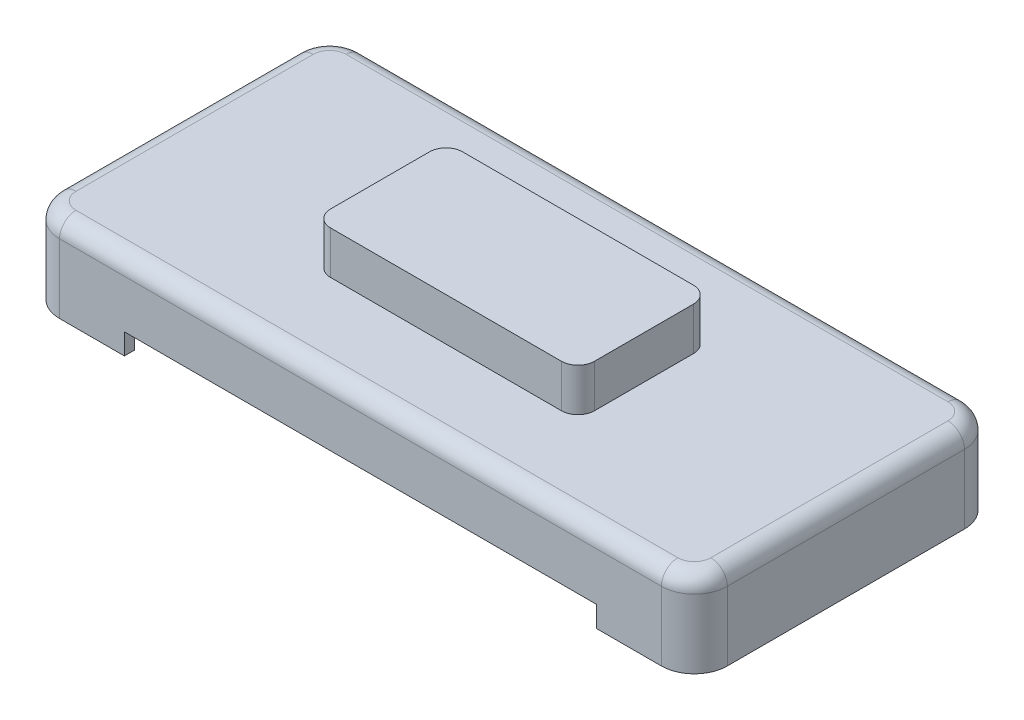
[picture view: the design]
ISO-10303-21;
HEADER;
FILE_DESCRIPTION(('STEP AP214'),'2;1');
FILE_NAME('part.step','',(''),(''),'','','');
FILE_SCHEMA(('AUTOMOTIVE_DESIGN { 1 0 10303 214 1 1 1 1 }'));
ENDSEC;
DATA;
#1=APPLICATION_CONTEXT('core data for automotive mechanical design processes');
#2=APPLICATION_PROTOCOL_DEFINITION('international standard','automotive_design',2000,#1);
#3=PRODUCT_CONTEXT('',#1,'mechanical');
#4=PRODUCT('Part','Part','',(#3));
#5=PRODUCT_RELATED_PRODUCT_CATEGORY('part','',(#4));
#6=PRODUCT_DEFINITION_FORMATION('','',#4);
#7=PRODUCT_DEFINITION_CONTEXT('part definition',#1,'design');
#8=PRODUCT_DEFINITION('design','',#6,#7);
#9=PRODUCT_DEFINITION_SHAPE('','',#8);
#10=(LENGTH_UNIT() NAMED_UNIT(*) SI_UNIT(.MILLI.,.METRE.));
#11=(NAMED_UNIT(*) PLANE_ANGLE_UNIT() SI_UNIT($,.RADIAN.));
#12=(NAMED_UNIT(*) SI_UNIT($,.STERADIAN.) SOLID_ANGLE_UNIT());
#13=UNCERTAINTY_MEASURE_WITH_UNIT(LENGTH_MEASURE(1.E-05),#10,'distance_accuracy_value','');
#14=(GEOMETRIC_REPRESENTATION_CONTEXT(3) GLOBAL_UNCERTAINTY_ASSIGNED_CONTEXT((#13)) GLOBAL_UNIT_ASSIGNED_CONTEXT((#10,
#11,#12)) REPRESENTATION_CONTEXT('',''));
#15=CARTESIAN_POINT('',(0.,0.,0.));
#16=DIRECTION('',(0.,0.,1.));
#17=DIRECTION('',(1.,0.,0.));
#18=AXIS2_PLACEMENT_3D('',#15,#16,#17);
#19=CARTESIAN_POINT('',(-40.,38.9249069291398,20.));
#20=DIRECTION('',(1.,0.,0.));
#21=DIRECTION('',(0.,1.,0.));
#22=AXIS2_PLACEMENT_3D('',#19,#20,#21);
#23=PLANE('',#22);
#24=DIRECTION('',(0.,0.,-1.));
#25=VECTOR('',#24,1.);
#26=CARTESIAN_POINT('',(-40.,13.9249069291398,20.));
#27=LINE('',#26,#25);
#28=CARTESIAN_POINT('',(-40.,13.9249069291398,-15.));
#29=VERTEX_POINT('',#28);
#30=CARTESIAN_POINT('',(-40.,13.9249069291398,15.));
#31=VERTEX_POINT('',#30);
#32=EDGE_CURVE('E119',#29,#31,#27,.F.);
#33=ORIENTED_EDGE('',*,*,#32,.T.);
#34=DIRECTION('',(0.,-1.,0.));
#35=VECTOR('',#34,1.);
#36=CARTESIAN_POINT('',(-40.,38.9249069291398,15.));
#37=LINE('',#36,#35);
#38=CARTESIAN_POINT('',(-40.,38.9249069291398,15.));
#39=VERTEX_POINT('',#38);
#40=EDGE_CURVE('E154',#31,#39,#37,.F.);
#41=ORIENTED_EDGE('',*,*,#40,.T.);
#42=DIRECTION('',(0.,0.,-1.));
#43=VECTOR('',#42,1.);
#44=CARTESIAN_POINT('',(-40.,38.9249069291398,20.));
#45=LINE('',#44,#43);
#46=CARTESIAN_POINT('',(-40.,38.9249069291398,-15.));
#47=VERTEX_POINT('',#46);
#48=EDGE_CURVE('E181',#39,#47,#45,.T.);
#49=ORIENTED_EDGE('',*,*,#48,.T.);
#50=DIRECTION('',(0.,-1.,0.));
#51=VECTOR('',#50,1.);
#52=CARTESIAN_POINT('',(-40.,38.9249069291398,-15.));
#53=LINE('',#52,#51);
#54=EDGE_CURVE('E147',#47,#29,#53,.T.);
#55=ORIENTED_EDGE('',*,*,#54,.T.);
#56=EDGE_LOOP('',(#33,#41,#49,#55));
#57=FACE_BOUND('',#56,.T.);
#58=ADVANCED_FACE('F37',(#57),#23,.F.);
#59=CARTESIAN_POINT('',(-40.,8.92490692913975,20.));
#60=DIRECTION('',(0.,1.,0.));
#61=DIRECTION('',(0.,0.,1.));
#62=AXIS2_PLACEMENT_3D('',#59,#60,#61);
#63=PLANE('',#62);
#64=DIRECTION('',(1.,0.,0.));
#65=VECTOR('',#64,1.);
#66=CARTESIAN_POINT('',(-40.,8.92490692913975,15.));
#67=LINE('',#66,#65);
#68=CARTESIAN_POINT('',(35.,8.92490692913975,15.));
#69=VERTEX_POINT('',#68);
#70=CARTESIAN_POINT('',(-35.,8.92490692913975,15.));
#71=VERTEX_POINT('',#70);
#72=EDGE_CURVE('E145',#69,#71,#67,.F.);
#73=ORIENTED_EDGE('',*,*,#72,.T.);
#74=DIRECTION('',(0.,0.,-1.));
#75=VECTOR('',#74,1.);
#76=CARTESIAN_POINT('',(-35.,8.92490692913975,20.));
#77=LINE('',#76,#75);
#78=CARTESIAN_POINT('',(-35.,8.92490692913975,-15.));
#79=VERTEX_POINT('',#78);
#80=EDGE_CURVE('E117',#71,#79,#77,.T.);
#81=ORIENTED_EDGE('',*,*,#80,.T.);
#82=DIRECTION('',(1.,0.,0.));
#83=VECTOR('',#82,1.);
#84=CARTESIAN_POINT('',(-40.,8.92490692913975,-15.));
#85=LINE('',#84,#83);
#86=CARTESIAN_POINT('',(35.,8.92490692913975,-15.));
#87=VERTEX_POINT('',#86);
#88=EDGE_CURVE('E134',#79,#87,#85,.T.);
#89=ORIENTED_EDGE('',*,*,#88,.T.);
#90=DIRECTION('',(0.,0.,-1.));
#91=VECTOR('',#90,1.);
#92=CARTESIAN_POINT('',(35.,8.92490692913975,20.));
#93=LINE('',#92,#91);
#94=EDGE_CURVE('E140',#87,#69,#93,.F.);
#95=ORIENTED_EDGE('',*,*,#94,.T.);
#96=EDGE_LOOP('',(#73,#81,#89,#95));
#97=FACE_BOUND('',#96,.T.);
#98=ADVANCED_FACE('F143',(#97),#63,.F.);
#99=CARTESIAN_POINT('',(40.,38.9249069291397,20.));
#100=DIRECTION('',(-1.,0.,0.));
#101=DIRECTION('',(0.,0.,1.));
#102=AXIS2_PLACEMENT_3D('',#99,#100,#101);
#103=PLANE('',#102);
#104=DIRECTION('',(0.,0.,-1.));
#105=VECTOR('',#104,1.);
#106=CARTESIAN_POINT('',(40.,13.9249069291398,20.));
#107=LINE('',#106,#105);
#108=CARTESIAN_POINT('',(40.,13.9249069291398,15.));
#109=VERTEX_POINT('',#108);
#110=CARTESIAN_POINT('',(40.,13.9249069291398,-15.));
#111=VERTEX_POINT('',#110);
#112=EDGE_CURVE('E164',#109,#111,#107,.T.);
#113=ORIENTED_EDGE('',*,*,#112,.T.);
#114=DIRECTION('',(0.,1.,0.));
#115=VECTOR('',#114,1.);
#116=CARTESIAN_POINT('',(40.,38.9249069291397,-15.));
#117=LINE('',#116,#115);
#118=CARTESIAN_POINT('',(40.,38.9249069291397,-15.));
#119=VERTEX_POINT('',#118);
#120=EDGE_CURVE('E166',#111,#119,#117,.T.);
#121=ORIENTED_EDGE('',*,*,#120,.T.);
#122=DIRECTION('',(0.,0.,-1.));
#123=VECTOR('',#122,1.);
#124=CARTESIAN_POINT('',(40.,38.9249069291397,20.));
#125=LINE('',#124,#123);
#126=CARTESIAN_POINT('',(40.,38.9249069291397,15.));
#127=VERTEX_POINT('',#126);
#128=EDGE_CURVE('E141',#127,#119,#125,.T.);
#129=ORIENTED_EDGE('',*,*,#128,.F.);
#130=DIRECTION('',(0.,1.,0.));
#131=VECTOR('',#130,1.);
#132=CARTESIAN_POINT('',(40.,8.92490692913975,15.));
#133=LINE('',#132,#131);
#134=EDGE_CURVE('E162',#127,#109,#133,.F.);
#135=ORIENTED_EDGE('',*,*,#134,.T.);
#136=EDGE_LOOP('',(#113,#121,#129,#135));
#137=FACE_BOUND('',#136,.T.);
#138=ADVANCED_FACE('F249',(#137),#103,.F.);
#139=CARTESIAN_POINT('',(-40.,38.9249069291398,20.));
#140=DIRECTION('',(0.,-1.,0.));
#141=DIRECTION('',(1.,0.,0.));
#142=AXIS2_PLACEMENT_3D('',#139,#140,#141);
#143=PLANE('',#142);
#144=ORIENTED_EDGE('',*,*,#48,.F.);
#145=CARTESIAN_POINT('',(-35.,38.9249069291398,15.));
#146=DIRECTION('',(0.,-1.,0.));
#147=DIRECTION('',(1.,0.,0.));
#148=AXIS2_PLACEMENT_3D('',#145,#146,#147);
#149=CIRCLE('',#148,5.);
#150=CARTESIAN_POINT('',(-35.,38.9249069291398,20.));
#151=VERTEX_POINT('',#150);
#152=EDGE_CURVE('E12',#39,#151,#149,.F.);
#153=ORIENTED_EDGE('',*,*,#152,.T.);
#154=DIRECTION('',(-1.,0.,0.));
#155=VECTOR('',#154,1.);
#156=CARTESIAN_POINT('',(-40.,38.9249069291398,20.));
#157=LINE('',#156,#155);
#158=CARTESIAN_POINT('',(35.,38.9249069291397,20.));
#159=VERTEX_POINT('',#158);
#160=EDGE_CURVE('E188',#159,#151,#157,.T.);
#161=ORIENTED_EDGE('',*,*,#160,.F.);
#162=CARTESIAN_POINT('',(35.,38.9249069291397,15.));
#163=DIRECTION('',(0.,-1.,0.));
#164=DIRECTION('',(1.,0.,0.));
#165=AXIS2_PLACEMENT_3D('',#162,#163,#164);
#166=CIRCLE('',#165,5.);
#167=EDGE_CURVE('E172',#159,#127,#166,.F.);
#168=ORIENTED_EDGE('',*,*,#167,.T.);
#169=ORIENTED_EDGE('',*,*,#128,.T.);
#170=CARTESIAN_POINT('',(35.,38.9249069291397,-15.));
#171=DIRECTION('',(0.,-1.,0.));
#172=DIRECTION('',(1.,0.,0.));
#173=AXIS2_PLACEMENT_3D('',#170,#171,#172);
#174=CIRCLE('',#173,5.);
#175=CARTESIAN_POINT('',(35.,38.9249069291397,-20.));
#176=VERTEX_POINT('',#175);
#177=EDGE_CURVE('E174',#119,#176,#174,.F.);
#178=ORIENTED_EDGE('',*,*,#177,.T.);
#179=DIRECTION('',(-1.,0.,0.));
#180=VECTOR('',#179,1.);
#181=CARTESIAN_POINT('',(-40.,38.9249069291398,-20.));
#182=LINE('',#181,#180);
#183=CARTESIAN_POINT('',(-35.,38.9249069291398,-20.));
#184=VERTEX_POINT('',#183);
#185=EDGE_CURVE('E183',#176,#184,#182,.T.);
#186=ORIENTED_EDGE('',*,*,#185,.T.);
#187=CARTESIAN_POINT('',(-35.,38.9249069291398,-15.));
#188=DIRECTION('',(0.,-1.,0.));
#189=DIRECTION('',(1.,0.,0.));
#190=AXIS2_PLACEMENT_3D('',#187,#188,#189);
#191=CIRCLE('',#190,5.);
#192=EDGE_CURVE('E44',#184,#47,#191,.F.);
#193=ORIENTED_EDGE('',*,*,#192,.T.);
#194=EDGE_LOOP('',(#144,#153,#161,#168,#169,#178,#186,#193));
#195=FACE_BOUND('',#194,.T.);
#196=ADVANCED_FACE('F180',(#195),#143,.F.);
#197=CARTESIAN_POINT('',(-40.,8.92490692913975,20.));
#198=DIRECTION('',(0.,0.,1.));
#199=DIRECTION('',(1.,0.,0.));
#200=AXIS2_PLACEMENT_3D('',#197,#198,#199);
#201=PLANE('',#200);
#202=ORIENTED_EDGE('',*,*,#160,.T.);
#203=DIRECTION('',(0.,-1.,0.));
#204=VECTOR('',#203,1.);
#205=CARTESIAN_POINT('',(-35.,8.92490692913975,20.));
#206=LINE('',#205,#204);
#207=CARTESIAN_POINT('',(-35.,13.9249069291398,20.));
#208=VERTEX_POINT('',#207);
#209=EDGE_CURVE('E160',#151,#208,#206,.T.);
#210=ORIENTED_EDGE('',*,*,#209,.T.);
#211=DIRECTION('',(1.,0.,0.));
#212=VECTOR('',#211,1.);
#213=CARTESIAN_POINT('',(40.,13.9249069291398,20.));
#214=LINE('',#213,#212);
#215=CARTESIAN_POINT('',(35.,13.9249069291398,20.));
#216=VERTEX_POINT('',#215);
#217=EDGE_CURVE('E158',#208,#216,#214,.T.);
#218=ORIENTED_EDGE('',*,*,#217,.T.);
#219=DIRECTION('',(0.,1.,0.));
#220=VECTOR('',#219,1.);
#221=CARTESIAN_POINT('',(35.,38.9249069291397,20.));
#222=LINE('',#221,#220);
#223=EDGE_CURVE('E156',#216,#159,#222,.T.);
#224=ORIENTED_EDGE('',*,*,#223,.T.);
#225=EDGE_LOOP('',(#202,#210,#218,#224));
#226=FACE_BOUND('',#225,.T.);
#227=ADVANCED_FACE('F241',(#226),#201,.T.);
#228=CARTESIAN_POINT('',(-40.,8.92490692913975,-20.));
#229=DIRECTION('',(0.,0.,1.));
#230=DIRECTION('',(1.,0.,0.));
#231=AXIS2_PLACEMENT_3D('',#228,#229,#230);
#232=PLANE('',#231);
#233=DIRECTION('',(1.,0.,0.));
#234=VECTOR('',#233,1.);
#235=CARTESIAN_POINT('',(-40.,13.9249069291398,-20.));
#236=LINE('',#235,#234);
#237=CARTESIAN_POINT('',(35.,13.9249069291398,-20.));
#238=VERTEX_POINT('',#237);
#239=CARTESIAN_POINT('',(-35.,13.9249069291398,-20.));
#240=VERTEX_POINT('',#239);
#241=EDGE_CURVE('E51',#238,#240,#236,.F.);
#242=ORIENTED_EDGE('',*,*,#241,.T.);
#243=DIRECTION('',(0.,-1.,0.));
#244=VECTOR('',#243,1.);
#245=CARTESIAN_POINT('',(-35.,8.92490692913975,-20.));
#246=LINE('',#245,#244);
#247=EDGE_CURVE('E170',#240,#184,#246,.F.);
#248=ORIENTED_EDGE('',*,*,#247,.T.);
#249=ORIENTED_EDGE('',*,*,#185,.F.);
#250=DIRECTION('',(0.,1.,0.));
#251=VECTOR('',#250,1.);
#252=CARTESIAN_POINT('',(35.,8.92490692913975,-20.));
#253=LINE('',#252,#251);
#254=EDGE_CURVE('E56',#176,#238,#253,.F.);
#255=ORIENTED_EDGE('',*,*,#254,.T.);
#256=EDGE_LOOP('',(#242,#248,#249,#255));
#257=FACE_BOUND('',#256,.T.);
#258=ADVANCED_FACE('F276',(#257),#232,.F.);
#259=CARTESIAN_POINT('',(35.,8.92490692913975,15.));
#260=DIRECTION('',(0.,-1.,0.));
#261=DIRECTION('',(0.,0.,-1.));
#262=AXIS2_PLACEMENT_3D('',#259,#260,#261);
#263=CYLINDRICAL_SURFACE('',#262,5.);
#264=ORIENTED_EDGE('',*,*,#167,.F.);
#265=ORIENTED_EDGE('',*,*,#223,.F.);
#266=CARTESIAN_POINT('',(35.,13.9249069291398,15.));
#267=DIRECTION('',(0.,-1.,0.));
#268=DIRECTION('',(0.,0.,-1.));
#269=AXIS2_PLACEMENT_3D('',#266,#267,#268);
#270=CIRCLE('',#269,5.);
#271=EDGE_CURVE('E212',#109,#216,#270,.T.);
#272=ORIENTED_EDGE('',*,*,#271,.F.);
#273=ORIENTED_EDGE('',*,*,#134,.F.);
#274=EDGE_LOOP('',(#264,#265,#272,#273));
#275=FACE_BOUND('',#274,.T.);
#276=ADVANCED_FACE('F244',(#275),#263,.T.);
#277=CARTESIAN_POINT('',(35.,13.9249069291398,20.));
#278=DIRECTION('',(0.,0.,-1.));
#279=DIRECTION('',(-1.,0.,0.));
#280=AXIS2_PLACEMENT_3D('',#277,#278,#279);
#281=CYLINDRICAL_SURFACE('',#280,5.);
#282=CARTESIAN_POINT('',(35.,13.9249069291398,-15.));
#283=DIRECTION('',(0.,0.,-1.));
#284=DIRECTION('',(-1.,0.,0.));
#285=AXIS2_PLACEMENT_3D('',#282,#283,#284);
#286=CIRCLE('',#285,5.);
#287=EDGE_CURVE('E206',#111,#87,#286,.T.);
#288=ORIENTED_EDGE('',*,*,#287,.F.);
#289=ORIENTED_EDGE('',*,*,#112,.F.);
#290=CARTESIAN_POINT('',(35.,13.9249069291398,15.));
#291=DIRECTION('',(0.,0.,1.));
#292=DIRECTION('',(1.,0.,0.));
#293=AXIS2_PLACEMENT_3D('',#290,#291,#292);
#294=CIRCLE('',#293,5.);
#295=EDGE_CURVE('E209',#69,#109,#294,.T.);
#296=ORIENTED_EDGE('',*,*,#295,.F.);
#297=ORIENTED_EDGE('',*,*,#94,.F.);
#298=EDGE_LOOP('',(#288,#289,#296,#297));
#299=FACE_BOUND('',#298,.T.);
#300=ADVANCED_FACE('F224',(#299),#281,.T.);
#301=CARTESIAN_POINT('',(35.,38.9249069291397,-15.));
#302=DIRECTION('',(0.,1.,0.));
#303=DIRECTION('',(0.,0.,1.));
#304=AXIS2_PLACEMENT_3D('',#301,#302,#303);
#305=CYLINDRICAL_SURFACE('',#304,5.);
#306=ORIENTED_EDGE('',*,*,#177,.F.);
#307=ORIENTED_EDGE('',*,*,#120,.F.);
#308=CARTESIAN_POINT('',(35.,13.9249069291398,-15.));
#309=DIRECTION('',(0.,-1.,0.));
#310=DIRECTION('',(0.,0.,-1.));
#311=AXIS2_PLACEMENT_3D('',#308,#309,#310);
#312=CIRCLE('',#311,5.);
#313=EDGE_CURVE('E203',#238,#111,#312,.T.);
#314=ORIENTED_EDGE('',*,*,#313,.F.);
#315=ORIENTED_EDGE('',*,*,#254,.F.);
#316=EDGE_LOOP('',(#306,#307,#314,#315));
#317=FACE_BOUND('',#316,.T.);
#318=ADVANCED_FACE('F252',(#317),#305,.T.);
#319=CARTESIAN_POINT('',(35.,13.9249069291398,15.));
#320=DIRECTION('',(0.,0.,1.));
#321=DIRECTION('',(1.,0.,0.));
#322=AXIS2_PLACEMENT_3D('',#319,#320,#321);
#323=SPHERICAL_SURFACE('',#322,5.);
#324=ORIENTED_EDGE('',*,*,#295,.T.);
#325=ORIENTED_EDGE('',*,*,#271,.T.);
#326=CARTESIAN_POINT('',(35.,13.9249069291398,15.));
#327=DIRECTION('',(1.,0.,0.));
#328=DIRECTION('',(0.,0.,-1.));
#329=AXIS2_PLACEMENT_3D('',#326,#327,#328);
#330=CIRCLE('',#329,5.);
#331=EDGE_CURVE('E200',#69,#216,#330,.F.);
#332=ORIENTED_EDGE('',*,*,#331,.F.);
#333=EDGE_LOOP('',(#324,#325,#332));
#334=FACE_BOUND('',#333,.T.);
#335=ADVANCED_FACE('F227',(#334),#323,.T.);
#336=CARTESIAN_POINT('',(35.,13.9249069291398,-15.));
#337=DIRECTION('',(0.,0.,1.));
#338=DIRECTION('',(1.,0.,0.));
#339=AXIS2_PLACEMENT_3D('',#336,#337,#338);
#340=SPHERICAL_SURFACE('',#339,5.);
#341=ORIENTED_EDGE('',*,*,#313,.T.);
#342=ORIENTED_EDGE('',*,*,#287,.T.);
#343=CARTESIAN_POINT('',(35.,13.9249069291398,-15.));
#344=DIRECTION('',(1.,0.,0.));
#345=DIRECTION('',(0.,0.,-1.));
#346=AXIS2_PLACEMENT_3D('',#343,#344,#345);
#347=CIRCLE('',#346,5.);
#348=EDGE_CURVE('E137',#238,#87,#347,.F.);
#349=ORIENTED_EDGE('',*,*,#348,.F.);
#350=EDGE_LOOP('',(#341,#342,#349));
#351=FACE_BOUND('',#350,.T.);
#352=ADVANCED_FACE('F254',(#351),#340,.T.);
#353=CARTESIAN_POINT('',(-35.,8.92490692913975,15.));
#354=DIRECTION('',(0.,1.,0.));
#355=DIRECTION('',(-1.,0.,0.));
#356=AXIS2_PLACEMENT_3D('',#353,#354,#355);
#357=CYLINDRICAL_SURFACE('',#356,5.);
#358=ORIENTED_EDGE('',*,*,#152,.F.);
#359=ORIENTED_EDGE('',*,*,#40,.F.);
#360=CARTESIAN_POINT('',(-35.,13.9249069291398,15.));
#361=DIRECTION('',(0.,-1.,0.));
#362=DIRECTION('',(1.,0.,0.));
#363=AXIS2_PLACEMENT_3D('',#360,#361,#362);
#364=CIRCLE('',#363,5.);
#365=EDGE_CURVE('E196',#208,#31,#364,.T.);
#366=ORIENTED_EDGE('',*,*,#365,.F.);
#367=ORIENTED_EDGE('',*,*,#209,.F.);
#368=EDGE_LOOP('',(#358,#359,#366,#367));
#369=FACE_BOUND('',#368,.T.);
#370=ADVANCED_FACE('F237',(#369),#357,.T.);
#371=CARTESIAN_POINT('',(-40.,13.9249069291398,15.));
#372=DIRECTION('',(-1.,0.,0.));
#373=DIRECTION('',(0.,0.,1.));
#374=AXIS2_PLACEMENT_3D('',#371,#372,#373);
#375=CYLINDRICAL_SURFACE('',#374,5.);
#376=ORIENTED_EDGE('',*,*,#331,.T.);
#377=ORIENTED_EDGE('',*,*,#217,.F.);
#378=CARTESIAN_POINT('',(-35.,13.9249069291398,15.));
#379=DIRECTION('',(-1.,0.,0.));
#380=DIRECTION('',(0.,0.,1.));
#381=AXIS2_PLACEMENT_3D('',#378,#379,#380);
#382=CIRCLE('',#381,5.);
#383=EDGE_CURVE('E131',#71,#208,#382,.T.);
#384=ORIENTED_EDGE('',*,*,#383,.F.);
#385=ORIENTED_EDGE('',*,*,#72,.F.);
#386=EDGE_LOOP('',(#376,#377,#384,#385));
#387=FACE_BOUND('',#386,.T.);
#388=ADVANCED_FACE('F230',(#387),#375,.T.);
#389=CARTESIAN_POINT('',(-40.,13.9249069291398,-15.));
#390=DIRECTION('',(1.,0.,0.));
#391=DIRECTION('',(0.,0.,-1.));
#392=AXIS2_PLACEMENT_3D('',#389,#390,#391);
#393=CYLINDRICAL_SURFACE('',#392,5.);
#394=ORIENTED_EDGE('',*,*,#348,.T.);
#395=ORIENTED_EDGE('',*,*,#88,.F.);
#396=CARTESIAN_POINT('',(-35.,13.9249069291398,-15.));
#397=DIRECTION('',(-1.,0.,0.));
#398=DIRECTION('',(0.,0.,1.));
#399=AXIS2_PLACEMENT_3D('',#396,#397,#398);
#400=CIRCLE('',#399,5.);
#401=EDGE_CURVE('E125',#240,#79,#400,.T.);
#402=ORIENTED_EDGE('',*,*,#401,.F.);
#403=ORIENTED_EDGE('',*,*,#241,.F.);
#404=EDGE_LOOP('',(#394,#395,#402,#403));
#405=FACE_BOUND('',#404,.T.);
#406=ADVANCED_FACE('F135',(#405),#393,.T.);
#407=CARTESIAN_POINT('',(-35.,38.9249069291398,-15.));
#408=DIRECTION('',(0.,-1.,0.));
#409=DIRECTION('',(1.,0.,0.));
#410=AXIS2_PLACEMENT_3D('',#407,#408,#409);
#411=CYLINDRICAL_SURFACE('',#410,5.);
#412=ORIENTED_EDGE('',*,*,#192,.F.);
#413=ORIENTED_EDGE('',*,*,#247,.F.);
#414=CARTESIAN_POINT('',(-35.,13.9249069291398,-15.));
#415=DIRECTION('',(0.,-1.,0.));
#416=DIRECTION('',(1.,0.,0.));
#417=AXIS2_PLACEMENT_3D('',#414,#415,#416);
#418=CIRCLE('',#417,5.);
#419=EDGE_CURVE('E129',#29,#240,#418,.T.);
#420=ORIENTED_EDGE('',*,*,#419,.F.);
#421=ORIENTED_EDGE('',*,*,#54,.F.);
#422=EDGE_LOOP('',(#412,#413,#420,#421));
#423=FACE_BOUND('',#422,.T.);
#424=ADVANCED_FACE('F190',(#423),#411,.T.);
#425=CARTESIAN_POINT('',(-35.,13.9249069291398,15.));
#426=DIRECTION('',(0.,0.,1.));
#427=DIRECTION('',(1.,0.,0.));
#428=AXIS2_PLACEMENT_3D('',#425,#426,#427);
#429=SPHERICAL_SURFACE('',#428,5.);
#430=ORIENTED_EDGE('',*,*,#383,.T.);
#431=ORIENTED_EDGE('',*,*,#365,.T.);
#432=CARTESIAN_POINT('',(-35.,13.9249069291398,15.));
#433=DIRECTION('',(0.,0.,1.));
#434=DIRECTION('',(1.,0.,0.));
#435=AXIS2_PLACEMENT_3D('',#432,#433,#434);
#436=CIRCLE('',#435,5.);
#437=EDGE_CURVE('E122',#71,#31,#436,.F.);
#438=ORIENTED_EDGE('',*,*,#437,.F.);
#439=EDGE_LOOP('',(#430,#431,#438));
#440=FACE_BOUND('',#439,.T.);
#441=ADVANCED_FACE('F234',(#440),#429,.T.);
#442=CARTESIAN_POINT('',(-35.,13.9249069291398,-15.));
#443=DIRECTION('',(0.,0.,1.));
#444=DIRECTION('',(1.,0.,0.));
#445=AXIS2_PLACEMENT_3D('',#442,#443,#444);
#446=SPHERICAL_SURFACE('',#445,5.);
#447=ORIENTED_EDGE('',*,*,#419,.T.);
#448=ORIENTED_EDGE('',*,*,#401,.T.);
#449=CARTESIAN_POINT('',(-35.,13.9249069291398,-15.));
#450=DIRECTION('',(0.,0.,-1.));
#451=DIRECTION('',(-1.,0.,0.));
#452=AXIS2_PLACEMENT_3D('',#449,#450,#451);
#453=CIRCLE('',#452,5.);
#454=EDGE_CURVE('E113',#29,#79,#453,.F.);
#455=ORIENTED_EDGE('',*,*,#454,.F.);
#456=EDGE_LOOP('',(#447,#448,#455));
#457=FACE_BOUND('',#456,.T.);
#458=ADVANCED_FACE('F127',(#457),#446,.T.);
#459=CARTESIAN_POINT('',(-35.,13.9249069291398,20.));
#460=DIRECTION('',(0.,0.,-1.));
#461=DIRECTION('',(-1.,0.,0.));
#462=AXIS2_PLACEMENT_3D('',#459,#460,#461);
#463=CYLINDRICAL_SURFACE('',#462,5.);
#464=ORIENTED_EDGE('',*,*,#437,.T.);
#465=ORIENTED_EDGE('',*,*,#32,.F.);
#466=ORIENTED_EDGE('',*,*,#454,.T.);
#467=ORIENTED_EDGE('',*,*,#80,.F.);
#468=EDGE_LOOP('',(#464,#465,#466,#467));
#469=FACE_BOUND('',#468,.T.);
#470=ADVANCED_FACE('F115',(#469),#463,.T.);
#471=CLOSED_SHELL('',(#58,#98,#138,#196,#227,#258,#276,#300,#318,#335,#352,#370,#388,#406,#424,
#441,#458,#470));
#472=MANIFOLD_SOLID_BREP('B2',#471);
#473=CARTESIAN_POINT('',(-101.226470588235,25.9249069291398,42.9441176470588));
#474=DIRECTION('',(0.,0.,-1.));
#475=DIRECTION('',(-1.,0.,0.));
#476=AXIS2_PLACEMENT_3D('',#473,#474,#475);
#477=PLANE('',#476);
#478=DIRECTION('',(-1.,0.,0.));
#479=VECTOR('',#478,1.);
#480=CARTESIAN_POINT('',(-101.226470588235,11.6154181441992,42.9441176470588));
#481=LINE('',#480,#479);
#482=CARTESIAN_POINT('',(1.5,11.6154181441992,42.9441176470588));
#483=VERTEX_POINT('',#482);
#484=CARTESIAN_POINT('',(-1.5,11.6154181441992,42.9441176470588));
#485=VERTEX_POINT('',#484);
#486=EDGE_CURVE('E1026',#483,#485,#481,.T.);
#487=ORIENTED_EDGE('',*,*,#486,.F.);
#488=DIRECTION('',(0.,1.,0.));
#489=VECTOR('',#488,1.);
#490=CARTESIAN_POINT('',(1.5,25.9249069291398,42.9441176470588));
#491=LINE('',#490,#489);
#492=CARTESIAN_POINT('',(1.5,20.9249069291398,42.9441176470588));
#493=VERTEX_POINT('',#492);
#494=EDGE_CURVE('E1296',#483,#493,#491,.T.);
#495=ORIENTED_EDGE('',*,*,#494,.T.);
#496=DIRECTION('',(-1.,0.,0.));
#497=VECTOR('',#496,1.);
#498=CARTESIAN_POINT('',(-101.226470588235,20.9249069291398,42.9441176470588));
#499=LINE('',#498,#497);
#500=CARTESIAN_POINT('',(49.9252123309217,20.9249069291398,42.9441176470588));
#501=VERTEX_POINT('',#500);
#502=EDGE_CURVE('E1753',#501,#493,#499,.T.);
#503=ORIENTED_EDGE('',*,*,#502,.F.);
#504=DIRECTION('',(0.,1.,0.));
#505=VECTOR('',#504,1.);
#506=CARTESIAN_POINT('',(49.9252123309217,25.9249069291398,42.9441176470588));
#507=LINE('',#506,#505);
#508=CARTESIAN_POINT('',(49.9252123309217,11.6154181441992,42.9441176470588));
#509=VERTEX_POINT('',#508);
#510=EDGE_CURVE('E1217',#509,#501,#507,.T.);
#511=ORIENTED_EDGE('',*,*,#510,.F.);
#512=DIRECTION('',(-1.,0.,0.));
#513=VECTOR('',#512,1.);
#514=CARTESIAN_POINT('',(-101.226470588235,11.6154181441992,42.9441176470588));
#515=LINE('',#514,#513);
#516=CARTESIAN_POINT('',(52.9252123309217,11.6154181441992,42.9441176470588));
#517=VERTEX_POINT('',#516);
#518=EDGE_CURVE('E1230',#517,#509,#515,.T.);
#519=ORIENTED_EDGE('',*,*,#518,.F.);
#520=DIRECTION('',(0.,1.,0.));
#521=VECTOR('',#520,1.);
#522=CARTESIAN_POINT('',(52.9252123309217,25.9249069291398,42.9441176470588));
#523=LINE('',#522,#521);
#524=CARTESIAN_POINT('',(52.9252123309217,20.9249069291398,42.9441176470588));
#525=VERTEX_POINT('',#524);
#526=EDGE_CURVE('E1212',#517,#525,#523,.T.);
#527=ORIENTED_EDGE('',*,*,#526,.T.);
#528=CARTESIAN_POINT('',(91.2264705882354,20.9249069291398,42.9441176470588));
#529=VERTEX_POINT('',#528);
#530=EDGE_CURVE('E1750',#529,#525,#499,.T.);
#531=ORIENTED_EDGE('',*,*,#530,.F.);
#532=DIRECTION('',(0.,1.,0.));
#533=VECTOR('',#532,1.);
#534=CARTESIAN_POINT('',(91.2264705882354,25.9249069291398,42.9441176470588));
#535=LINE('',#534,#533);
#536=CARTESIAN_POINT('',(91.2264705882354,0.,42.9441176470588));
#537=VERTEX_POINT('',#536);
#538=EDGE_CURVE('E1738',#537,#529,#535,.T.);
#539=ORIENTED_EDGE('',*,*,#538,.F.);
#540=DIRECTION('',(1.,0.,0.));
#541=VECTOR('',#540,1.);
#542=CARTESIAN_POINT('',(-101.226470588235,0.,42.9441176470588));
#543=LINE('',#542,#541);
#544=CARTESIAN_POINT('',(71.5742721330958,0.,42.9441176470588));
#545=VERTEX_POINT('',#544);
#546=EDGE_CURVE('E1507',#545,#537,#543,.T.);
#547=ORIENTED_EDGE('',*,*,#546,.F.);
#548=DIRECTION('',(0.,-1.,0.));
#549=VECTOR('',#548,1.);
#550=CARTESIAN_POINT('',(71.5742721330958,25.9249069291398,42.9441176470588));
#551=LINE('',#550,#549);
#552=CARTESIAN_POINT('',(71.5742721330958,6.34634427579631,42.9441176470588));
#553=VERTEX_POINT('',#552);
#554=EDGE_CURVE('E1716',#553,#545,#551,.T.);
#555=ORIENTED_EDGE('',*,*,#554,.F.);
#556=DIRECTION('',(1.,0.,0.));
#557=VECTOR('',#556,1.);
#558=CARTESIAN_POINT('',(-101.226470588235,6.34634427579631,42.9441176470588));
#559=LINE('',#558,#557);
#560=CARTESIAN_POINT('',(-71.5742721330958,6.34634427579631,42.9441176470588));
#561=VERTEX_POINT('',#560);
#562=EDGE_CURVE('E1729',#561,#553,#559,.T.);
#563=ORIENTED_EDGE('',*,*,#562,.F.);
#564=DIRECTION('',(0.,1.,0.));
#565=VECTOR('',#564,1.);
#566=CARTESIAN_POINT('',(-71.5742721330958,25.9249069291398,42.9441176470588));
#567=LINE('',#566,#565);
#568=CARTESIAN_POINT('',(-71.5742721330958,0.,42.9441176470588));
#569=VERTEX_POINT('',#568);
#570=EDGE_CURVE('E1503',#569,#561,#567,.T.);
#571=ORIENTED_EDGE('',*,*,#570,.F.);
#572=CARTESIAN_POINT('',(-91.2264705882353,0.,42.9441176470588));
#573=VERTEX_POINT('',#572);
#574=EDGE_CURVE('E1524',#573,#569,#543,.T.);
#575=ORIENTED_EDGE('',*,*,#574,.F.);
#576=DIRECTION('',(0.,1.,0.));
#577=VECTOR('',#576,1.);
#578=CARTESIAN_POINT('',(-91.2264705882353,25.9249069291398,42.9441176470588));
#579=LINE('',#578,#577);
#580=CARTESIAN_POINT('',(-91.2264705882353,20.9249069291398,42.9441176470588));
#581=VERTEX_POINT('',#580);
#582=EDGE_CURVE('E1739',#581,#573,#579,.F.);
#583=ORIENTED_EDGE('',*,*,#582,.F.);
#584=CARTESIAN_POINT('',(-52.9252123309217,20.9249069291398,42.9441176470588));
#585=VERTEX_POINT('',#584);
#586=EDGE_CURVE('E1742',#585,#581,#499,.T.);
#587=ORIENTED_EDGE('',*,*,#586,.F.);
#588=DIRECTION('',(0.,1.,0.));
#589=VECTOR('',#588,1.);
#590=CARTESIAN_POINT('',(-52.9252123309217,25.9249069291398,42.9441176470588));
#591=LINE('',#590,#589);
#592=CARTESIAN_POINT('',(-52.9252123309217,11.6154181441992,42.9441176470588));
#593=VERTEX_POINT('',#592);
#594=EDGE_CURVE('E1134',#593,#585,#591,.T.);
#595=ORIENTED_EDGE('',*,*,#594,.F.);
#596=DIRECTION('',(-1.,0.,0.));
#597=VECTOR('',#596,1.);
#598=CARTESIAN_POINT('',(-101.226470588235,11.6154181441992,42.9441176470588));
#599=LINE('',#598,#597);
#600=CARTESIAN_POINT('',(-49.9252123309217,11.6154181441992,42.9441176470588));
#601=VERTEX_POINT('',#600);
#602=EDGE_CURVE('E1145',#601,#593,#599,.T.);
#603=ORIENTED_EDGE('',*,*,#602,.F.);
#604=DIRECTION('',(0.,1.,0.));
#605=VECTOR('',#604,1.);
#606=CARTESIAN_POINT('',(-49.9252123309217,25.9249069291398,42.9441176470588));
#607=LINE('',#606,#605);
#608=CARTESIAN_POINT('',(-49.9252123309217,20.9249069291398,42.9441176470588));
#609=VERTEX_POINT('',#608);
#610=EDGE_CURVE('E1131',#601,#609,#607,.T.);
#611=ORIENTED_EDGE('',*,*,#610,.T.);
#612=CARTESIAN_POINT('',(-1.5,20.9249069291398,42.9441176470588));
#613=VERTEX_POINT('',#612);
#614=EDGE_CURVE('E1754',#613,#609,#499,.T.);
#615=ORIENTED_EDGE('',*,*,#614,.F.);
#616=DIRECTION('',(0.,1.,0.));
#617=VECTOR('',#616,1.);
#618=CARTESIAN_POINT('',(-1.5,25.9249069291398,42.9441176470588));
#619=LINE('',#618,#617);
#620=EDGE_CURVE('E1301',#485,#613,#619,.T.);
#621=ORIENTED_EDGE('',*,*,#620,.F.);
#622=EDGE_LOOP('',(#487,#495,#503,#511,#519,#527,#531,#539,#547,#555,#563,#571,#575,#583,#587,
#595,#603,#611,#615,#621));
#623=FACE_BOUND('',#622,.T.);
#624=ADVANCED_FACE('F365',(#623),#477,.T.);
#625=CARTESIAN_POINT('',(-101.226470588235,22.9249069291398,45.9441176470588));
#626=DIRECTION('',(0.,1.,0.));
#627=DIRECTION('',(0.,0.,1.));
#628=AXIS2_PLACEMENT_3D('',#625,#626,#627);
#629=PLANE('',#628);
#630=DIRECTION('',(0.,0.,-1.));
#631=VECTOR('',#630,1.);
#632=CARTESIAN_POINT('',(-1.5,22.9249069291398,45.9441176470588));
#633=LINE('',#632,#631);
#634=CARTESIAN_POINT('',(-1.5,22.9249069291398,-1.5));
#635=VERTEX_POINT('',#634);
#636=CARTESIAN_POINT('',(-1.5,22.9249069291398,-26.4680979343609));
#637=VERTEX_POINT('',#636);
#638=EDGE_CURVE('E1346',#635,#637,#633,.T.);
#639=ORIENTED_EDGE('',*,*,#638,.F.);
#640=DIRECTION('',(1.,0.,0.));
#641=VECTOR('',#640,1.);
#642=CARTESIAN_POINT('',(-101.226470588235,22.9249069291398,-1.5));
#643=LINE('',#642,#641);
#644=CARTESIAN_POINT('',(-49.9252123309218,22.9249069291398,-1.5));
#645=VERTEX_POINT('',#644);
#646=EDGE_CURVE('E1405',#645,#635,#643,.T.);
#647=ORIENTED_EDGE('',*,*,#646,.F.);
#648=DIRECTION('',(0.,0.,-1.));
#649=VECTOR('',#648,1.);
#650=CARTESIAN_POINT('',(-49.9252123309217,22.9249069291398,45.9441176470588));
#651=LINE('',#650,#649);
#652=CARTESIAN_POINT('',(-49.9252123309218,22.9249069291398,-26.4680979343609));
#653=VERTEX_POINT('',#652);
#654=EDGE_CURVE('E1163',#645,#653,#651,.T.);
#655=ORIENTED_EDGE('',*,*,#654,.T.);
#656=DIRECTION('',(1.,0.,0.));
#657=VECTOR('',#656,1.);
#658=CARTESIAN_POINT('',(-101.226470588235,22.9249069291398,-26.4680979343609));
#659=LINE('',#658,#657);
#660=EDGE_CURVE('E1421',#653,#637,#659,.T.);
#661=ORIENTED_EDGE('',*,*,#660,.T.);
#662=EDGE_LOOP('',(#639,#647,#655,#661));
#663=FACE_BOUND('',#662,.T.);
#664=ADVANCED_FACE('F2095',(#663),#629,.F.);
#665=DIRECTION('',(0.,0.,-1.));
#666=VECTOR('',#665,1.);
#667=CARTESIAN_POINT('',(-1.5,22.9249069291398,45.9441176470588));
#668=LINE('',#667,#666);
#669=CARTESIAN_POINT('',(-1.5,22.9249069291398,26.4680979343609));
#670=VERTEX_POINT('',#669);
#671=CARTESIAN_POINT('',(-1.5,22.9249069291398,1.5));
#672=VERTEX_POINT('',#671);
#673=EDGE_CURVE('E1339',#670,#672,#668,.T.);
#674=ORIENTED_EDGE('',*,*,#673,.F.);
#675=DIRECTION('',(1.,0.,0.));
#676=VECTOR('',#675,1.);
#677=CARTESIAN_POINT('',(-101.226470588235,22.9249069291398,26.4680979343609));
#678=LINE('',#677,#676);
#679=CARTESIAN_POINT('',(-49.9252123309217,22.9249069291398,26.4680979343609));
#680=VERTEX_POINT('',#679);
#681=EDGE_CURVE('E1651',#680,#670,#678,.T.);
#682=ORIENTED_EDGE('',*,*,#681,.F.);
#683=DIRECTION('',(0.,0.,-1.));
#684=VECTOR('',#683,1.);
#685=CARTESIAN_POINT('',(-49.9252123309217,22.9249069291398,45.9441176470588));
#686=LINE('',#685,#684);
#687=CARTESIAN_POINT('',(-49.9252123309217,22.9249069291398,1.5));
#688=VERTEX_POINT('',#687);
#689=EDGE_CURVE('E1155',#680,#688,#686,.T.);
#690=ORIENTED_EDGE('',*,*,#689,.T.);
#691=DIRECTION('',(1.,0.,0.));
#692=VECTOR('',#691,1.);
#693=CARTESIAN_POINT('',(-101.226470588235,22.9249069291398,1.5));
#694=LINE('',#693,#692);
#695=EDGE_CURVE('E1395',#688,#672,#694,.T.);
#696=ORIENTED_EDGE('',*,*,#695,.T.);
#697=EDGE_LOOP('',(#674,#682,#690,#696));
#698=FACE_BOUND('',#697,.T.);
#699=ADVANCED_FACE('F1874',(#698),#629,.F.);
#700=DIRECTION('',(0.,0.,-1.));
#701=VECTOR('',#700,1.);
#702=CARTESIAN_POINT('',(-1.5,22.9249069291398,45.9441176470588));
#703=LINE('',#702,#701);
#704=CARTESIAN_POINT('',(-1.5,22.9249069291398,-29.4680979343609));
#705=VERTEX_POINT('',#704);
#706=CARTESIAN_POINT('',(-1.5,22.9249069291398,-40.9441176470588));
#707=VERTEX_POINT('',#706);
#708=EDGE_CURVE('E1311',#705,#707,#703,.T.);
#709=ORIENTED_EDGE('',*,*,#708,.F.);
#710=DIRECTION('',(1.,0.,0.));
#711=VECTOR('',#710,1.);
#712=CARTESIAN_POINT('',(-101.226470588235,22.9249069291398,-29.4680979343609));
#713=LINE('',#712,#711);
#714=CARTESIAN_POINT('',(-49.9252123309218,22.9249069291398,-29.4680979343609));
#715=VERTEX_POINT('',#714);
#716=EDGE_CURVE('E1427',#715,#705,#713,.T.);
#717=ORIENTED_EDGE('',*,*,#716,.F.);
#718=DIRECTION('',(0.,0.,-1.));
#719=VECTOR('',#718,1.);
#720=CARTESIAN_POINT('',(-49.9252123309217,22.9249069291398,45.9441176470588));
#721=LINE('',#720,#719);
#722=CARTESIAN_POINT('',(-49.9252123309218,22.9249069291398,-40.9441176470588));
#723=VERTEX_POINT('',#722);
#724=EDGE_CURVE('E1140',#715,#723,#721,.T.);
#725=ORIENTED_EDGE('',*,*,#724,.T.);
#726=DIRECTION('',(1.,0.,0.));
#727=VECTOR('',#726,1.);
#728=CARTESIAN_POINT('',(-101.226470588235,22.9249069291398,-40.9441176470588));
#729=LINE('',#728,#727);
#730=EDGE_CURVE('E1779',#707,#723,#729,.F.);
#731=ORIENTED_EDGE('',*,*,#730,.F.);
#732=EDGE_LOOP('',(#709,#717,#725,#731));
#733=FACE_BOUND('',#732,.T.);
#734=ADVANCED_FACE('F1902',(#733),#629,.F.);
#735=CARTESIAN_POINT('',(-101.226470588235,20.9249069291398,-40.9441176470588));
#736=DIRECTION('',(1.,0.,0.));
#737=DIRECTION('',(0.,0.,-1.));
#738=AXIS2_PLACEMENT_3D('',#735,#736,#737);
#739=CYLINDRICAL_SURFACE('',#738,2.);
#740=CARTESIAN_POINT('',(-1.5,20.9249069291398,-40.9441176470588));
#741=DIRECTION('',(1.,0.,0.));
#742=DIRECTION('',(0.,0.,-1.));
#743=AXIS2_PLACEMENT_3D('',#740,#741,#742);
#744=CIRCLE('',#743,2.);
#745=CARTESIAN_POINT('',(-1.5,20.9249069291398,-42.9441176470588));
#746=VERTEX_POINT('',#745);
#747=EDGE_CURVE('E1313',#707,#746,#744,.F.);
#748=ORIENTED_EDGE('',*,*,#747,.F.);
#749=ORIENTED_EDGE('',*,*,#730,.T.);
#750=CARTESIAN_POINT('',(-49.9252123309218,20.9249069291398,-40.9441176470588));
#751=DIRECTION('',(1.,0.,0.));
#752=DIRECTION('',(0.,0.,-1.));
#753=AXIS2_PLACEMENT_3D('',#750,#751,#752);
#754=CIRCLE('',#753,2.);
#755=CARTESIAN_POINT('',(-49.9252123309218,20.9249069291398,-42.9441176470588));
#756=VERTEX_POINT('',#755);
#757=EDGE_CURVE('E1438',#723,#756,#754,.F.);
#758=ORIENTED_EDGE('',*,*,#757,.T.);
#759=DIRECTION('',(1.,0.,0.));
#760=VECTOR('',#759,1.);
#761=CARTESIAN_POINT('',(-101.226470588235,20.9249069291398,-42.9441176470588));
#762=LINE('',#761,#760);
#763=EDGE_CURVE('E1460',#756,#746,#762,.T.);
#764=ORIENTED_EDGE('',*,*,#763,.T.);
#765=EDGE_LOOP('',(#748,#749,#758,#764));
#766=FACE_BOUND('',#765,.T.);
#767=ADVANCED_FACE('F1464',(#766),#739,.F.);
#768=CARTESIAN_POINT('',(-92.3247964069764,11.6154181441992,29.4680979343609));
#769=DIRECTION('',(0.,0.,1.));
#770=DIRECTION('',(1.,0.,0.));
#771=AXIS2_PLACEMENT_3D('',#768,#769,#770);
#772=PLANE('',#771);
#773=DIRECTION('',(1.,0.,0.));
#774=VECTOR('',#773,1.);
#775=CARTESIAN_POINT('',(-92.3247964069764,11.6154181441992,29.4680979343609));
#776=LINE('',#775,#774);
#777=CARTESIAN_POINT('',(-49.9252123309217,11.6154181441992,29.4680979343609));
#778=VERTEX_POINT('',#777);
#779=CARTESIAN_POINT('',(-1.5,11.6154181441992,29.4680979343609));
#780=VERTEX_POINT('',#779);
#781=EDGE_CURVE('E1023',#778,#780,#776,.T.);
#782=ORIENTED_EDGE('',*,*,#781,.T.);
#783=DIRECTION('',(0.,1.,0.));
#784=VECTOR('',#783,1.);
#785=CARTESIAN_POINT('',(-1.5,11.6154181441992,29.4680979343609));
#786=LINE('',#785,#784);
#787=CARTESIAN_POINT('',(-1.5,22.9249069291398,29.4680979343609));
#788=VERTEX_POINT('',#787);
#789=EDGE_CURVE('E1005',#780,#788,#786,.T.);
#790=ORIENTED_EDGE('',*,*,#789,.T.);
#791=DIRECTION('',(1.,0.,0.));
#792=VECTOR('',#791,1.);
#793=CARTESIAN_POINT('',(-101.226470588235,22.9249069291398,29.4680979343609));
#794=LINE('',#793,#792);
#795=CARTESIAN_POINT('',(-49.9252123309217,22.9249069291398,29.4680979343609));
#796=VERTEX_POINT('',#795);
#797=EDGE_CURVE('E1645',#796,#788,#794,.T.);
#798=ORIENTED_EDGE('',*,*,#797,.F.);
#799=DIRECTION('',(0.,1.,0.));
#800=VECTOR('',#799,1.);
#801=CARTESIAN_POINT('',(-49.9252123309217,11.6154181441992,29.4680979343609));
#802=LINE('',#801,#800);
#803=EDGE_CURVE('E1034',#778,#796,#802,.T.);
#804=ORIENTED_EDGE('',*,*,#803,.F.);
#805=EDGE_LOOP('',(#782,#790,#798,#804));
#806=FACE_BOUND('',#805,.T.);
#807=ADVANCED_FACE('F1032',(#806),#772,.T.);
#808=CARTESIAN_POINT('',(-92.3247964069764,11.6154181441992,26.4680979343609));
#809=DIRECTION('',(0.,0.,1.));
#810=DIRECTION('',(1.,0.,0.));
#811=AXIS2_PLACEMENT_3D('',#808,#809,#810);
#812=PLANE('',#811);
#813=DIRECTION('',(0.,1.,0.));
#814=VECTOR('',#813,1.);
#815=CARTESIAN_POINT('',(-1.5,11.6154181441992,26.4680979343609));
#816=LINE('',#815,#814);
#817=CARTESIAN_POINT('',(-1.5,11.6154181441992,26.4680979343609));
#818=VERTEX_POINT('',#817);
#819=EDGE_CURVE('E1337',#818,#670,#816,.T.);
#820=ORIENTED_EDGE('',*,*,#819,.F.);
#821=DIRECTION('',(1.,0.,0.));
#822=VECTOR('',#821,1.);
#823=CARTESIAN_POINT('',(-92.3247964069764,11.6154181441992,26.4680979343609));
#824=LINE('',#823,#822);
#825=CARTESIAN_POINT('',(-49.9252123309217,11.6154181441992,26.4680979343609));
#826=VERTEX_POINT('',#825);
#827=EDGE_CURVE('E1049',#826,#818,#824,.T.);
#828=ORIENTED_EDGE('',*,*,#827,.F.);
#829=DIRECTION('',(0.,1.,0.));
#830=VECTOR('',#829,1.);
#831=CARTESIAN_POINT('',(-49.9252123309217,11.6154181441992,26.4680979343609));
#832=LINE('',#831,#830);
#833=EDGE_CURVE('E1152',#826,#680,#832,.T.);
#834=ORIENTED_EDGE('',*,*,#833,.T.);
#835=ORIENTED_EDGE('',*,*,#681,.T.);
#836=EDGE_LOOP('',(#820,#828,#834,#835));
#837=FACE_BOUND('',#836,.T.);
#838=ADVANCED_FACE('F2305',(#837),#812,.F.);
#839=CARTESIAN_POINT('',(-92.3247964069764,11.6154181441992,1.5));
#840=DIRECTION('',(0.,0.,1.));
#841=DIRECTION('',(1.,0.,0.));
#842=AXIS2_PLACEMENT_3D('',#839,#840,#841);
#843=PLANE('',#842);
#844=DIRECTION('',(1.,0.,0.));
#845=VECTOR('',#844,1.);
#846=CARTESIAN_POINT('',(-92.3247964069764,11.6154181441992,1.5));
#847=LINE('',#846,#845);
#848=CARTESIAN_POINT('',(-49.9252123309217,11.6154181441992,1.5));
#849=VERTEX_POINT('',#848);
#850=CARTESIAN_POINT('',(-1.5,11.6154181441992,1.5));
#851=VERTEX_POINT('',#850);
#852=EDGE_CURVE('E1089',#849,#851,#847,.T.);
#853=ORIENTED_EDGE('',*,*,#852,.T.);
#854=DIRECTION('',(0.,1.,0.));
#855=VECTOR('',#854,1.);
#856=CARTESIAN_POINT('',(-1.5,11.6154181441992,1.5));
#857=LINE('',#856,#855);
#858=EDGE_CURVE('E1341',#851,#672,#857,.T.);
#859=ORIENTED_EDGE('',*,*,#858,.T.);
#860=ORIENTED_EDGE('',*,*,#695,.F.);
#861=DIRECTION('',(0.,1.,0.));
#862=VECTOR('',#861,1.);
#863=CARTESIAN_POINT('',(-49.9252123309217,11.6154181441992,1.5));
#864=LINE('',#863,#862);
#865=EDGE_CURVE('E1158',#849,#688,#864,.T.);
#866=ORIENTED_EDGE('',*,*,#865,.F.);
#867=EDGE_LOOP('',(#853,#859,#860,#866));
#868=FACE_BOUND('',#867,.T.);
#869=ADVANCED_FACE('F1879',(#868),#843,.T.);
#870=CARTESIAN_POINT('',(-92.3247964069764,11.6154181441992,-1.5));
#871=DIRECTION('',(0.,0.,1.));
#872=DIRECTION('',(1.,0.,0.));
#873=AXIS2_PLACEMENT_3D('',#870,#871,#872);
#874=PLANE('',#873);
#875=DIRECTION('',(0.,1.,0.));
#876=VECTOR('',#875,1.);
#877=CARTESIAN_POINT('',(-1.5,11.6154181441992,-1.5));
#878=LINE('',#877,#876);
#879=CARTESIAN_POINT('',(-1.5,11.6154181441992,-1.5));
#880=VERTEX_POINT('',#879);
#881=EDGE_CURVE('E1344',#880,#635,#878,.T.);
#882=ORIENTED_EDGE('',*,*,#881,.F.);
#883=DIRECTION('',(1.,0.,0.));
#884=VECTOR('',#883,1.);
#885=CARTESIAN_POINT('',(-92.3247964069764,11.6154181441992,-1.5));
#886=LINE('',#885,#884);
#887=CARTESIAN_POINT('',(-49.9252123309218,11.6154181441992,-1.5));
#888=VERTEX_POINT('',#887);
#889=EDGE_CURVE('E1094',#888,#880,#886,.T.);
#890=ORIENTED_EDGE('',*,*,#889,.F.);
#891=DIRECTION('',(0.,1.,0.));
#892=VECTOR('',#891,1.);
#893=CARTESIAN_POINT('',(-49.9252123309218,11.6154181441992,-1.5));
#894=LINE('',#893,#892);
#895=EDGE_CURVE('E1160',#888,#645,#894,.T.);
#896=ORIENTED_EDGE('',*,*,#895,.T.);
#897=ORIENTED_EDGE('',*,*,#646,.T.);
#898=EDGE_LOOP('',(#882,#890,#896,#897));
#899=FACE_BOUND('',#898,.T.);
#900=ADVANCED_FACE('F2091',(#899),#874,.F.);
#901=CARTESIAN_POINT('',(-92.3247964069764,11.6154181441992,-26.4680979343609));
#902=DIRECTION('',(0.,0.,1.));
#903=DIRECTION('',(1.,0.,0.));
#904=AXIS2_PLACEMENT_3D('',#901,#902,#903);
#905=PLANE('',#904);
#906=DIRECTION('',(1.,0.,0.));
#907=VECTOR('',#906,1.);
#908=CARTESIAN_POINT('',(-92.3247964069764,11.6154181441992,-26.4680979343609));
#909=LINE('',#908,#907);
#910=CARTESIAN_POINT('',(-49.9252123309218,11.6154181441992,-26.4680979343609));
#911=VERTEX_POINT('',#910);
#912=CARTESIAN_POINT('',(-1.5,11.6154181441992,-26.4680979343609));
#913=VERTEX_POINT('',#912);
#914=EDGE_CURVE('E1119',#911,#913,#909,.T.);
#915=ORIENTED_EDGE('',*,*,#914,.T.);
#916=DIRECTION('',(0.,1.,0.));
#917=VECTOR('',#916,1.);
#918=CARTESIAN_POINT('',(-1.5,11.6154181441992,-26.4680979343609));
#919=LINE('',#918,#917);
#920=EDGE_CURVE('E1348',#913,#637,#919,.T.);
#921=ORIENTED_EDGE('',*,*,#920,.T.);
#922=ORIENTED_EDGE('',*,*,#660,.F.);
#923=DIRECTION('',(0.,1.,0.));
#924=VECTOR('',#923,1.);
#925=CARTESIAN_POINT('',(-49.9252123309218,11.6154181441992,-26.4680979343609));
#926=LINE('',#925,#924);
#927=EDGE_CURVE('E1166',#911,#653,#926,.T.);
#928=ORIENTED_EDGE('',*,*,#927,.F.);
#929=EDGE_LOOP('',(#915,#921,#922,#928));
#930=FACE_BOUND('',#929,.T.);
#931=ADVANCED_FACE('F2101',(#930),#905,.T.);
#932=CARTESIAN_POINT('',(-92.3247964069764,11.6154181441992,-29.4680979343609));
#933=DIRECTION('',(0.,0.,1.));
#934=DIRECTION('',(1.,0.,0.));
#935=AXIS2_PLACEMENT_3D('',#932,#933,#934);
#936=PLANE('',#935);
#937=DIRECTION('',(0.,1.,0.));
#938=VECTOR('',#937,1.);
#939=CARTESIAN_POINT('',(-1.5,11.6154181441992,-29.4680979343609));
#940=LINE('',#939,#938);
#941=CARTESIAN_POINT('',(-1.5,11.6154181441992,-29.4680979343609));
#942=VERTEX_POINT('',#941);
#943=EDGE_CURVE('E1016',#942,#705,#940,.T.);
#944=ORIENTED_EDGE('',*,*,#943,.F.);
#945=DIRECTION('',(1.,0.,0.));
#946=VECTOR('',#945,1.);
#947=CARTESIAN_POINT('',(-92.3247964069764,11.6154181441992,-29.4680979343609));
#948=LINE('',#947,#946);
#949=CARTESIAN_POINT('',(-49.9252123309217,11.6154181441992,-29.4680979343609));
#950=VERTEX_POINT('',#949);
#951=EDGE_CURVE('E1125',#950,#942,#948,.T.);
#952=ORIENTED_EDGE('',*,*,#951,.F.);
#953=DIRECTION('',(0.,1.,0.));
#954=VECTOR('',#953,1.);
#955=CARTESIAN_POINT('',(-49.9252123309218,11.6154181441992,-29.4680979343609));
#956=LINE('',#955,#954);
#957=EDGE_CURVE('E1168',#950,#715,#956,.T.);
#958=ORIENTED_EDGE('',*,*,#957,.T.);
#959=ORIENTED_EDGE('',*,*,#716,.T.);
#960=EDGE_LOOP('',(#944,#952,#958,#959));
#961=FACE_BOUND('',#960,.T.);
#962=ADVANCED_FACE('F1898',(#961),#936,.F.);
#963=DIRECTION('',(1.,0.,0.));
#964=VECTOR('',#963,1.);
#965=CARTESIAN_POINT('',(-101.226470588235,22.9249069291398,40.9441176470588));
#966=LINE('',#965,#964);
#967=CARTESIAN_POINT('',(1.5,22.9249069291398,40.9441176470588));
#968=VERTEX_POINT('',#967);
#969=CARTESIAN_POINT('',(49.9252123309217,22.9249069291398,40.9441176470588));
#970=VERTEX_POINT('',#969);
#971=EDGE_CURVE('E1796',#968,#970,#966,.T.);
#972=ORIENTED_EDGE('',*,*,#971,.F.);
#973=DIRECTION('',(0.,0.,-1.));
#974=VECTOR('',#973,1.);
#975=CARTESIAN_POINT('',(1.5,22.9249069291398,45.9441176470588));
#976=LINE('',#975,#974);
#977=CARTESIAN_POINT('',(1.5,22.9249069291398,29.4680979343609));
#978=VERTEX_POINT('',#977);
#979=EDGE_CURVE('E1334',#968,#978,#976,.T.);
#980=ORIENTED_EDGE('',*,*,#979,.T.);
#981=CARTESIAN_POINT('',(49.9252123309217,22.9249069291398,29.4680979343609));
#982=VERTEX_POINT('',#981);
#983=EDGE_CURVE('E1646',#978,#982,#794,.T.);
#984=ORIENTED_EDGE('',*,*,#983,.T.);
#985=DIRECTION('',(0.,0.,-1.));
#986=VECTOR('',#985,1.);
#987=CARTESIAN_POINT('',(49.9252123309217,22.9249069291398,45.9441176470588));
#988=LINE('',#987,#986);
#989=EDGE_CURVE('E1255',#970,#982,#988,.T.);
#990=ORIENTED_EDGE('',*,*,#989,.F.);
#991=EDGE_LOOP('',(#972,#980,#984,#990));
#992=FACE_BOUND('',#991,.T.);
#993=ADVANCED_FACE('F2418',(#992),#629,.F.);
#994=CARTESIAN_POINT('',(-101.226470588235,20.9249069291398,40.9441176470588));
#995=DIRECTION('',(-1.,0.,0.));
#996=DIRECTION('',(0.,0.,1.));
#997=AXIS2_PLACEMENT_3D('',#994,#995,#996);
#998=CYLINDRICAL_SURFACE('',#997,2.);
#999=CARTESIAN_POINT('',(1.5,20.9249069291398,40.9441176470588));
#1000=DIRECTION('',(-1.,0.,0.));
#1001=DIRECTION('',(0.,0.,1.));
#1002=AXIS2_PLACEMENT_3D('',#999,#1000,#1001);
#1003=CIRCLE('',#1002,2.);
#1004=EDGE_CURVE('E1299',#968,#493,#1003,.F.);
#1005=ORIENTED_EDGE('',*,*,#1004,.F.);
#1006=ORIENTED_EDGE('',*,*,#971,.T.);
#1007=CARTESIAN_POINT('',(49.9252123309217,20.9249069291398,40.9441176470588));
#1008=DIRECTION('',(-1.,0.,0.));
#1009=DIRECTION('',(0.,0.,1.));
#1010=AXIS2_PLACEMENT_3D('',#1007,#1008,#1009);
#1011=CIRCLE('',#1010,2.);
#1012=EDGE_CURVE('E1220',#970,#501,#1011,.F.);
#1013=ORIENTED_EDGE('',*,*,#1012,.T.);
#1014=ORIENTED_EDGE('',*,*,#502,.T.);
#1015=EDGE_LOOP('',(#1005,#1006,#1013,#1014));
#1016=FACE_BOUND('',#1015,.T.);
#1017=ADVANCED_FACE('F2174',(#1016),#998,.F.);
#1018=DIRECTION('',(0.,0.,1.));
#1019=VECTOR('',#1018,1.);
#1020=CARTESIAN_POINT('',(52.9252123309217,22.9249069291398,45.9441176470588));
#1021=LINE('',#1020,#1019);
#1022=CARTESIAN_POINT('',(52.9252123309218,22.9249069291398,29.4680979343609));
#1023=VERTEX_POINT('',#1022);
#1024=CARTESIAN_POINT('',(52.9252123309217,22.9249069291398,40.9441176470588));
#1025=VERTEX_POINT('',#1024);
#1026=EDGE_CURVE('E1209',#1023,#1025,#1021,.T.);
#1027=ORIENTED_EDGE('',*,*,#1026,.F.);
#1028=CARTESIAN_POINT('',(96.2264705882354,22.9249069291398,29.4680979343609));
#1029=VERTEX_POINT('',#1028);
#1030=EDGE_CURVE('E1650',#1023,#1029,#794,.T.);
#1031=ORIENTED_EDGE('',*,*,#1030,.T.);
#1032=DIRECTION('',(0.,0.,1.));
#1033=VECTOR('',#1032,1.);
#1034=CARTESIAN_POINT('',(96.2264705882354,22.9249069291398,45.9441176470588));
#1035=LINE('',#1034,#1033);
#1036=CARTESIAN_POINT('',(96.2264705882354,22.9249069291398,35.9441176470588));
#1037=VERTEX_POINT('',#1036);
#1038=EDGE_CURVE('E1480',#1037,#1029,#1035,.F.);
#1039=ORIENTED_EDGE('',*,*,#1038,.F.);
#1040=CARTESIAN_POINT('',(91.2264705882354,22.9249069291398,35.9441176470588));
#1041=DIRECTION('',(0.,1.,0.));
#1042=DIRECTION('',(0.,0.,1.));
#1043=AXIS2_PLACEMENT_3D('',#1040,#1041,#1042);
#1044=CIRCLE('',#1043,4.99999999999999);
#1045=CARTESIAN_POINT('',(91.2264705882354,22.9249069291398,40.9441176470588));
#1046=VERTEX_POINT('',#1045);
#1047=EDGE_CURVE('E1769',#1037,#1046,#1044,.F.);
#1048=ORIENTED_EDGE('',*,*,#1047,.T.);
#1049=EDGE_CURVE('E1788',#1025,#1046,#966,.T.);
#1050=ORIENTED_EDGE('',*,*,#1049,.F.);
#1051=EDGE_LOOP('',(#1027,#1031,#1039,#1048,#1050));
#1052=FACE_BOUND('',#1051,.T.);
#1053=ADVANCED_FACE('F1981',(#1052),#629,.F.);
#1054=CARTESIAN_POINT('',(52.9252123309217,20.9249069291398,40.9441176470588));
#1055=DIRECTION('',(-1.,0.,0.));
#1056=DIRECTION('',(0.,0.,1.));
#1057=AXIS2_PLACEMENT_3D('',#1054,#1055,#1056);
#1058=CIRCLE('',#1057,2.);
#1059=EDGE_CURVE('E1214',#1025,#525,#1058,.F.);
#1060=ORIENTED_EDGE('',*,*,#1059,.F.);
#1061=ORIENTED_EDGE('',*,*,#1049,.T.);
#1062=CARTESIAN_POINT('',(91.2264705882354,20.9249069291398,40.9441176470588));
#1063=DIRECTION('',(-1.,0.,0.));
#1064=DIRECTION('',(0.,0.,1.));
#1065=AXIS2_PLACEMENT_3D('',#1062,#1063,#1064);
#1066=CIRCLE('',#1065,2.);
#1067=EDGE_CURVE('E1760',#1046,#529,#1066,.F.);
#1068=ORIENTED_EDGE('',*,*,#1067,.T.);
#1069=ORIENTED_EDGE('',*,*,#530,.T.);
#1070=EDGE_LOOP('',(#1060,#1061,#1068,#1069));
#1071=FACE_BOUND('',#1070,.T.);
#1072=ADVANCED_FACE('F1973',(#1071),#998,.F.);
#1073=CARTESIAN_POINT('',(1.5,22.9249069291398,-1.5));
#1074=VERTEX_POINT('',#1073);
#1075=CARTESIAN_POINT('',(49.9252123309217,22.9249069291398,-1.5));
#1076=VERTEX_POINT('',#1075);
#1077=EDGE_CURVE('E1406',#1074,#1076,#643,.T.);
#1078=ORIENTED_EDGE('',*,*,#1077,.F.);
#1079=DIRECTION('',(0.,0.,-1.));
#1080=VECTOR('',#1079,1.);
#1081=CARTESIAN_POINT('',(1.5,22.9249069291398,45.9441176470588));
#1082=LINE('',#1081,#1080);
#1083=CARTESIAN_POINT('',(1.5,22.9249069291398,-26.4680979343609));
#1084=VERTEX_POINT('',#1083);
#1085=EDGE_CURVE('E1324',#1074,#1084,#1082,.T.);
#1086=ORIENTED_EDGE('',*,*,#1085,.T.);
#1087=CARTESIAN_POINT('',(49.9252123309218,22.9249069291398,-26.4680979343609));
#1088=VERTEX_POINT('',#1087);
#1089=EDGE_CURVE('E1422',#1084,#1088,#659,.T.);
#1090=ORIENTED_EDGE('',*,*,#1089,.T.);
#1091=DIRECTION('',(0.,0.,-1.));
#1092=VECTOR('',#1091,1.);
#1093=CARTESIAN_POINT('',(49.9252123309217,22.9249069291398,45.9441176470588));
#1094=LINE('',#1093,#1092);
#1095=EDGE_CURVE('E1273',#1076,#1088,#1094,.T.);
#1096=ORIENTED_EDGE('',*,*,#1095,.F.);
#1097=EDGE_LOOP('',(#1078,#1086,#1090,#1096));
#1098=FACE_BOUND('',#1097,.T.);
#1099=ADVANCED_FACE('F2294',(#1098),#629,.F.);
#1100=CARTESIAN_POINT('',(1.5,22.9249069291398,26.4680979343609));
#1101=VERTEX_POINT('',#1100);
#1102=CARTESIAN_POINT('',(49.9252123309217,22.9249069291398,26.4680979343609));
#1103=VERTEX_POINT('',#1102);
#1104=EDGE_CURVE('E1652',#1101,#1103,#678,.T.);
#1105=ORIENTED_EDGE('',*,*,#1104,.F.);
#1106=DIRECTION('',(0.,0.,-1.));
#1107=VECTOR('',#1106,1.);
#1108=CARTESIAN_POINT('',(1.5,22.9249069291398,45.9441176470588));
#1109=LINE('',#1108,#1107);
#1110=CARTESIAN_POINT('',(1.5,22.9249069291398,1.5));
#1111=VERTEX_POINT('',#1110);
#1112=EDGE_CURVE('E1318',#1101,#1111,#1109,.T.);
#1113=ORIENTED_EDGE('',*,*,#1112,.T.);
#1114=CARTESIAN_POINT('',(49.9252123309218,22.9249069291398,1.5));
#1115=VERTEX_POINT('',#1114);
#1116=EDGE_CURVE('E1367',#1111,#1115,#694,.T.);
#1117=ORIENTED_EDGE('',*,*,#1116,.T.);
#1118=DIRECTION('',(0.,0.,-1.));
#1119=VECTOR('',#1118,1.);
#1120=CARTESIAN_POINT('',(49.9252123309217,22.9249069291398,45.9441176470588));
#1121=LINE('',#1120,#1119);
#1122=EDGE_CURVE('E1264',#1103,#1115,#1121,.T.);
#1123=ORIENTED_EDGE('',*,*,#1122,.F.);
#1124=EDGE_LOOP('',(#1105,#1113,#1117,#1123));
#1125=FACE_BOUND('',#1124,.T.);
#1126=ADVANCED_FACE('F2288',(#1125),#629,.F.);
#1127=CARTESIAN_POINT('',(1.5,22.9249069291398,-29.4680979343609));
#1128=VERTEX_POINT('',#1127);
#1129=CARTESIAN_POINT('',(49.9252123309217,22.9249069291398,-29.4680979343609));
#1130=VERTEX_POINT('',#1129);
#1131=EDGE_CURVE('E1428',#1128,#1130,#713,.T.);
#1132=ORIENTED_EDGE('',*,*,#1131,.F.);
#1133=DIRECTION('',(0.,0.,-1.));
#1134=VECTOR('',#1133,1.);
#1135=CARTESIAN_POINT('',(1.5,22.9249069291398,45.9441176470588));
#1136=LINE('',#1135,#1134);
#1137=CARTESIAN_POINT('',(1.5,22.9249069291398,-40.9441176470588));
#1138=VERTEX_POINT('',#1137);
#1139=EDGE_CURVE('E1327',#1128,#1138,#1136,.T.);
#1140=ORIENTED_EDGE('',*,*,#1139,.T.);
#1141=CARTESIAN_POINT('',(49.9252123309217,22.9249069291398,-40.9441176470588));
#1142=VERTEX_POINT('',#1141);
#1143=EDGE_CURVE('E1778',#1142,#1138,#729,.F.);
#1144=ORIENTED_EDGE('',*,*,#1143,.F.);
#1145=DIRECTION('',(0.,0.,-1.));
#1146=VECTOR('',#1145,1.);
#1147=CARTESIAN_POINT('',(49.9252123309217,22.9249069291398,45.9441176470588));
#1148=LINE('',#1147,#1146);
#1149=EDGE_CURVE('E1279',#1130,#1142,#1148,.T.);
#1150=ORIENTED_EDGE('',*,*,#1149,.F.);
#1151=EDGE_LOOP('',(#1132,#1140,#1144,#1150));
#1152=FACE_BOUND('',#1151,.T.);
#1153=ADVANCED_FACE('F1831',(#1152),#629,.F.);
#1154=ORIENTED_EDGE('',*,*,#1143,.T.);
#1155=CARTESIAN_POINT('',(1.5,20.9249069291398,-40.9441176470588));
#1156=DIRECTION('',(1.,0.,0.));
#1157=DIRECTION('',(0.,0.,-1.));
#1158=AXIS2_PLACEMENT_3D('',#1155,#1156,#1157);
#1159=CIRCLE('',#1158,2.);
#1160=CARTESIAN_POINT('',(1.5,20.9249069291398,-42.9441176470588));
#1161=VERTEX_POINT('',#1160);
#1162=EDGE_CURVE('E1308',#1138,#1161,#1159,.F.);
#1163=ORIENTED_EDGE('',*,*,#1162,.T.);
#1164=CARTESIAN_POINT('',(49.9252123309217,20.9249069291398,-42.9441176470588));
#1165=VERTEX_POINT('',#1164);
#1166=EDGE_CURVE('E1468',#1161,#1165,#762,.T.);
#1167=ORIENTED_EDGE('',*,*,#1166,.T.);
#1168=CARTESIAN_POINT('',(49.9252123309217,20.9249069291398,-40.9441176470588));
#1169=DIRECTION('',(1.,0.,0.));
#1170=DIRECTION('',(0.,0.,-1.));
#1171=AXIS2_PLACEMENT_3D('',#1168,#1169,#1170);
#1172=CIRCLE('',#1171,2.);
#1173=EDGE_CURVE('E1444',#1142,#1165,#1172,.F.);
#1174=ORIENTED_EDGE('',*,*,#1173,.F.);
#1175=EDGE_LOOP('',(#1154,#1163,#1167,#1174));
#1176=FACE_BOUND('',#1175,.T.);
#1177=ADVANCED_FACE('F1825',(#1176),#739,.F.);
#1178=DIRECTION('',(0.,1.,0.));
#1179=VECTOR('',#1178,1.);
#1180=CARTESIAN_POINT('',(1.5,11.6154181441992,29.4680979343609));
#1181=LINE('',#1180,#1179);
#1182=CARTESIAN_POINT('',(1.5,11.6154181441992,29.4680979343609));
#1183=VERTEX_POINT('',#1182);
#1184=EDGE_CURVE('E1332',#1183,#978,#1181,.T.);
#1185=ORIENTED_EDGE('',*,*,#1184,.F.);
#1186=CARTESIAN_POINT('',(49.9252123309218,11.6154181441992,29.4680979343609));
#1187=VERTEX_POINT('',#1186);
#1188=EDGE_CURVE('E1036',#1183,#1187,#776,.T.);
#1189=ORIENTED_EDGE('',*,*,#1188,.T.);
#1190=DIRECTION('',(0.,1.,0.));
#1191=VECTOR('',#1190,1.);
#1192=CARTESIAN_POINT('',(49.9252123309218,11.6154181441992,29.4680979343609));
#1193=LINE('',#1192,#1191);
#1194=EDGE_CURVE('E1258',#1187,#982,#1193,.T.);
#1195=ORIENTED_EDGE('',*,*,#1194,.T.);
#1196=ORIENTED_EDGE('',*,*,#983,.F.);
#1197=EDGE_LOOP('',(#1185,#1189,#1195,#1196));
#1198=FACE_BOUND('',#1197,.T.);
#1199=ADVANCED_FACE('F2293',(#1198),#772,.T.);
#1200=CARTESIAN_POINT('',(1.5,11.6154181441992,26.4680979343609));
#1201=VERTEX_POINT('',#1200);
#1202=CARTESIAN_POINT('',(49.9252123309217,11.6154181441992,26.4680979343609));
#1203=VERTEX_POINT('',#1202);
#1204=EDGE_CURVE('E1050',#1201,#1203,#824,.T.);
#1205=ORIENTED_EDGE('',*,*,#1204,.F.);
#1206=DIRECTION('',(0.,1.,0.));
#1207=VECTOR('',#1206,1.);
#1208=CARTESIAN_POINT('',(1.5,11.6154181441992,26.4680979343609));
#1209=LINE('',#1208,#1207);
#1210=EDGE_CURVE('E1315',#1201,#1101,#1209,.T.);
#1211=ORIENTED_EDGE('',*,*,#1210,.T.);
#1212=ORIENTED_EDGE('',*,*,#1104,.T.);
#1213=DIRECTION('',(0.,1.,0.));
#1214=VECTOR('',#1213,1.);
#1215=CARTESIAN_POINT('',(49.9252123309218,11.6154181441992,26.4680979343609));
#1216=LINE('',#1215,#1214);
#1217=EDGE_CURVE('E1261',#1203,#1103,#1216,.T.);
#1218=ORIENTED_EDGE('',*,*,#1217,.F.);
#1219=EDGE_LOOP('',(#1205,#1211,#1212,#1218));
#1220=FACE_BOUND('',#1219,.T.);
#1221=ADVANCED_FACE('F2469',(#1220),#812,.F.);
#1222=DIRECTION('',(0.,1.,0.));
#1223=VECTOR('',#1222,1.);
#1224=CARTESIAN_POINT('',(1.5,11.6154181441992,1.5));
#1225=LINE('',#1224,#1223);
#1226=CARTESIAN_POINT('',(1.5,11.6154181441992,1.5));
#1227=VERTEX_POINT('',#1226);
#1228=EDGE_CURVE('E381',#1227,#1111,#1225,.T.);
#1229=ORIENTED_EDGE('',*,*,#1228,.F.);
#1230=CARTESIAN_POINT('',(49.9252123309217,11.6154181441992,1.5));
#1231=VERTEX_POINT('',#1230);
#1232=EDGE_CURVE('E1090',#1227,#1231,#847,.T.);
#1233=ORIENTED_EDGE('',*,*,#1232,.T.);
#1234=DIRECTION('',(0.,1.,0.));
#1235=VECTOR('',#1234,1.);
#1236=CARTESIAN_POINT('',(49.9252123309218,11.6154181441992,1.5));
#1237=LINE('',#1236,#1235);
#1238=EDGE_CURVE('E1267',#1231,#1115,#1237,.T.);
#1239=ORIENTED_EDGE('',*,*,#1238,.T.);
#1240=ORIENTED_EDGE('',*,*,#1116,.F.);
#1241=EDGE_LOOP('',(#1229,#1233,#1239,#1240));
#1242=FACE_BOUND('',#1241,.T.);
#1243=ADVANCED_FACE('F1365',(#1242),#843,.T.);
#1244=CARTESIAN_POINT('',(1.5,11.6154181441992,-1.5));
#1245=VERTEX_POINT('',#1244);
#1246=CARTESIAN_POINT('',(49.9252123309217,11.6154181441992,-1.5));
#1247=VERTEX_POINT('',#1246);
#1248=EDGE_CURVE('E1095',#1245,#1247,#886,.T.);
#1249=ORIENTED_EDGE('',*,*,#1248,.F.);
#1250=DIRECTION('',(0.,1.,0.));
#1251=VECTOR('',#1250,1.);
#1252=CARTESIAN_POINT('',(1.5,11.6154181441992,-1.5));
#1253=LINE('',#1252,#1251);
#1254=EDGE_CURVE('E1321',#1245,#1074,#1253,.T.);
#1255=ORIENTED_EDGE('',*,*,#1254,.T.);
#1256=ORIENTED_EDGE('',*,*,#1077,.T.);
#1257=DIRECTION('',(0.,1.,0.));
#1258=VECTOR('',#1257,1.);
#1259=CARTESIAN_POINT('',(49.9252123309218,11.6154181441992,-1.5));
#1260=LINE('',#1259,#1258);
#1261=EDGE_CURVE('E1270',#1247,#1076,#1260,.T.);
#1262=ORIENTED_EDGE('',*,*,#1261,.F.);
#1263=EDGE_LOOP('',(#1249,#1255,#1256,#1262));
#1264=FACE_BOUND('',#1263,.T.);
#1265=ADVANCED_FACE('F2492',(#1264),#874,.F.);
#1266=DIRECTION('',(0.,1.,0.));
#1267=VECTOR('',#1266,1.);
#1268=CARTESIAN_POINT('',(1.5,11.6154181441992,-26.4680979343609));
#1269=LINE('',#1268,#1267);
#1270=CARTESIAN_POINT('',(1.5,11.6154181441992,-26.4680979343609));
#1271=VERTEX_POINT('',#1270);
#1272=EDGE_CURVE('E389',#1271,#1084,#1269,.T.);
#1273=ORIENTED_EDGE('',*,*,#1272,.F.);
#1274=CARTESIAN_POINT('',(49.9252123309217,11.6154181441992,-26.4680979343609));
#1275=VERTEX_POINT('',#1274);
#1276=EDGE_CURVE('E1120',#1271,#1275,#909,.T.);
#1277=ORIENTED_EDGE('',*,*,#1276,.T.);
#1278=DIRECTION('',(0.,1.,0.));
#1279=VECTOR('',#1278,1.);
#1280=CARTESIAN_POINT('',(49.9252123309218,11.6154181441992,-26.4680979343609));
#1281=LINE('',#1280,#1279);
#1282=EDGE_CURVE('E1276',#1275,#1088,#1281,.T.);
#1283=ORIENTED_EDGE('',*,*,#1282,.T.);
#1284=ORIENTED_EDGE('',*,*,#1089,.F.);
#1285=EDGE_LOOP('',(#1273,#1277,#1283,#1284));
#1286=FACE_BOUND('',#1285,.T.);
#1287=ADVANCED_FACE('F2285',(#1286),#905,.T.);
#1288=CARTESIAN_POINT('',(1.5,11.6154181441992,-29.4680979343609));
#1289=VERTEX_POINT('',#1288);
#1290=CARTESIAN_POINT('',(49.9252123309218,11.6154181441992,-29.4680979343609));
#1291=VERTEX_POINT('',#1290);
#1292=EDGE_CURVE('E1126',#1289,#1291,#948,.T.);
#1293=ORIENTED_EDGE('',*,*,#1292,.F.);
#1294=DIRECTION('',(0.,1.,0.));
#1295=VECTOR('',#1294,1.);
#1296=CARTESIAN_POINT('',(1.5,11.6154181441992,-29.4680979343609));
#1297=LINE('',#1296,#1295);
#1298=EDGE_CURVE('E1329',#1289,#1128,#1297,.T.);
#1299=ORIENTED_EDGE('',*,*,#1298,.T.);
#1300=ORIENTED_EDGE('',*,*,#1131,.T.);
#1301=DIRECTION('',(0.,1.,0.));
#1302=VECTOR('',#1301,1.);
#1303=CARTESIAN_POINT('',(49.9252123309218,11.6154181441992,-29.4680979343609));
#1304=LINE('',#1303,#1302);
#1305=EDGE_CURVE('E1435',#1291,#1130,#1304,.T.);
#1306=ORIENTED_EDGE('',*,*,#1305,.F.);
#1307=EDGE_LOOP('',(#1293,#1299,#1300,#1306));
#1308=FACE_BOUND('',#1307,.T.);
#1309=ADVANCED_FACE('F1841',(#1308),#936,.F.);
#1310=DIRECTION('',(0.,0.,-1.));
#1311=VECTOR('',#1310,1.);
#1312=CARTESIAN_POINT('',(-52.9252123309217,22.9249069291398,45.9441176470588));
#1313=LINE('',#1312,#1311);
#1314=CARTESIAN_POINT('',(-52.9252123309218,22.9249069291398,-1.5));
#1315=VERTEX_POINT('',#1314);
#1316=CARTESIAN_POINT('',(-52.9252123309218,22.9249069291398,-26.4680979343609));
#1317=VERTEX_POINT('',#1316);
#1318=EDGE_CURVE('E1185',#1315,#1317,#1313,.T.);
#1319=ORIENTED_EDGE('',*,*,#1318,.F.);
#1320=CARTESIAN_POINT('',(-96.2264705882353,22.9249069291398,-1.5));
#1321=VERTEX_POINT('',#1320);
#1322=EDGE_CURVE('E1401',#1321,#1315,#643,.T.);
#1323=ORIENTED_EDGE('',*,*,#1322,.F.);
#1324=DIRECTION('',(0.,0.,1.));
#1325=VECTOR('',#1324,1.);
#1326=CARTESIAN_POINT('',(-96.2264705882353,22.9249069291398,45.9441176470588));
#1327=LINE('',#1326,#1325);
#1328=CARTESIAN_POINT('',(-96.2264705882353,22.9249069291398,-26.4680979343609));
#1329=VERTEX_POINT('',#1328);
#1330=EDGE_CURVE('E1789',#1329,#1321,#1327,.T.);
#1331=ORIENTED_EDGE('',*,*,#1330,.F.);
#1332=EDGE_CURVE('E1418',#1329,#1317,#659,.T.);
#1333=ORIENTED_EDGE('',*,*,#1332,.T.);
#1334=EDGE_LOOP('',(#1319,#1323,#1331,#1333));
#1335=FACE_BOUND('',#1334,.T.);
#1336=ADVANCED_FACE('F2126',(#1335),#629,.F.);
#1337=DIRECTION('',(0.,0.,-1.));
#1338=VECTOR('',#1337,1.);
#1339=CARTESIAN_POINT('',(-52.9252123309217,22.9249069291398,45.9441176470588));
#1340=LINE('',#1339,#1338);
#1341=CARTESIAN_POINT('',(-52.9252123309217,22.9249069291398,26.4680979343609));
#1342=VERTEX_POINT('',#1341);
#1343=CARTESIAN_POINT('',(-52.9252123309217,22.9249069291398,1.5));
#1344=VERTEX_POINT('',#1343);
#1345=EDGE_CURVE('E1178',#1342,#1344,#1340,.T.);
#1346=ORIENTED_EDGE('',*,*,#1345,.F.);
#1347=CARTESIAN_POINT('',(-96.2264705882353,22.9249069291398,26.4680979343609));
#1348=VERTEX_POINT('',#1347);
#1349=EDGE_CURVE('E1647',#1348,#1342,#678,.T.);
#1350=ORIENTED_EDGE('',*,*,#1349,.F.);
#1351=CARTESIAN_POINT('',(-96.2264705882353,22.9249069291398,1.5));
#1352=VERTEX_POINT('',#1351);
#1353=EDGE_CURVE('E1671',#1352,#1348,#1327,.T.);
#1354=ORIENTED_EDGE('',*,*,#1353,.F.);
#1355=EDGE_CURVE('E1390',#1352,#1344,#694,.T.);
#1356=ORIENTED_EDGE('',*,*,#1355,.T.);
#1357=EDGE_LOOP('',(#1346,#1350,#1354,#1356));
#1358=FACE_BOUND('',#1357,.T.);
#1359=ADVANCED_FACE('F2115',(#1358),#629,.F.);
#1360=ORIENTED_EDGE('',*,*,#797,.T.);
#1361=DIRECTION('',(0.,0.,1.));
#1362=VECTOR('',#1361,1.);
#1363=CARTESIAN_POINT('',(-1.5,22.9249069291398,45.9441176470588));
#1364=LINE('',#1363,#1362);
#1365=CARTESIAN_POINT('',(-1.5,22.9249069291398,40.9441176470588));
#1366=VERTEX_POINT('',#1365);
#1367=EDGE_CURVE('E1011',#788,#1366,#1364,.T.);
#1368=ORIENTED_EDGE('',*,*,#1367,.T.);
#1369=CARTESIAN_POINT('',(-49.9252123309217,22.9249069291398,40.9441176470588));
#1370=VERTEX_POINT('',#1369);
#1371=EDGE_CURVE('E1795',#1370,#1366,#966,.T.);
#1372=ORIENTED_EDGE('',*,*,#1371,.F.);
#1373=DIRECTION('',(0.,0.,1.));
#1374=VECTOR('',#1373,1.);
#1375=CARTESIAN_POINT('',(-49.9252123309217,22.9249069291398,45.9441176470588));
#1376=LINE('',#1375,#1374);
#1377=EDGE_CURVE('E1127',#796,#1370,#1376,.T.);
#1378=ORIENTED_EDGE('',*,*,#1377,.F.);
#1379=EDGE_LOOP('',(#1360,#1368,#1372,#1378));
#1380=FACE_BOUND('',#1379,.T.);
#1381=ADVANCED_FACE('F1988',(#1380),#629,.F.);
#1382=DIRECTION('',(0.,0.,-1.));
#1383=VECTOR('',#1382,1.);
#1384=CARTESIAN_POINT('',(-52.9252123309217,22.9249069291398,45.9441176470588));
#1385=LINE('',#1384,#1383);
#1386=CARTESIAN_POINT('',(-52.9252123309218,22.9249069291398,-29.4680979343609));
#1387=VERTEX_POINT('',#1386);
#1388=CARTESIAN_POINT('',(-52.9252123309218,22.9249069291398,-40.9441176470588));
#1389=VERTEX_POINT('',#1388);
#1390=EDGE_CURVE('E1190',#1387,#1389,#1385,.T.);
#1391=ORIENTED_EDGE('',*,*,#1390,.F.);
#1392=CARTESIAN_POINT('',(-96.2264705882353,22.9249069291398,-29.4680979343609));
#1393=VERTEX_POINT('',#1392);
#1394=EDGE_CURVE('E1423',#1393,#1387,#713,.T.);
#1395=ORIENTED_EDGE('',*,*,#1394,.F.);
#1396=CARTESIAN_POINT('',(-96.2264705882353,22.9249069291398,-35.9441176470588));
#1397=VERTEX_POINT('',#1396);
#1398=EDGE_CURVE('E1785',#1397,#1393,#1327,.T.);
#1399=ORIENTED_EDGE('',*,*,#1398,.F.);
#1400=CARTESIAN_POINT('',(-91.2264705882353,22.9249069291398,-35.9441176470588));
#1401=DIRECTION('',(0.,1.,0.));
#1402=DIRECTION('',(0.,0.,1.));
#1403=AXIS2_PLACEMENT_3D('',#1400,#1401,#1402);
#1404=CIRCLE('',#1403,5.);
#1405=CARTESIAN_POINT('',(-91.2264705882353,22.9249069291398,-40.9441176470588));
#1406=VERTEX_POINT('',#1405);
#1407=EDGE_CURVE('E1781',#1397,#1406,#1404,.F.);
#1408=ORIENTED_EDGE('',*,*,#1407,.T.);
#1409=EDGE_CURVE('E1780',#1389,#1406,#729,.F.);
#1410=ORIENTED_EDGE('',*,*,#1409,.F.);
#1411=EDGE_LOOP('',(#1391,#1395,#1399,#1408,#1410));
#1412=FACE_BOUND('',#1411,.T.);
#1413=ADVANCED_FACE('F1913',(#1412),#629,.F.);
#1414=ORIENTED_EDGE('',*,*,#1371,.T.);
#1415=CARTESIAN_POINT('',(-1.5,20.9249069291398,40.9441176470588));
#1416=DIRECTION('',(-1.,0.,0.));
#1417=DIRECTION('',(0.,0.,1.));
#1418=AXIS2_PLACEMENT_3D('',#1415,#1416,#1417);
#1419=CIRCLE('',#1418,2.);
#1420=EDGE_CURVE('E1304',#1366,#613,#1419,.F.);
#1421=ORIENTED_EDGE('',*,*,#1420,.T.);
#1422=ORIENTED_EDGE('',*,*,#614,.T.);
#1423=CARTESIAN_POINT('',(-49.9252123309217,20.9249069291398,40.9441176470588));
#1424=DIRECTION('',(-1.,0.,0.));
#1425=DIRECTION('',(0.,0.,1.));
#1426=AXIS2_PLACEMENT_3D('',#1423,#1424,#1425);
#1427=CIRCLE('',#1426,2.);
#1428=EDGE_CURVE('E1432',#1370,#609,#1427,.F.);
#1429=ORIENTED_EDGE('',*,*,#1428,.F.);
#1430=EDGE_LOOP('',(#1414,#1421,#1422,#1429));
#1431=FACE_BOUND('',#1430,.T.);
#1432=ADVANCED_FACE('F2175',(#1431),#998,.F.);
#1433=CARTESIAN_POINT('',(-52.9252123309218,20.9249069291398,-40.9441176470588));
#1434=DIRECTION('',(1.,0.,0.));
#1435=DIRECTION('',(0.,0.,-1.));
#1436=AXIS2_PLACEMENT_3D('',#1433,#1434,#1435);
#1437=CIRCLE('',#1436,2.);
#1438=CARTESIAN_POINT('',(-52.9252123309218,20.9249069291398,-42.9441176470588));
#1439=VERTEX_POINT('',#1438);
#1440=EDGE_CURVE('E1417',#1389,#1439,#1437,.F.);
#1441=ORIENTED_EDGE('',*,*,#1440,.F.);
#1442=ORIENTED_EDGE('',*,*,#1409,.T.);
#1443=CARTESIAN_POINT('',(-91.2264705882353,20.9249069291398,-40.9441176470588));
#1444=DIRECTION('',(1.,0.,0.));
#1445=DIRECTION('',(0.,0.,-1.));
#1446=AXIS2_PLACEMENT_3D('',#1443,#1444,#1445);
#1447=CIRCLE('',#1446,2.);
#1448=CARTESIAN_POINT('',(-91.2264705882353,20.9249069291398,-42.9441176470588));
#1449=VERTEX_POINT('',#1448);
#1450=EDGE_CURVE('E1500',#1449,#1406,#1447,.T.);
#1451=ORIENTED_EDGE('',*,*,#1450,.F.);
#1452=EDGE_CURVE('E1467',#1449,#1439,#762,.T.);
#1453=ORIENTED_EDGE('',*,*,#1452,.T.);
#1454=EDGE_LOOP('',(#1441,#1442,#1451,#1453));
#1455=FACE_BOUND('',#1454,.T.);
#1456=ADVANCED_FACE('F1818',(#1455),#739,.F.);
#1457=CARTESIAN_POINT('',(-98.2264705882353,11.6154181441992,29.468097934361));
#1458=VERTEX_POINT('',#1457);
#1459=CARTESIAN_POINT('',(-52.9252123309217,11.6154181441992,29.4680979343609));
#1460=VERTEX_POINT('',#1459);
#1461=EDGE_CURVE('E1035',#1458,#1460,#776,.T.);
#1462=ORIENTED_EDGE('',*,*,#1461,.T.);
#1463=DIRECTION('',(0.,1.,0.));
#1464=VECTOR('',#1463,1.);
#1465=CARTESIAN_POINT('',(-52.9252123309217,11.6154181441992,29.4680979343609));
#1466=LINE('',#1465,#1464);
#1467=CARTESIAN_POINT('',(-52.9252123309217,22.9249069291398,29.4680979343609));
#1468=VERTEX_POINT('',#1467);
#1469=EDGE_CURVE('E1174',#1460,#1468,#1466,.T.);
#1470=ORIENTED_EDGE('',*,*,#1469,.T.);
#1471=CARTESIAN_POINT('',(-96.2264705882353,22.9249069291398,29.4680979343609));
#1472=VERTEX_POINT('',#1471);
#1473=EDGE_CURVE('E1642',#1472,#1468,#794,.T.);
#1474=ORIENTED_EDGE('',*,*,#1473,.F.);
#1475=CARTESIAN_POINT('',(-96.2264705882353,20.9249069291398,29.4680979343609));
#1476=DIRECTION('',(0.,0.,-1.));
#1477=DIRECTION('',(-1.,0.,0.));
#1478=AXIS2_PLACEMENT_3D('',#1475,#1476,#1477);
#1479=CIRCLE('',#1478,2.);
#1480=CARTESIAN_POINT('',(-98.2264705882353,20.9249069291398,29.4680979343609));
#1481=VERTEX_POINT('',#1480);
#1482=EDGE_CURVE('E1658',#1472,#1481,#1479,.F.);
#1483=ORIENTED_EDGE('',*,*,#1482,.T.);
#1484=DIRECTION('',(0.,1.,0.));
#1485=VECTOR('',#1484,1.);
#1486=CARTESIAN_POINT('',(-98.2264705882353,25.9249069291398,29.4680979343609));
#1487=LINE('',#1486,#1485);
#1488=EDGE_CURVE('E1686',#1458,#1481,#1487,.T.);
#1489=ORIENTED_EDGE('',*,*,#1488,.F.);
#1490=EDGE_LOOP('',(#1462,#1470,#1474,#1483,#1489));
#1491=FACE_BOUND('',#1490,.T.);
#1492=ADVANCED_FACE('F2002',(#1491),#772,.T.);
#1493=DIRECTION('',(0.,1.,0.));
#1494=VECTOR('',#1493,1.);
#1495=CARTESIAN_POINT('',(-52.9252123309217,11.6154181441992,26.4680979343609));
#1496=LINE('',#1495,#1494);
#1497=CARTESIAN_POINT('',(-52.9252123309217,11.6154181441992,26.4680979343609));
#1498=VERTEX_POINT('',#1497);
#1499=EDGE_CURVE('E1176',#1498,#1342,#1496,.T.);
#1500=ORIENTED_EDGE('',*,*,#1499,.F.);
#1501=CARTESIAN_POINT('',(-98.2264705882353,11.6154181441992,26.4680979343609));
#1502=VERTEX_POINT('',#1501);
#1503=EDGE_CURVE('E1043',#1502,#1498,#824,.T.);
#1504=ORIENTED_EDGE('',*,*,#1503,.F.);
#1505=DIRECTION('',(0.,1.,0.));
#1506=VECTOR('',#1505,1.);
#1507=CARTESIAN_POINT('',(-98.2264705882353,25.9249069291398,26.4680979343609));
#1508=LINE('',#1507,#1506);
#1509=CARTESIAN_POINT('',(-98.2264705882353,20.9249069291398,26.4680979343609));
#1510=VERTEX_POINT('',#1509);
#1511=EDGE_CURVE('E1040',#1502,#1510,#1508,.T.);
#1512=ORIENTED_EDGE('',*,*,#1511,.T.);
#1513=CARTESIAN_POINT('',(-96.2264705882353,20.9249069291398,26.4680979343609));
#1514=DIRECTION('',(0.,0.,-1.));
#1515=DIRECTION('',(-1.,0.,0.));
#1516=AXIS2_PLACEMENT_3D('',#1513,#1514,#1515);
#1517=CIRCLE('',#1516,2.);
#1518=EDGE_CURVE('E1398',#1348,#1510,#1517,.F.);
#1519=ORIENTED_EDGE('',*,*,#1518,.F.);
#1520=ORIENTED_EDGE('',*,*,#1349,.T.);
#1521=EDGE_LOOP('',(#1500,#1504,#1512,#1519,#1520));
#1522=FACE_BOUND('',#1521,.T.);
#1523=ADVANCED_FACE('F1685',(#1522),#812,.F.);
#1524=CARTESIAN_POINT('',(-98.2264705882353,11.6154181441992,1.5));
#1525=VERTEX_POINT('',#1524);
#1526=CARTESIAN_POINT('',(-52.9252123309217,11.6154181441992,1.5));
#1527=VERTEX_POINT('',#1526);
#1528=EDGE_CURVE('E1086',#1525,#1527,#847,.T.);
#1529=ORIENTED_EDGE('',*,*,#1528,.T.);
#1530=DIRECTION('',(0.,1.,0.));
#1531=VECTOR('',#1530,1.);
#1532=CARTESIAN_POINT('',(-52.9252123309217,11.6154181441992,1.5));
#1533=LINE('',#1532,#1531);
#1534=EDGE_CURVE('E1180',#1527,#1344,#1533,.T.);
#1535=ORIENTED_EDGE('',*,*,#1534,.T.);
#1536=ORIENTED_EDGE('',*,*,#1355,.F.);
#1537=CARTESIAN_POINT('',(-96.2264705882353,20.9249069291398,1.5));
#1538=DIRECTION('',(0.,0.,-1.));
#1539=DIRECTION('',(-1.,0.,0.));
#1540=AXIS2_PLACEMENT_3D('',#1537,#1538,#1539);
#1541=CIRCLE('',#1540,2.);
#1542=CARTESIAN_POINT('',(-98.2264705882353,20.9249069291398,1.5));
#1543=VERTEX_POINT('',#1542);
#1544=EDGE_CURVE('E1407',#1352,#1543,#1541,.F.);
#1545=ORIENTED_EDGE('',*,*,#1544,.T.);
#1546=DIRECTION('',(0.,1.,0.));
#1547=VECTOR('',#1546,1.);
#1548=CARTESIAN_POINT('',(-98.2264705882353,25.9249069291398,1.5));
#1549=LINE('',#1548,#1547);
#1550=EDGE_CURVE('E1081',#1525,#1543,#1549,.T.);
#1551=ORIENTED_EDGE('',*,*,#1550,.F.);
#1552=EDGE_LOOP('',(#1529,#1535,#1536,#1545,#1551));
#1553=FACE_BOUND('',#1552,.T.);
#1554=ADVANCED_FACE('F2112',(#1553),#843,.T.);
#1555=DIRECTION('',(0.,1.,0.));
#1556=VECTOR('',#1555,1.);
#1557=CARTESIAN_POINT('',(-52.9252123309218,11.6154181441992,-1.5));
#1558=LINE('',#1557,#1556);
#1559=CARTESIAN_POINT('',(-52.9252123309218,11.6154181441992,-1.5));
#1560=VERTEX_POINT('',#1559);
#1561=EDGE_CURVE('E1183',#1560,#1315,#1558,.T.);
#1562=ORIENTED_EDGE('',*,*,#1561,.F.);
#1563=CARTESIAN_POINT('',(-98.2264705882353,11.6154181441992,-1.5));
#1564=VERTEX_POINT('',#1563);
#1565=EDGE_CURVE('E1091',#1564,#1560,#886,.T.);
#1566=ORIENTED_EDGE('',*,*,#1565,.F.);
#1567=DIRECTION('',(0.,1.,0.));
#1568=VECTOR('',#1567,1.);
#1569=CARTESIAN_POINT('',(-98.2264705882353,25.9249069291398,-1.5));
#1570=LINE('',#1569,#1568);
#1571=CARTESIAN_POINT('',(-98.2264705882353,20.9249069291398,-1.5));
#1572=VERTEX_POINT('',#1571);
#1573=EDGE_CURVE('E1083',#1564,#1572,#1570,.T.);
#1574=ORIENTED_EDGE('',*,*,#1573,.T.);
#1575=CARTESIAN_POINT('',(-96.2264705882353,20.9249069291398,-1.5));
#1576=DIRECTION('',(0.,0.,-1.));
#1577=DIRECTION('',(-1.,0.,0.));
#1578=AXIS2_PLACEMENT_3D('',#1575,#1576,#1577);
#1579=CIRCLE('',#1578,2.);
#1580=EDGE_CURVE('E1411',#1321,#1572,#1579,.F.);
#1581=ORIENTED_EDGE('',*,*,#1580,.F.);
#1582=ORIENTED_EDGE('',*,*,#1322,.T.);
#1583=EDGE_LOOP('',(#1562,#1566,#1574,#1581,#1582));
#1584=FACE_BOUND('',#1583,.T.);
#1585=ADVANCED_FACE('F2129',(#1584),#874,.F.);
#1586=CARTESIAN_POINT('',(-98.2264705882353,11.6154181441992,-26.4680979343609));
#1587=VERTEX_POINT('',#1586);
#1588=CARTESIAN_POINT('',(-52.9252123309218,11.6154181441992,-26.4680979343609));
#1589=VERTEX_POINT('',#1588);
#1590=EDGE_CURVE('E1116',#1587,#1589,#909,.T.);
#1591=ORIENTED_EDGE('',*,*,#1590,.T.);
#1592=DIRECTION('',(0.,1.,0.));
#1593=VECTOR('',#1592,1.);
#1594=CARTESIAN_POINT('',(-52.9252123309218,11.6154181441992,-26.4680979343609));
#1595=LINE('',#1594,#1593);
#1596=EDGE_CURVE('E1187',#1589,#1317,#1595,.T.);
#1597=ORIENTED_EDGE('',*,*,#1596,.T.);
#1598=ORIENTED_EDGE('',*,*,#1332,.F.);
#1599=CARTESIAN_POINT('',(-96.2264705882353,20.9249069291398,-26.4680979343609));
#1600=DIRECTION('',(0.,0.,-1.));
#1601=DIRECTION('',(-1.,0.,0.));
#1602=AXIS2_PLACEMENT_3D('',#1599,#1600,#1601);
#1603=CIRCLE('',#1602,2.);
#1604=CARTESIAN_POINT('',(-98.2264705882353,20.9249069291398,-26.4680979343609));
#1605=VERTEX_POINT('',#1604);
#1606=EDGE_CURVE('E1392',#1329,#1605,#1603,.F.);
#1607=ORIENTED_EDGE('',*,*,#1606,.T.);
#1608=DIRECTION('',(0.,1.,0.));
#1609=VECTOR('',#1608,1.);
#1610=CARTESIAN_POINT('',(-98.2264705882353,25.9249069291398,-26.4680979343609));
#1611=LINE('',#1610,#1609);
#1612=EDGE_CURVE('E1111',#1587,#1605,#1611,.T.);
#1613=ORIENTED_EDGE('',*,*,#1612,.F.);
#1614=EDGE_LOOP('',(#1591,#1597,#1598,#1607,#1613));
#1615=FACE_BOUND('',#1614,.T.);
#1616=ADVANCED_FACE('F2133',(#1615),#905,.T.);
#1617=DIRECTION('',(0.,1.,0.));
#1618=VECTOR('',#1617,1.);
#1619=CARTESIAN_POINT('',(-52.9252123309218,11.6154181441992,-29.4680979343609));
#1620=LINE('',#1619,#1618);
#1621=CARTESIAN_POINT('',(-52.9252123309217,11.6154181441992,-29.4680979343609));
#1622=VERTEX_POINT('',#1621);
#1623=EDGE_CURVE('E1192',#1622,#1387,#1620,.T.);
#1624=ORIENTED_EDGE('',*,*,#1623,.F.);
#1625=CARTESIAN_POINT('',(-98.2264705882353,11.6154181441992,-29.4680979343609));
#1626=VERTEX_POINT('',#1625);
#1627=EDGE_CURVE('E1121',#1626,#1622,#948,.T.);
#1628=ORIENTED_EDGE('',*,*,#1627,.F.);
#1629=DIRECTION('',(0.,1.,0.));
#1630=VECTOR('',#1629,1.);
#1631=CARTESIAN_POINT('',(-98.2264705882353,25.9249069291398,-29.4680979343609));
#1632=LINE('',#1631,#1630);
#1633=CARTESIAN_POINT('',(-98.2264705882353,20.9249069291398,-29.4680979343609));
#1634=VERTEX_POINT('',#1633);
#1635=EDGE_CURVE('E1113',#1626,#1634,#1632,.T.);
#1636=ORIENTED_EDGE('',*,*,#1635,.T.);
#1637=CARTESIAN_POINT('',(-96.2264705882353,20.9249069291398,-29.4680979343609));
#1638=DIRECTION('',(0.,0.,-1.));
#1639=DIRECTION('',(-1.,0.,0.));
#1640=AXIS2_PLACEMENT_3D('',#1637,#1638,#1639);
#1641=CIRCLE('',#1640,2.);
#1642=EDGE_CURVE('E1389',#1393,#1634,#1641,.F.);
#1643=ORIENTED_EDGE('',*,*,#1642,.F.);
#1644=ORIENTED_EDGE('',*,*,#1394,.T.);
#1645=EDGE_LOOP('',(#1624,#1628,#1636,#1643,#1644));
#1646=FACE_BOUND('',#1645,.T.);
#1647=ADVANCED_FACE('F1909',(#1646),#936,.F.);
#1648=CARTESIAN_POINT('',(-98.2264705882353,25.9249069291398,-45.9441176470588));
#1649=DIRECTION('',(1.,0.,0.));
#1650=DIRECTION('',(0.,0.,-1.));
#1651=AXIS2_PLACEMENT_3D('',#1648,#1649,#1650);
#1652=PLANE('',#1651);
#1653=DIRECTION('',(0.,0.,-1.));
#1654=VECTOR('',#1653,1.);
#1655=CARTESIAN_POINT('',(-98.2264705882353,11.6154181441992,-45.9441176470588));
#1656=LINE('',#1655,#1654);
#1657=EDGE_CURVE('E1096',#1587,#1626,#1656,.T.);
#1658=ORIENTED_EDGE('',*,*,#1657,.F.);
#1659=ORIENTED_EDGE('',*,*,#1612,.T.);
#1660=DIRECTION('',(0.,0.,-1.));
#1661=VECTOR('',#1660,1.);
#1662=CARTESIAN_POINT('',(-98.2264705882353,20.9249069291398,-45.9441176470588));
#1663=LINE('',#1662,#1661);
#1664=EDGE_CURVE('E1682',#1572,#1605,#1663,.T.);
#1665=ORIENTED_EDGE('',*,*,#1664,.F.);
#1666=ORIENTED_EDGE('',*,*,#1573,.F.);
#1667=DIRECTION('',(0.,0.,-1.));
#1668=VECTOR('',#1667,1.);
#1669=CARTESIAN_POINT('',(-98.2264705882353,11.6154181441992,-45.9441176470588));
#1670=LINE('',#1669,#1668);
#1671=EDGE_CURVE('E1061',#1525,#1564,#1670,.T.);
#1672=ORIENTED_EDGE('',*,*,#1671,.F.);
#1673=ORIENTED_EDGE('',*,*,#1550,.T.);
#1674=EDGE_CURVE('E1669',#1510,#1543,#1663,.T.);
#1675=ORIENTED_EDGE('',*,*,#1674,.F.);
#1676=ORIENTED_EDGE('',*,*,#1511,.F.);
#1677=DIRECTION('',(0.,0.,-1.));
#1678=VECTOR('',#1677,1.);
#1679=CARTESIAN_POINT('',(-98.2264705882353,11.6154181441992,-45.9441176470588));
#1680=LINE('',#1679,#1678);
#1681=EDGE_CURVE('E1693',#1458,#1502,#1680,.T.);
#1682=ORIENTED_EDGE('',*,*,#1681,.F.);
#1683=ORIENTED_EDGE('',*,*,#1488,.T.);
#1684=CARTESIAN_POINT('',(-98.2264705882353,20.9249069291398,35.9441176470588));
#1685=VERTEX_POINT('',#1684);
#1686=EDGE_CURVE('E1681',#1685,#1481,#1663,.T.);
#1687=ORIENTED_EDGE('',*,*,#1686,.F.);
#1688=DIRECTION('',(0.,1.,0.));
#1689=VECTOR('',#1688,1.);
#1690=CARTESIAN_POINT('',(-98.2264705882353,25.9249069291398,35.9441176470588));
#1691=LINE('',#1690,#1689);
#1692=CARTESIAN_POINT('',(-98.2264705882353,0.,35.9441176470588));
#1693=VERTEX_POINT('',#1692);
#1694=EDGE_CURVE('E1736',#1693,#1685,#1691,.T.);
#1695=ORIENTED_EDGE('',*,*,#1694,.F.);
#1696=DIRECTION('',(0.,0.,1.));
#1697=VECTOR('',#1696,1.);
#1698=CARTESIAN_POINT('',(-98.2264705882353,0.,-45.9441176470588));
#1699=LINE('',#1698,#1697);
#1700=CARTESIAN_POINT('',(-98.2264705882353,0.,-35.9441176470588));
#1701=VERTEX_POINT('',#1700);
#1702=EDGE_CURVE('E1504',#1701,#1693,#1699,.T.);
#1703=ORIENTED_EDGE('',*,*,#1702,.F.);
#1704=DIRECTION('',(0.,1.,0.));
#1705=VECTOR('',#1704,1.);
#1706=CARTESIAN_POINT('',(-98.2264705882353,25.9249069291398,-35.9441176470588));
#1707=LINE('',#1706,#1705);
#1708=CARTESIAN_POINT('',(-98.2264705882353,20.9249069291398,-35.9441176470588));
#1709=VERTEX_POINT('',#1708);
#1710=EDGE_CURVE('E1531',#1709,#1701,#1707,.F.);
#1711=ORIENTED_EDGE('',*,*,#1710,.F.);
#1712=EDGE_CURVE('E1734',#1634,#1709,#1663,.T.);
#1713=ORIENTED_EDGE('',*,*,#1712,.F.);
#1714=ORIENTED_EDGE('',*,*,#1635,.F.);
#1715=EDGE_LOOP('',(#1658,#1659,#1665,#1666,#1672,#1673,#1675,#1676,#1682,#1683,#1687,#1695,
#1703,#1711,#1713,#1714));
#1716=FACE_BOUND('',#1715,.T.);
#1717=ADVANCED_FACE('F1678',(#1716),#1652,.T.);
#1718=CARTESIAN_POINT('',(96.2264705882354,20.9249069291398,45.9441176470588));
#1719=DIRECTION('',(0.,0.,1.));
#1720=DIRECTION('',(1.,0.,0.));
#1721=AXIS2_PLACEMENT_3D('',#1718,#1719,#1720);
#1722=CYLINDRICAL_SURFACE('',#1721,2.);
#1723=CARTESIAN_POINT('',(96.2264705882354,20.9249069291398,-29.4680979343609));
#1724=DIRECTION('',(0.,0.,1.));
#1725=DIRECTION('',(1.,0.,0.));
#1726=AXIS2_PLACEMENT_3D('',#1723,#1724,#1725);
#1727=CIRCLE('',#1726,2.);
#1728=CARTESIAN_POINT('',(96.2264705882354,22.9249069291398,-29.4680979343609));
#1729=VERTEX_POINT('',#1728);
#1730=CARTESIAN_POINT('',(98.2264705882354,20.9249069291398,-29.4680979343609));
#1731=VERTEX_POINT('',#1730);
#1732=EDGE_CURVE('E1108',#1729,#1731,#1727,.F.);
#1733=ORIENTED_EDGE('',*,*,#1732,.F.);
#1734=CARTESIAN_POINT('',(96.2264705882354,22.9249069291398,-35.9441176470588));
#1735=VERTEX_POINT('',#1734);
#1736=EDGE_CURVE('E1488',#1729,#1735,#1035,.F.);
#1737=ORIENTED_EDGE('',*,*,#1736,.T.);
#1738=CARTESIAN_POINT('',(96.2264705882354,20.9249069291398,-35.9441176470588));
#1739=DIRECTION('',(0.,0.,1.));
#1740=DIRECTION('',(1.,0.,0.));
#1741=AXIS2_PLACEMENT_3D('',#1738,#1739,#1740);
#1742=CIRCLE('',#1741,2.);
#1743=CARTESIAN_POINT('',(98.2264705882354,20.9249069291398,-35.9441176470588));
#1744=VERTEX_POINT('',#1743);
#1745=EDGE_CURVE('E1493',#1735,#1744,#1742,.F.);
#1746=ORIENTED_EDGE('',*,*,#1745,.T.);
#1747=DIRECTION('',(0.,0.,1.));
#1748=VECTOR('',#1747,1.);
#1749=CARTESIAN_POINT('',(98.2264705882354,20.9249069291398,-45.9441176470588));
#1750=LINE('',#1749,#1748);
#1751=EDGE_CURVE('E1762',#1744,#1731,#1750,.T.);
#1752=ORIENTED_EDGE('',*,*,#1751,.T.);
#1753=EDGE_LOOP('',(#1733,#1737,#1746,#1752));
#1754=FACE_BOUND('',#1753,.T.);
#1755=ADVANCED_FACE('F1852',(#1754),#1722,.F.);
#1756=CARTESIAN_POINT('',(52.9252123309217,22.9249069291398,-1.5));
#1757=VERTEX_POINT('',#1756);
#1758=CARTESIAN_POINT('',(96.2264705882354,22.9249069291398,-1.5));
#1759=VERTEX_POINT('',#1758);
#1760=EDGE_CURVE('E1410',#1757,#1759,#643,.T.);
#1761=ORIENTED_EDGE('',*,*,#1760,.F.);
#1762=DIRECTION('',(0.,0.,-1.));
#1763=VECTOR('',#1762,1.);
#1764=CARTESIAN_POINT('',(52.9252123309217,22.9249069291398,45.9441176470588));
#1765=LINE('',#1764,#1763);
#1766=CARTESIAN_POINT('',(52.9252123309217,22.9249069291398,-26.4680979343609));
#1767=VERTEX_POINT('',#1766);
#1768=EDGE_CURVE('E1250',#1757,#1767,#1765,.T.);
#1769=ORIENTED_EDGE('',*,*,#1768,.T.);
#1770=CARTESIAN_POINT('',(96.2264705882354,22.9249069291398,-26.4680979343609));
#1771=VERTEX_POINT('',#1770);
#1772=EDGE_CURVE('E1426',#1767,#1771,#659,.T.);
#1773=ORIENTED_EDGE('',*,*,#1772,.T.);
#1774=EDGE_CURVE('E1857',#1759,#1771,#1035,.F.);
#1775=ORIENTED_EDGE('',*,*,#1774,.F.);
#1776=EDGE_LOOP('',(#1761,#1769,#1773,#1775));
#1777=FACE_BOUND('',#1776,.T.);
#1778=ADVANCED_FACE('F2261',(#1777),#629,.F.);
#1779=CARTESIAN_POINT('',(-96.2264705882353,20.9249069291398,45.9441176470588));
#1780=DIRECTION('',(0.,0.,-1.));
#1781=DIRECTION('',(-1.,0.,0.));
#1782=AXIS2_PLACEMENT_3D('',#1779,#1780,#1781);
#1783=CYLINDRICAL_SURFACE('',#1782,2.);
#1784=ORIENTED_EDGE('',*,*,#1606,.F.);
#1785=ORIENTED_EDGE('',*,*,#1330,.T.);
#1786=ORIENTED_EDGE('',*,*,#1580,.T.);
#1787=ORIENTED_EDGE('',*,*,#1664,.T.);
#1788=EDGE_LOOP('',(#1784,#1785,#1786,#1787));
#1789=FACE_BOUND('',#1788,.T.);
#1790=ADVANCED_FACE('F2120',(#1789),#1783,.F.);
#1791=ORIENTED_EDGE('',*,*,#1774,.T.);
#1792=CARTESIAN_POINT('',(96.2264705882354,20.9249069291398,-26.4680979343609));
#1793=DIRECTION('',(0.,0.,1.));
#1794=DIRECTION('',(1.,0.,0.));
#1795=AXIS2_PLACEMENT_3D('',#1792,#1793,#1794);
#1796=CIRCLE('',#1795,2.);
#1797=CARTESIAN_POINT('',(98.2264705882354,20.9249069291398,-26.4680979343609));
#1798=VERTEX_POINT('',#1797);
#1799=EDGE_CURVE('E1103',#1771,#1798,#1796,.F.);
#1800=ORIENTED_EDGE('',*,*,#1799,.T.);
#1801=CARTESIAN_POINT('',(98.2264705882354,20.9249069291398,-1.5));
#1802=VERTEX_POINT('',#1801);
#1803=EDGE_CURVE('E1764',#1798,#1802,#1750,.T.);
#1804=ORIENTED_EDGE('',*,*,#1803,.T.);
#1805=CARTESIAN_POINT('',(96.2264705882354,20.9249069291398,-1.5));
#1806=DIRECTION('',(0.,0.,1.));
#1807=DIRECTION('',(1.,0.,0.));
#1808=AXIS2_PLACEMENT_3D('',#1805,#1806,#1807);
#1809=CIRCLE('',#1808,2.);
#1810=EDGE_CURVE('E1078',#1759,#1802,#1809,.F.);
#1811=ORIENTED_EDGE('',*,*,#1810,.F.);
#1812=EDGE_LOOP('',(#1791,#1800,#1804,#1811));
#1813=FACE_BOUND('',#1812,.T.);
#1814=ADVANCED_FACE('F2082',(#1813),#1722,.F.);
#1815=CARTESIAN_POINT('',(52.9252123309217,22.9249069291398,26.4680979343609));
#1816=VERTEX_POINT('',#1815);
#1817=CARTESIAN_POINT('',(96.2264705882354,22.9249069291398,26.4680979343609));
#1818=VERTEX_POINT('',#1817);
#1819=EDGE_CURVE('E1655',#1816,#1818,#678,.T.);
#1820=ORIENTED_EDGE('',*,*,#1819,.F.);
#1821=DIRECTION('',(0.,0.,-1.));
#1822=VECTOR('',#1821,1.);
#1823=CARTESIAN_POINT('',(52.9252123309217,22.9249069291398,45.9441176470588));
#1824=LINE('',#1823,#1822);
#1825=CARTESIAN_POINT('',(52.9252123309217,22.9249069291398,1.5));
#1826=VERTEX_POINT('',#1825);
#1827=EDGE_CURVE('E1242',#1816,#1826,#1824,.T.);
#1828=ORIENTED_EDGE('',*,*,#1827,.T.);
#1829=CARTESIAN_POINT('',(96.2264705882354,22.9249069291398,1.5));
#1830=VERTEX_POINT('',#1829);
#1831=EDGE_CURVE('E1404',#1826,#1830,#694,.T.);
#1832=ORIENTED_EDGE('',*,*,#1831,.T.);
#1833=EDGE_CURVE('E1486',#1818,#1830,#1035,.F.);
#1834=ORIENTED_EDGE('',*,*,#1833,.F.);
#1835=EDGE_LOOP('',(#1820,#1828,#1832,#1834));
#1836=FACE_BOUND('',#1835,.T.);
#1837=ADVANCED_FACE('F2255',(#1836),#629,.F.);
#1838=ORIENTED_EDGE('',*,*,#1544,.F.);
#1839=ORIENTED_EDGE('',*,*,#1353,.T.);
#1840=ORIENTED_EDGE('',*,*,#1518,.T.);
#1841=ORIENTED_EDGE('',*,*,#1674,.T.);
#1842=EDGE_LOOP('',(#1838,#1839,#1840,#1841));
#1843=FACE_BOUND('',#1842,.T.);
#1844=ADVANCED_FACE('F1668',(#1843),#1783,.F.);
#1845=DIRECTION('',(0.,0.,-1.));
#1846=VECTOR('',#1845,1.);
#1847=CARTESIAN_POINT('',(-52.9252123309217,22.9249069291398,45.9441176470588));
#1848=LINE('',#1847,#1846);
#1849=CARTESIAN_POINT('',(-52.9252123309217,22.9249069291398,40.9441176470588));
#1850=VERTEX_POINT('',#1849);
#1851=EDGE_CURVE('E1171',#1850,#1468,#1848,.T.);
#1852=ORIENTED_EDGE('',*,*,#1851,.F.);
#1853=CARTESIAN_POINT('',(-91.2264705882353,22.9249069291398,40.9441176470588));
#1854=VERTEX_POINT('',#1853);
#1855=EDGE_CURVE('E1784',#1854,#1850,#966,.T.);
#1856=ORIENTED_EDGE('',*,*,#1855,.F.);
#1857=CARTESIAN_POINT('',(-91.2264705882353,22.9249069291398,35.9441176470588));
#1858=DIRECTION('',(0.,1.,0.));
#1859=DIRECTION('',(0.,0.,1.));
#1860=AXIS2_PLACEMENT_3D('',#1857,#1858,#1859);
#1861=CIRCLE('',#1860,5.);
#1862=CARTESIAN_POINT('',(-96.2264705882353,22.9249069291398,35.9441176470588));
#1863=VERTEX_POINT('',#1862);
#1864=EDGE_CURVE('E1517',#1854,#1863,#1861,.F.);
#1865=ORIENTED_EDGE('',*,*,#1864,.T.);
#1866=EDGE_CURVE('E1790',#1472,#1863,#1327,.T.);
#1867=ORIENTED_EDGE('',*,*,#1866,.F.);
#1868=ORIENTED_EDGE('',*,*,#1473,.T.);
#1869=EDGE_LOOP('',(#1852,#1856,#1865,#1867,#1868));
#1870=FACE_BOUND('',#1869,.T.);
#1871=ADVANCED_FACE('F2167',(#1870),#629,.F.);
#1872=ORIENTED_EDGE('',*,*,#1833,.T.);
#1873=CARTESIAN_POINT('',(96.2264705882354,20.9249069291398,1.5));
#1874=DIRECTION('',(0.,0.,1.));
#1875=DIRECTION('',(1.,0.,0.));
#1876=AXIS2_PLACEMENT_3D('',#1873,#1874,#1875);
#1877=CIRCLE('',#1876,2.);
#1878=CARTESIAN_POINT('',(98.2264705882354,20.9249069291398,1.5));
#1879=VERTEX_POINT('',#1878);
#1880=EDGE_CURVE('E1071',#1830,#1879,#1877,.F.);
#1881=ORIENTED_EDGE('',*,*,#1880,.T.);
#1882=CARTESIAN_POINT('',(98.2264705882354,20.9249069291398,26.4680979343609));
#1883=VERTEX_POINT('',#1882);
#1884=EDGE_CURVE('E1386',#1879,#1883,#1750,.T.);
#1885=ORIENTED_EDGE('',*,*,#1884,.T.);
#1886=CARTESIAN_POINT('',(96.2264705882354,20.9249069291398,26.4680979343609));
#1887=DIRECTION('',(0.,0.,1.));
#1888=DIRECTION('',(1.,0.,0.));
#1889=AXIS2_PLACEMENT_3D('',#1886,#1887,#1888);
#1890=CIRCLE('',#1889,2.);
#1891=EDGE_CURVE('E1656',#1818,#1883,#1890,.F.);
#1892=ORIENTED_EDGE('',*,*,#1891,.F.);
#1893=EDGE_LOOP('',(#1872,#1881,#1885,#1892));
#1894=FACE_BOUND('',#1893,.T.);
#1895=ADVANCED_FACE('F1867',(#1894),#1722,.F.);
#1896=ORIENTED_EDGE('',*,*,#1482,.F.);
#1897=ORIENTED_EDGE('',*,*,#1866,.T.);
#1898=CARTESIAN_POINT('',(-96.2264705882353,20.9249069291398,35.9441176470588));
#1899=DIRECTION('',(0.,0.,-1.));
#1900=DIRECTION('',(-1.,0.,0.));
#1901=AXIS2_PLACEMENT_3D('',#1898,#1899,#1900);
#1902=CIRCLE('',#1901,2.);
#1903=EDGE_CURVE('E1492',#1685,#1863,#1902,.T.);
#1904=ORIENTED_EDGE('',*,*,#1903,.F.);
#1905=ORIENTED_EDGE('',*,*,#1686,.T.);
#1906=EDGE_LOOP('',(#1896,#1897,#1904,#1905));
#1907=FACE_BOUND('',#1906,.T.);
#1908=ADVANCED_FACE('F2005',(#1907),#1783,.F.);
#1909=CARTESIAN_POINT('',(-101.226470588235,0.,45.9441176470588));
#1910=DIRECTION('',(0.,1.,0.));
#1911=DIRECTION('',(0.,0.,1.));
#1912=AXIS2_PLACEMENT_3D('',#1909,#1910,#1911);
#1913=PLANE('',#1912);
#1914=DIRECTION('',(-1.,0.,0.));
#1915=VECTOR('',#1914,1.);
#1916=CARTESIAN_POINT('',(-101.226470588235,0.,-45.9441176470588));
#1917=LINE('',#1916,#1915);
#1918=CARTESIAN_POINT('',(-71.5742721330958,0.,-45.9441176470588));
#1919=VERTEX_POINT('',#1918);
#1920=CARTESIAN_POINT('',(-91.2264705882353,0.,-45.9441176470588));
#1921=VERTEX_POINT('',#1920);
#1922=EDGE_CURVE('E1577',#1919,#1921,#1917,.T.);
#1923=ORIENTED_EDGE('',*,*,#1922,.F.);
#1924=DIRECTION('',(0.,0.,1.));
#1925=VECTOR('',#1924,1.);
#1926=CARTESIAN_POINT('',(-71.5742721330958,0.,-45.9441176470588));
#1927=LINE('',#1926,#1925);
#1928=CARTESIAN_POINT('',(-71.5742721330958,0.,-42.9441176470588));
#1929=VERTEX_POINT('',#1928);
#1930=EDGE_CURVE('E1725',#1919,#1929,#1927,.T.);
#1931=ORIENTED_EDGE('',*,*,#1930,.T.);
#1932=DIRECTION('',(-1.,0.,0.));
#1933=VECTOR('',#1932,1.);
#1934=CARTESIAN_POINT('',(-101.226470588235,0.,-42.9441176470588));
#1935=LINE('',#1934,#1933);
#1936=CARTESIAN_POINT('',(-91.2264705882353,0.,-42.9441176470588));
#1937=VERTEX_POINT('',#1936);
#1938=EDGE_CURVE('E1518',#1929,#1937,#1935,.T.);
#1939=ORIENTED_EDGE('',*,*,#1938,.T.);
#1940=CARTESIAN_POINT('',(-91.2264705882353,0.,-35.9441176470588));
#1941=DIRECTION('',(0.,1.,0.));
#1942=DIRECTION('',(0.,0.,1.));
#1943=AXIS2_PLACEMENT_3D('',#1940,#1941,#1942);
#1944=CIRCLE('',#1943,7.);
#1945=EDGE_CURVE('E1509',#1701,#1937,#1944,.F.);
#1946=ORIENTED_EDGE('',*,*,#1945,.F.);
#1947=ORIENTED_EDGE('',*,*,#1702,.T.);
#1948=CARTESIAN_POINT('',(-91.2264705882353,0.,35.9441176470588));
#1949=DIRECTION('',(0.,1.,0.));
#1950=DIRECTION('',(0.,0.,1.));
#1951=AXIS2_PLACEMENT_3D('',#1948,#1949,#1950);
#1952=CIRCLE('',#1951,7.);
#1953=EDGE_CURVE('E1527',#573,#1693,#1952,.F.);
#1954=ORIENTED_EDGE('',*,*,#1953,.F.);
#1955=ORIENTED_EDGE('',*,*,#574,.T.);
#1956=CARTESIAN_POINT('',(-71.5742721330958,0.,45.9441176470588));
#1957=VERTEX_POINT('',#1956);
#1958=EDGE_CURVE('E1712',#569,#1957,#1927,.T.);
#1959=ORIENTED_EDGE('',*,*,#1958,.T.);
#1960=DIRECTION('',(1.,0.,0.));
#1961=VECTOR('',#1960,1.);
#1962=CARTESIAN_POINT('',(-101.226470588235,0.,45.9441176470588));
#1963=LINE('',#1962,#1961);
#1964=CARTESIAN_POINT('',(-91.2264705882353,0.,45.9441176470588));
#1965=VERTEX_POINT('',#1964);
#1966=EDGE_CURVE('E1571',#1965,#1957,#1963,.T.);
#1967=ORIENTED_EDGE('',*,*,#1966,.F.);
#1968=CARTESIAN_POINT('',(-91.2264705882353,0.,35.9441176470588));
#1969=DIRECTION('',(0.,1.,0.));
#1970=DIRECTION('',(0.,0.,1.));
#1971=AXIS2_PLACEMENT_3D('',#1968,#1969,#1970);
#1972=CIRCLE('',#1971,10.);
#1973=CARTESIAN_POINT('',(-101.226470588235,0.,35.9441176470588));
#1974=VERTEX_POINT('',#1973);
#1975=EDGE_CURVE('E1625',#1965,#1974,#1972,.F.);
#1976=ORIENTED_EDGE('',*,*,#1975,.T.);
#1977=DIRECTION('',(0.,0.,1.));
#1978=VECTOR('',#1977,1.);
#1979=CARTESIAN_POINT('',(-101.226470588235,0.,-45.9441176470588));
#1980=LINE('',#1979,#1978);
#1981=CARTESIAN_POINT('',(-101.226470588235,0.,-35.9441176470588));
#1982=VERTEX_POINT('',#1981);
#1983=EDGE_CURVE('E1567',#1982,#1974,#1980,.T.);
#1984=ORIENTED_EDGE('',*,*,#1983,.F.);
#1985=CARTESIAN_POINT('',(-91.2264705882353,0.,-35.9441176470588));
#1986=DIRECTION('',(0.,1.,0.));
#1987=DIRECTION('',(0.,0.,1.));
#1988=AXIS2_PLACEMENT_3D('',#1985,#1986,#1987);
#1989=CIRCLE('',#1988,10.);
#1990=EDGE_CURVE('E1632',#1982,#1921,#1989,.F.);
#1991=ORIENTED_EDGE('',*,*,#1990,.T.);
#1992=EDGE_LOOP('',(#1923,#1931,#1939,#1946,#1947,#1954,#1955,#1959,#1967,#1976,#1984,#1991));
#1993=FACE_BOUND('',#1992,.T.);
#1994=ADVANCED_FACE('F1924',(#1993),#1913,.F.);
#1995=CARTESIAN_POINT('',(-101.226470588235,25.9249069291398,-45.9441176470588));
#1996=DIRECTION('',(1.,0.,0.));
#1997=DIRECTION('',(0.,0.,-1.));
#1998=AXIS2_PLACEMENT_3D('',#1995,#1996,#1997);
#1999=PLANE('',#1998);
#2000=DIRECTION('',(0.,0.,1.));
#2001=VECTOR('',#2000,1.);
#2002=CARTESIAN_POINT('',(-101.226470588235,20.9249069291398,-45.9441176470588));
#2003=LINE('',#2002,#2001);
#2004=CARTESIAN_POINT('',(-101.226470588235,20.9249069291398,35.9441176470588));
#2005=VERTEX_POINT('',#2004);
#2006=CARTESIAN_POINT('',(-101.226470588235,20.9249069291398,-35.9441176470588));
#2007=VERTEX_POINT('',#2006);
#2008=EDGE_CURVE('E1621',#2005,#2007,#2003,.F.);
#2009=ORIENTED_EDGE('',*,*,#2008,.T.);
#2010=DIRECTION('',(0.,-1.,0.));
#2011=VECTOR('',#2010,1.);
#2012=CARTESIAN_POINT('',(-101.226470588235,25.9249069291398,-35.9441176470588));
#2013=LINE('',#2012,#2011);
#2014=EDGE_CURVE('E1623',#2007,#1982,#2013,.T.);
#2015=ORIENTED_EDGE('',*,*,#2014,.T.);
#2016=ORIENTED_EDGE('',*,*,#1983,.T.);
#2017=DIRECTION('',(0.,-1.,0.));
#2018=VECTOR('',#2017,1.);
#2019=CARTESIAN_POINT('',(-101.226470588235,25.9249069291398,35.9441176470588));
#2020=LINE('',#2019,#2018);
#2021=EDGE_CURVE('E1619',#1974,#2005,#2020,.F.);
#2022=ORIENTED_EDGE('',*,*,#2021,.T.);
#2023=EDGE_LOOP('',(#2009,#2015,#2016,#2022));
#2024=FACE_BOUND('',#2023,.T.);
#2025=ADVANCED_FACE('F367',(#2024),#1999,.F.);
#2026=CARTESIAN_POINT('',(-101.226470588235,25.9249069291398,45.9441176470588));
#2027=DIRECTION('',(0.,0.,-1.));
#2028=DIRECTION('',(-1.,0.,0.));
#2029=AXIS2_PLACEMENT_3D('',#2026,#2027,#2028);
#2030=PLANE('',#2029);
#2031=DIRECTION('',(1.,0.,0.));
#2032=VECTOR('',#2031,1.);
#2033=CARTESIAN_POINT('',(-101.226470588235,20.9249069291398,45.9441176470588));
#2034=LINE('',#2033,#2032);
#2035=CARTESIAN_POINT('',(91.2264705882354,20.9249069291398,45.9441176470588));
#2036=VERTEX_POINT('',#2035);
#2037=CARTESIAN_POINT('',(-91.2264705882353,20.9249069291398,45.9441176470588));
#2038=VERTEX_POINT('',#2037);
#2039=EDGE_CURVE('E1615',#2036,#2038,#2034,.F.);
#2040=ORIENTED_EDGE('',*,*,#2039,.T.);
#2041=DIRECTION('',(0.,-1.,0.));
#2042=VECTOR('',#2041,1.);
#2043=CARTESIAN_POINT('',(-91.2264705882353,25.9249069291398,45.9441176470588));
#2044=LINE('',#2043,#2042);
#2045=EDGE_CURVE('E1613',#2038,#1965,#2044,.T.);
#2046=ORIENTED_EDGE('',*,*,#2045,.T.);
#2047=ORIENTED_EDGE('',*,*,#1966,.T.);
#2048=DIRECTION('',(0.,-1.,0.));
#2049=VECTOR('',#2048,1.);
#2050=CARTESIAN_POINT('',(-71.5742721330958,0.,45.9441176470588));
#2051=LINE('',#2050,#2049);
#2052=CARTESIAN_POINT('',(-71.5742721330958,6.34634427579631,45.9441176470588));
#2053=VERTEX_POINT('',#2052);
#2054=EDGE_CURVE('E1695',#2053,#1957,#2051,.T.);
#2055=ORIENTED_EDGE('',*,*,#2054,.F.);
#2056=DIRECTION('',(-1.,0.,0.));
#2057=VECTOR('',#2056,1.);
#2058=CARTESIAN_POINT('',(-71.5742721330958,6.34634427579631,45.9441176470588));
#2059=LINE('',#2058,#2057);
#2060=CARTESIAN_POINT('',(71.5742721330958,6.34634427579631,45.9441176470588));
#2061=VERTEX_POINT('',#2060);
#2062=EDGE_CURVE('E1700',#2061,#2053,#2059,.T.);
#2063=ORIENTED_EDGE('',*,*,#2062,.F.);
#2064=DIRECTION('',(0.,1.,0.));
#2065=VECTOR('',#2064,1.);
#2066=CARTESIAN_POINT('',(71.5742721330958,0.,45.9441176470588));
#2067=LINE('',#2066,#2065);
#2068=CARTESIAN_POINT('',(71.5742721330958,0.,45.9441176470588));
#2069=VERTEX_POINT('',#2068);
#2070=EDGE_CURVE('E1697',#2069,#2061,#2067,.T.);
#2071=ORIENTED_EDGE('',*,*,#2070,.F.);
#2072=CARTESIAN_POINT('',(91.2264705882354,0.,45.9441176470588));
#2073=VERTEX_POINT('',#2072);
#2074=EDGE_CURVE('E1570',#2069,#2073,#1963,.T.);
#2075=ORIENTED_EDGE('',*,*,#2074,.T.);
#2076=DIRECTION('',(0.,-1.,0.));
#2077=VECTOR('',#2076,1.);
#2078=CARTESIAN_POINT('',(91.2264705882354,25.9249069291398,45.9441176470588));
#2079=LINE('',#2078,#2077);
#2080=EDGE_CURVE('E1617',#2073,#2036,#2079,.F.);
#2081=ORIENTED_EDGE('',*,*,#2080,.T.);
#2082=EDGE_LOOP('',(#2040,#2046,#2047,#2055,#2063,#2071,#2075,#2081));
#2083=FACE_BOUND('',#2082,.T.);
#2084=ADVANCED_FACE('F2028',(#2083),#2030,.F.);
#2085=CARTESIAN_POINT('',(101.226470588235,25.9249069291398,-45.9441176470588));
#2086=DIRECTION('',(-1.,0.,0.));
#2087=DIRECTION('',(0.,0.,1.));
#2088=AXIS2_PLACEMENT_3D('',#2085,#2086,#2087);
#2089=PLANE('',#2088);
#2090=DIRECTION('',(0.,0.,-1.));
#2091=VECTOR('',#2090,1.);
#2092=CARTESIAN_POINT('',(101.226470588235,20.9249069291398,45.9441176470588));
#2093=LINE('',#2092,#2091);
#2094=CARTESIAN_POINT('',(101.226470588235,20.9249069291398,-35.9441176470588));
#2095=VERTEX_POINT('',#2094);
#2096=CARTESIAN_POINT('',(101.226470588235,20.9249069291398,35.9441176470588));
#2097=VERTEX_POINT('',#2096);
#2098=EDGE_CURVE('E1609',#2095,#2097,#2093,.F.);
#2099=ORIENTED_EDGE('',*,*,#2098,.T.);
#2100=DIRECTION('',(0.,-1.,0.));
#2101=VECTOR('',#2100,1.);
#2102=CARTESIAN_POINT('',(101.226470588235,25.9249069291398,35.9441176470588));
#2103=LINE('',#2102,#2101);
#2104=CARTESIAN_POINT('',(101.226470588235,0.,35.9441176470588));
#2105=VERTEX_POINT('',#2104);
#2106=EDGE_CURVE('E1607',#2097,#2105,#2103,.T.);
#2107=ORIENTED_EDGE('',*,*,#2106,.T.);
#2108=DIRECTION('',(0.,0.,-1.));
#2109=VECTOR('',#2108,1.);
#2110=CARTESIAN_POINT('',(101.226470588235,0.,-45.9441176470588));
#2111=LINE('',#2110,#2109);
#2112=CARTESIAN_POINT('',(101.226470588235,0.,-35.9441176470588));
#2113=VERTEX_POINT('',#2112);
#2114=EDGE_CURVE('E1574',#2105,#2113,#2111,.T.);
#2115=ORIENTED_EDGE('',*,*,#2114,.T.);
#2116=DIRECTION('',(0.,-1.,0.));
#2117=VECTOR('',#2116,1.);
#2118=CARTESIAN_POINT('',(101.226470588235,25.9249069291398,-35.9441176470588));
#2119=LINE('',#2118,#2117);
#2120=EDGE_CURVE('E1611',#2113,#2095,#2119,.F.);
#2121=ORIENTED_EDGE('',*,*,#2120,.T.);
#2122=EDGE_LOOP('',(#2099,#2107,#2115,#2121));
#2123=FACE_BOUND('',#2122,.T.);
#2124=ADVANCED_FACE('F2059',(#2123),#2089,.F.);
#2125=CARTESIAN_POINT('',(-101.226470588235,25.9249069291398,-45.9441176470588));
#2126=DIRECTION('',(0.,0.,1.));
#2127=DIRECTION('',(1.,0.,0.));
#2128=AXIS2_PLACEMENT_3D('',#2125,#2126,#2127);
#2129=PLANE('',#2128);
#2130=DIRECTION('',(-1.,0.,0.));
#2131=VECTOR('',#2130,1.);
#2132=CARTESIAN_POINT('',(101.226470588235,20.9249069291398,-45.9441176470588));
#2133=LINE('',#2132,#2131);
#2134=CARTESIAN_POINT('',(-91.2264705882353,20.9249069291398,-45.9441176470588));
#2135=VERTEX_POINT('',#2134);
#2136=CARTESIAN_POINT('',(91.2264705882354,20.9249069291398,-45.9441176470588));
#2137=VERTEX_POINT('',#2136);
#2138=EDGE_CURVE('E1603',#2135,#2137,#2133,.F.);
#2139=ORIENTED_EDGE('',*,*,#2138,.T.);
#2140=DIRECTION('',(0.,-1.,0.));
#2141=VECTOR('',#2140,1.);
#2142=CARTESIAN_POINT('',(91.2264705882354,25.9249069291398,-45.9441176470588));
#2143=LINE('',#2142,#2141);
#2144=CARTESIAN_POINT('',(91.2264705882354,0.,-45.9441176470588));
#2145=VERTEX_POINT('',#2144);
#2146=EDGE_CURVE('E1601',#2137,#2145,#2143,.T.);
#2147=ORIENTED_EDGE('',*,*,#2146,.T.);
#2148=CARTESIAN_POINT('',(71.5742721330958,0.,-45.9441176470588));
#2149=VERTEX_POINT('',#2148);
#2150=EDGE_CURVE('E1578',#2145,#2149,#1917,.T.);
#2151=ORIENTED_EDGE('',*,*,#2150,.T.);
#2152=DIRECTION('',(0.,1.,0.));
#2153=VECTOR('',#2152,1.);
#2154=CARTESIAN_POINT('',(71.5742721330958,0.,-45.9441176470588));
#2155=LINE('',#2154,#2153);
#2156=CARTESIAN_POINT('',(71.5742721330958,6.34634427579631,-45.9441176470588));
#2157=VERTEX_POINT('',#2156);
#2158=EDGE_CURVE('E1706',#2149,#2157,#2155,.T.);
#2159=ORIENTED_EDGE('',*,*,#2158,.T.);
#2160=DIRECTION('',(-1.,0.,0.));
#2161=VECTOR('',#2160,1.);
#2162=CARTESIAN_POINT('',(-71.5742721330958,6.34634427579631,-45.9441176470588));
#2163=LINE('',#2162,#2161);
#2164=CARTESIAN_POINT('',(-71.5742721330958,6.34634427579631,-45.9441176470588));
#2165=VERTEX_POINT('',#2164);
#2166=EDGE_CURVE('E1709',#2157,#2165,#2163,.T.);
#2167=ORIENTED_EDGE('',*,*,#2166,.T.);
#2168=DIRECTION('',(0.,-1.,0.));
#2169=VECTOR('',#2168,1.);
#2170=CARTESIAN_POINT('',(-71.5742721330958,0.,-45.9441176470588));
#2171=LINE('',#2170,#2169);
#2172=EDGE_CURVE('E1703',#2165,#1919,#2171,.T.);
#2173=ORIENTED_EDGE('',*,*,#2172,.T.);
#2174=ORIENTED_EDGE('',*,*,#1922,.T.);
#2175=DIRECTION('',(0.,-1.,0.));
#2176=VECTOR('',#2175,1.);
#2177=CARTESIAN_POINT('',(-91.2264705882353,25.9249069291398,-45.9441176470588));
#2178=LINE('',#2177,#2176);
#2179=EDGE_CURVE('E1605',#1921,#2135,#2178,.F.);
#2180=ORIENTED_EDGE('',*,*,#2179,.T.);
#2181=EDGE_LOOP('',(#2139,#2147,#2151,#2159,#2167,#2173,#2174,#2180));
#2182=FACE_BOUND('',#2181,.T.);
#2183=ADVANCED_FACE('F2049',(#2182),#2129,.F.);
#2184=CARTESIAN_POINT('',(-101.226470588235,25.9249069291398,45.9441176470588));
#2185=DIRECTION('',(0.,1.,0.));
#2186=DIRECTION('',(0.,0.,1.));
#2187=AXIS2_PLACEMENT_3D('',#2184,#2185,#2186);
#2188=PLANE('',#2187);
#2189=DIRECTION('',(1.,0.,0.));
#2190=VECTOR('',#2189,1.);
#2191=CARTESIAN_POINT('',(101.226470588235,25.9249069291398,40.9441176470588));
#2192=LINE('',#2191,#2190);
#2193=CARTESIAN_POINT('',(-91.2264705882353,25.9249069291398,40.9441176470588));
#2194=VERTEX_POINT('',#2193);
#2195=CARTESIAN_POINT('',(91.2264705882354,25.9249069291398,40.9441176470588));
#2196=VERTEX_POINT('',#2195);
#2197=EDGE_CURVE('E1586',#2194,#2196,#2192,.T.);
#2198=ORIENTED_EDGE('',*,*,#2197,.T.);
#2199=CARTESIAN_POINT('',(91.2264705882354,25.9249069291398,35.9441176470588));
#2200=DIRECTION('',(0.,1.,0.));
#2201=DIRECTION('',(0.,0.,1.));
#2202=AXIS2_PLACEMENT_3D('',#2199,#2200,#2201);
#2203=CIRCLE('',#2202,5.);
#2204=CARTESIAN_POINT('',(96.2264705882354,25.9249069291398,35.9441176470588));
#2205=VERTEX_POINT('',#2204);
#2206=EDGE_CURVE('E1593',#2205,#2196,#2203,.F.);
#2207=ORIENTED_EDGE('',*,*,#2206,.F.);
#2208=DIRECTION('',(0.,0.,-1.));
#2209=VECTOR('',#2208,1.);
#2210=CARTESIAN_POINT('',(96.2264705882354,25.9249069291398,-45.9441176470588));
#2211=LINE('',#2210,#2209);
#2212=CARTESIAN_POINT('',(96.2264705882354,25.9249069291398,-35.9441176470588));
#2213=VERTEX_POINT('',#2212);
#2214=EDGE_CURVE('E1599',#2205,#2213,#2211,.T.);
#2215=ORIENTED_EDGE('',*,*,#2214,.T.);
#2216=CARTESIAN_POINT('',(91.2264705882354,25.9249069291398,-35.9441176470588));
#2217=DIRECTION('',(0.,1.,0.));
#2218=DIRECTION('',(0.,0.,1.));
#2219=AXIS2_PLACEMENT_3D('',#2216,#2217,#2218);
#2220=CIRCLE('',#2219,5.);
#2221=CARTESIAN_POINT('',(91.2264705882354,25.9249069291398,-40.9441176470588));
#2222=VERTEX_POINT('',#2221);
#2223=EDGE_CURVE('E1596',#2222,#2213,#2220,.F.);
#2224=ORIENTED_EDGE('',*,*,#2223,.F.);
#2225=DIRECTION('',(-1.,0.,0.));
#2226=VECTOR('',#2225,1.);
#2227=CARTESIAN_POINT('',(-101.226470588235,25.9249069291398,-40.9441176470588));
#2228=LINE('',#2227,#2226);
#2229=CARTESIAN_POINT('',(-91.2264705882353,25.9249069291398,-40.9441176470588));
#2230=VERTEX_POINT('',#2229);
#2231=EDGE_CURVE('E1591',#2222,#2230,#2228,.T.);
#2232=ORIENTED_EDGE('',*,*,#2231,.T.);
#2233=CARTESIAN_POINT('',(-91.2264705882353,25.9249069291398,-35.9441176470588));
#2234=DIRECTION('',(0.,1.,0.));
#2235=DIRECTION('',(0.,0.,1.));
#2236=AXIS2_PLACEMENT_3D('',#2233,#2234,#2235);
#2237=CIRCLE('',#2236,5.);
#2238=CARTESIAN_POINT('',(-96.2264705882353,25.9249069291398,-35.9441176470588));
#2239=VERTEX_POINT('',#2238);
#2240=EDGE_CURVE('E1588',#2239,#2230,#2237,.F.);
#2241=ORIENTED_EDGE('',*,*,#2240,.F.);
#2242=DIRECTION('',(0.,0.,1.));
#2243=VECTOR('',#2242,1.);
#2244=CARTESIAN_POINT('',(-96.2264705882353,25.9249069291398,45.9441176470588));
#2245=LINE('',#2244,#2243);
#2246=CARTESIAN_POINT('',(-96.2264705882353,25.9249069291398,35.9441176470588));
#2247=VERTEX_POINT('',#2246);
#2248=EDGE_CURVE('E1584',#2239,#2247,#2245,.T.);
#2249=ORIENTED_EDGE('',*,*,#2248,.T.);
#2250=CARTESIAN_POINT('',(-91.2264705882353,25.9249069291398,35.9441176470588));
#2251=DIRECTION('',(0.,1.,0.));
#2252=DIRECTION('',(0.,0.,1.));
#2253=AXIS2_PLACEMENT_3D('',#2250,#2251,#2252);
#2254=CIRCLE('',#2253,5.);
#2255=EDGE_CURVE('E1581',#2194,#2247,#2254,.F.);
#2256=ORIENTED_EDGE('',*,*,#2255,.F.);
#2257=EDGE_LOOP('',(#2198,#2207,#2215,#2224,#2232,#2241,#2249,#2256));
#2258=FACE_BOUND('',#2257,.T.);
#2259=ADVANCED_FACE('F2234',(#2258),#2188,.T.);
#2260=ORIENTED_EDGE('',*,*,#2074,.F.);
#2261=DIRECTION('',(0.,0.,1.));
#2262=VECTOR('',#2261,1.);
#2263=CARTESIAN_POINT('',(71.5742721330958,0.,-45.9441176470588));
#2264=LINE('',#2263,#2262);
#2265=EDGE_CURVE('E1724',#545,#2069,#2264,.T.);
#2266=ORIENTED_EDGE('',*,*,#2265,.F.);
#2267=ORIENTED_EDGE('',*,*,#546,.T.);
#2268=CARTESIAN_POINT('',(91.2264705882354,0.,35.9441176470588));
#2269=DIRECTION('',(0.,1.,0.));
#2270=DIRECTION('',(0.,0.,1.));
#2271=AXIS2_PLACEMENT_3D('',#2268,#2269,#2270);
#2272=CIRCLE('',#2271,7.);
#2273=CARTESIAN_POINT('',(98.2264705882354,0.,35.9441176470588));
#2274=VERTEX_POINT('',#2273);
#2275=EDGE_CURVE('E1520',#2274,#537,#2272,.F.);
#2276=ORIENTED_EDGE('',*,*,#2275,.F.);
#2277=DIRECTION('',(0.,0.,-1.));
#2278=VECTOR('',#2277,1.);
#2279=CARTESIAN_POINT('',(98.2264705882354,0.,-45.9441176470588));
#2280=LINE('',#2279,#2278);
#2281=CARTESIAN_POINT('',(98.2264705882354,0.,-35.9441176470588));
#2282=VERTEX_POINT('',#2281);
#2283=EDGE_CURVE('E1521',#2274,#2282,#2280,.T.);
#2284=ORIENTED_EDGE('',*,*,#2283,.T.);
#2285=CARTESIAN_POINT('',(91.2264705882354,0.,-35.9441176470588));
#2286=DIRECTION('',(0.,1.,0.));
#2287=DIRECTION('',(0.,0.,1.));
#2288=AXIS2_PLACEMENT_3D('',#2285,#2286,#2287);
#2289=CIRCLE('',#2288,7.);
#2290=CARTESIAN_POINT('',(91.2264705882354,0.,-42.9441176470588));
#2291=VERTEX_POINT('',#2290);
#2292=EDGE_CURVE('E1513',#2291,#2282,#2289,.F.);
#2293=ORIENTED_EDGE('',*,*,#2292,.F.);
#2294=CARTESIAN_POINT('',(71.5742721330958,0.,-42.9441176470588));
#2295=VERTEX_POINT('',#2294);
#2296=EDGE_CURVE('E1514',#2291,#2295,#1935,.T.);
#2297=ORIENTED_EDGE('',*,*,#2296,.T.);
#2298=EDGE_CURVE('E1722',#2149,#2295,#2264,.T.);
#2299=ORIENTED_EDGE('',*,*,#2298,.F.);
#2300=ORIENTED_EDGE('',*,*,#2150,.F.);
#2301=CARTESIAN_POINT('',(91.2264705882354,0.,-35.9441176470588));
#2302=DIRECTION('',(0.,1.,0.));
#2303=DIRECTION('',(0.,0.,1.));
#2304=AXIS2_PLACEMENT_3D('',#2301,#2302,#2303);
#2305=CIRCLE('',#2304,10.);
#2306=EDGE_CURVE('E1630',#2145,#2113,#2305,.F.);
#2307=ORIENTED_EDGE('',*,*,#2306,.T.);
#2308=ORIENTED_EDGE('',*,*,#2114,.F.);
#2309=CARTESIAN_POINT('',(91.2264705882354,0.,35.9441176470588));
#2310=DIRECTION('',(0.,1.,0.));
#2311=DIRECTION('',(0.,0.,1.));
#2312=AXIS2_PLACEMENT_3D('',#2309,#2310,#2311);
#2313=CIRCLE('',#2312,10.);
#2314=EDGE_CURVE('E1627',#2105,#2073,#2313,.F.);
#2315=ORIENTED_EDGE('',*,*,#2314,.T.);
#2316=EDGE_LOOP('',(#2260,#2266,#2267,#2276,#2284,#2293,#2297,#2299,#2300,#2307,#2308,#2315));
#2317=FACE_BOUND('',#2316,.T.);
#2318=ADVANCED_FACE('F1940',(#2317),#1913,.F.);
#2319=CARTESIAN_POINT('',(91.2264705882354,25.9249069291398,35.9441176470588));
#2320=DIRECTION('',(0.,-1.,0.));
#2321=DIRECTION('',(0.,0.,-1.));
#2322=AXIS2_PLACEMENT_3D('',#2319,#2320,#2321);
#2323=CYLINDRICAL_SURFACE('',#2322,10.);
#2324=ORIENTED_EDGE('',*,*,#2314,.F.);
#2325=ORIENTED_EDGE('',*,*,#2106,.F.);
#2326=CARTESIAN_POINT('',(91.2264705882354,20.9249069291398,35.9441176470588));
#2327=DIRECTION('',(0.,1.,0.));
#2328=DIRECTION('',(0.,0.,1.));
#2329=AXIS2_PLACEMENT_3D('',#2326,#2327,#2328);
#2330=CIRCLE('',#2329,10.);
#2331=EDGE_CURVE('E1564',#2036,#2097,#2330,.T.);
#2332=ORIENTED_EDGE('',*,*,#2331,.F.);
#2333=ORIENTED_EDGE('',*,*,#2080,.F.);
#2334=EDGE_LOOP('',(#2324,#2325,#2332,#2333));
#2335=FACE_BOUND('',#2334,.T.);
#2336=ADVANCED_FACE('F2073',(#2335),#2323,.T.);
#2337=CARTESIAN_POINT('',(-101.226470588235,20.9249069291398,40.9441176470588));
#2338=DIRECTION('',(-1.,0.,0.));
#2339=DIRECTION('',(0.,0.,1.));
#2340=AXIS2_PLACEMENT_3D('',#2337,#2338,#2339);
#2341=CYLINDRICAL_SURFACE('',#2340,5.);
#2342=CARTESIAN_POINT('',(-91.2264705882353,20.9249069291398,40.9441176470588));
#2343=DIRECTION('',(-1.,0.,0.));
#2344=DIRECTION('',(0.,0.,1.));
#2345=AXIS2_PLACEMENT_3D('',#2342,#2343,#2344);
#2346=CIRCLE('',#2345,5.);
#2347=EDGE_CURVE('E1558',#2038,#2194,#2346,.T.);
#2348=ORIENTED_EDGE('',*,*,#2347,.F.);
#2349=ORIENTED_EDGE('',*,*,#2039,.F.);
#2350=CARTESIAN_POINT('',(91.2264705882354,20.9249069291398,40.9441176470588));
#2351=DIRECTION('',(1.,0.,0.));
#2352=DIRECTION('',(0.,0.,-1.));
#2353=AXIS2_PLACEMENT_3D('',#2350,#2351,#2352);
#2354=CIRCLE('',#2353,5.);
#2355=EDGE_CURVE('E1561',#2196,#2036,#2354,.T.);
#2356=ORIENTED_EDGE('',*,*,#2355,.F.);
#2357=ORIENTED_EDGE('',*,*,#2197,.F.);
#2358=EDGE_LOOP('',(#2348,#2349,#2356,#2357));
#2359=FACE_BOUND('',#2358,.T.);
#2360=ADVANCED_FACE('F2226',(#2359),#2341,.T.);
#2361=CARTESIAN_POINT('',(-91.2264705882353,25.9249069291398,35.9441176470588));
#2362=DIRECTION('',(0.,-1.,0.));
#2363=DIRECTION('',(0.,0.,-1.));
#2364=AXIS2_PLACEMENT_3D('',#2361,#2362,#2363);
#2365=CYLINDRICAL_SURFACE('',#2364,10.);
#2366=ORIENTED_EDGE('',*,*,#1975,.F.);
#2367=ORIENTED_EDGE('',*,*,#2045,.F.);
#2368=CARTESIAN_POINT('',(-91.2264705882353,20.9249069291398,35.9441176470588));
#2369=DIRECTION('',(0.,1.,0.));
#2370=DIRECTION('',(0.,0.,1.));
#2371=AXIS2_PLACEMENT_3D('',#2368,#2369,#2370);
#2372=CIRCLE('',#2371,10.);
#2373=EDGE_CURVE('E1555',#2005,#2038,#2372,.T.);
#2374=ORIENTED_EDGE('',*,*,#2373,.F.);
#2375=ORIENTED_EDGE('',*,*,#2021,.F.);
#2376=EDGE_LOOP('',(#2366,#2367,#2374,#2375));
#2377=FACE_BOUND('',#2376,.T.);
#2378=ADVANCED_FACE('F2034',(#2377),#2365,.T.);
#2379=CARTESIAN_POINT('',(91.2264705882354,20.9249069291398,35.9441176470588));
#2380=DIRECTION('',(0.,1.,0.));
#2381=DIRECTION('',(0.,0.,1.));
#2382=AXIS2_PLACEMENT_3D('',#2379,#2380,#2381);
#2383=DEGENERATE_TOROIDAL_SURFACE('',#2382,5.,5.,.T.);
#2384=ORIENTED_EDGE('',*,*,#2355,.T.);
#2385=ORIENTED_EDGE('',*,*,#2331,.T.);
#2386=CARTESIAN_POINT('',(96.2264705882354,20.9249069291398,35.9441176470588));
#2387=DIRECTION('',(0.,0.,1.));
#2388=DIRECTION('',(1.,0.,0.));
#2389=AXIS2_PLACEMENT_3D('',#2386,#2387,#2388);
#2390=CIRCLE('',#2389,5.);
#2391=EDGE_CURVE('E1552',#2205,#2097,#2390,.F.);
#2392=ORIENTED_EDGE('',*,*,#2391,.F.);
#2393=ORIENTED_EDGE('',*,*,#2206,.T.);
#2394=EDGE_LOOP('',(#2384,#2385,#2392,#2393));
#2395=FACE_BOUND('',#2394,.T.);
#2396=ADVANCED_FACE('F2067',(#2395),#2383,.T.);
#2397=CARTESIAN_POINT('',(-91.2264705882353,20.9249069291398,35.9441176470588));
#2398=DIRECTION('',(0.,1.,0.));
#2399=DIRECTION('',(0.,0.,1.));
#2400=AXIS2_PLACEMENT_3D('',#2397,#2398,#2399);
#2401=DEGENERATE_TOROIDAL_SURFACE('',#2400,5.,5.,.T.);
#2402=ORIENTED_EDGE('',*,*,#2347,.T.);
#2403=ORIENTED_EDGE('',*,*,#2255,.T.);
#2404=CARTESIAN_POINT('',(-96.2264705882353,20.9249069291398,35.9441176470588));
#2405=DIRECTION('',(0.,0.,1.));
#2406=DIRECTION('',(1.,0.,0.));
#2407=AXIS2_PLACEMENT_3D('',#2404,#2405,#2406);
#2408=CIRCLE('',#2407,5.);
#2409=EDGE_CURVE('E1549',#2005,#2247,#2408,.F.);
#2410=ORIENTED_EDGE('',*,*,#2409,.F.);
#2411=ORIENTED_EDGE('',*,*,#2373,.T.);
#2412=EDGE_LOOP('',(#2402,#2403,#2410,#2411));
#2413=FACE_BOUND('',#2412,.T.);
#2414=ADVANCED_FACE('F2218',(#2413),#2401,.T.);
#2415=CARTESIAN_POINT('',(91.2264705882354,25.9249069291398,-35.9441176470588));
#2416=DIRECTION('',(0.,-1.,0.));
#2417=DIRECTION('',(0.,0.,-1.));
#2418=AXIS2_PLACEMENT_3D('',#2415,#2416,#2417);
#2419=CYLINDRICAL_SURFACE('',#2418,10.);
#2420=ORIENTED_EDGE('',*,*,#2306,.F.);
#2421=ORIENTED_EDGE('',*,*,#2146,.F.);
#2422=CARTESIAN_POINT('',(91.2264705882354,20.9249069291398,-35.9441176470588));
#2423=DIRECTION('',(0.,1.,0.));
#2424=DIRECTION('',(0.,0.,1.));
#2425=AXIS2_PLACEMENT_3D('',#2422,#2423,#2424);
#2426=CIRCLE('',#2425,10.);
#2427=EDGE_CURVE('E1546',#2095,#2137,#2426,.T.);
#2428=ORIENTED_EDGE('',*,*,#2427,.F.);
#2429=ORIENTED_EDGE('',*,*,#2120,.F.);
#2430=EDGE_LOOP('',(#2420,#2421,#2428,#2429));
#2431=FACE_BOUND('',#2430,.T.);
#2432=ADVANCED_FACE('F2055',(#2431),#2419,.T.);
#2433=CARTESIAN_POINT('',(96.2264705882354,20.9249069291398,45.9441176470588));
#2434=DIRECTION('',(0.,0.,1.));
#2435=DIRECTION('',(1.,0.,0.));
#2436=AXIS2_PLACEMENT_3D('',#2433,#2434,#2435);
#2437=CYLINDRICAL_SURFACE('',#2436,5.);
#2438=ORIENTED_EDGE('',*,*,#2391,.T.);
#2439=ORIENTED_EDGE('',*,*,#2098,.F.);
#2440=CARTESIAN_POINT('',(96.2264705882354,20.9249069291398,-35.9441176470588));
#2441=DIRECTION('',(0.,0.,-1.));
#2442=DIRECTION('',(-1.,0.,0.));
#2443=AXIS2_PLACEMENT_3D('',#2440,#2441,#2442);
#2444=CIRCLE('',#2443,5.);
#2445=EDGE_CURVE('E1543',#2213,#2095,#2444,.T.);
#2446=ORIENTED_EDGE('',*,*,#2445,.F.);
#2447=ORIENTED_EDGE('',*,*,#2214,.F.);
#2448=EDGE_LOOP('',(#2438,#2439,#2446,#2447));
#2449=FACE_BOUND('',#2448,.T.);
#2450=ADVANCED_FACE('F2063',(#2449),#2437,.T.);
#2451=CARTESIAN_POINT('',(-96.2264705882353,20.9249069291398,45.9441176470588));
#2452=DIRECTION('',(0.,0.,-1.));
#2453=DIRECTION('',(-1.,0.,0.));
#2454=AXIS2_PLACEMENT_3D('',#2451,#2452,#2453);
#2455=CYLINDRICAL_SURFACE('',#2454,5.);
#2456=CARTESIAN_POINT('',(-96.2264705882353,20.9249069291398,-35.9441176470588));
#2457=DIRECTION('',(0.,0.,-1.));
#2458=DIRECTION('',(-1.,0.,0.));
#2459=AXIS2_PLACEMENT_3D('',#2456,#2457,#2458);
#2460=CIRCLE('',#2459,5.);
#2461=EDGE_CURVE('E1540',#2007,#2239,#2460,.T.);
#2462=ORIENTED_EDGE('',*,*,#2461,.F.);
#2463=ORIENTED_EDGE('',*,*,#2008,.F.);
#2464=ORIENTED_EDGE('',*,*,#2409,.T.);
#2465=ORIENTED_EDGE('',*,*,#2248,.F.);
#2466=EDGE_LOOP('',(#2462,#2463,#2464,#2465));
#2467=FACE_BOUND('',#2466,.T.);
#2468=ADVANCED_FACE('F2210',(#2467),#2455,.T.);
#2469=CARTESIAN_POINT('',(-91.2264705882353,25.9249069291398,-35.9441176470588));
#2470=DIRECTION('',(0.,-1.,0.));
#2471=DIRECTION('',(0.,0.,-1.));
#2472=AXIS2_PLACEMENT_3D('',#2469,#2470,#2471);
#2473=CYLINDRICAL_SURFACE('',#2472,10.);
#2474=ORIENTED_EDGE('',*,*,#1990,.F.);
#2475=ORIENTED_EDGE('',*,*,#2014,.F.);
#2476=CARTESIAN_POINT('',(-91.2264705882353,20.9249069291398,-35.9441176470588));
#2477=DIRECTION('',(0.,1.,0.));
#2478=DIRECTION('',(0.,0.,1.));
#2479=AXIS2_PLACEMENT_3D('',#2476,#2477,#2478);
#2480=CIRCLE('',#2479,10.);
#2481=EDGE_CURVE('E1537',#2135,#2007,#2480,.T.);
#2482=ORIENTED_EDGE('',*,*,#2481,.F.);
#2483=ORIENTED_EDGE('',*,*,#2179,.F.);
#2484=EDGE_LOOP('',(#2474,#2475,#2482,#2483));
#2485=FACE_BOUND('',#2484,.T.);
#2486=ADVANCED_FACE('F2044',(#2485),#2473,.T.);
#2487=CARTESIAN_POINT('',(91.2264705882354,20.9249069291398,-35.9441176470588));
#2488=DIRECTION('',(0.,1.,0.));
#2489=DIRECTION('',(0.,0.,1.));
#2490=AXIS2_PLACEMENT_3D('',#2487,#2488,#2489);
#2491=DEGENERATE_TOROIDAL_SURFACE('',#2490,5.,5.,.T.);
#2492=ORIENTED_EDGE('',*,*,#2445,.T.);
#2493=ORIENTED_EDGE('',*,*,#2427,.T.);
#2494=CARTESIAN_POINT('',(91.2264705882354,20.9249069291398,-40.9441176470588));
#2495=DIRECTION('',(1.,0.,0.));
#2496=DIRECTION('',(0.,0.,-1.));
#2497=AXIS2_PLACEMENT_3D('',#2494,#2495,#2496);
#2498=CIRCLE('',#2497,5.);
#2499=EDGE_CURVE('E1534',#2222,#2137,#2498,.F.);
#2500=ORIENTED_EDGE('',*,*,#2499,.F.);
#2501=ORIENTED_EDGE('',*,*,#2223,.T.);
#2502=EDGE_LOOP('',(#2492,#2493,#2500,#2501));
#2503=FACE_BOUND('',#2502,.T.);
#2504=ADVANCED_FACE('F2203',(#2503),#2491,.T.);
#2505=CARTESIAN_POINT('',(-91.2264705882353,20.9249069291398,-35.9441176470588));
#2506=DIRECTION('',(0.,1.,0.));
#2507=DIRECTION('',(0.,0.,1.));
#2508=AXIS2_PLACEMENT_3D('',#2505,#2506,#2507);
#2509=DEGENERATE_TOROIDAL_SURFACE('',#2508,5.,5.,.T.);
#2510=ORIENTED_EDGE('',*,*,#2461,.T.);
#2511=ORIENTED_EDGE('',*,*,#2240,.T.);
#2512=CARTESIAN_POINT('',(-91.2264705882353,20.9249069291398,-40.9441176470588));
#2513=DIRECTION('',(-1.,0.,0.));
#2514=DIRECTION('',(0.,0.,1.));
#2515=AXIS2_PLACEMENT_3D('',#2512,#2513,#2514);
#2516=CIRCLE('',#2515,5.);
#2517=EDGE_CURVE('E1512',#2135,#2230,#2516,.F.);
#2518=ORIENTED_EDGE('',*,*,#2517,.F.);
#2519=ORIENTED_EDGE('',*,*,#2481,.T.);
#2520=EDGE_LOOP('',(#2510,#2511,#2518,#2519));
#2521=FACE_BOUND('',#2520,.T.);
#2522=ADVANCED_FACE('F2199',(#2521),#2509,.T.);
#2523=CARTESIAN_POINT('',(-101.226470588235,20.9249069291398,-40.9441176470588));
#2524=DIRECTION('',(1.,0.,0.));
#2525=DIRECTION('',(0.,0.,-1.));
#2526=AXIS2_PLACEMENT_3D('',#2523,#2524,#2525);
#2527=CYLINDRICAL_SURFACE('',#2526,5.);
#2528=ORIENTED_EDGE('',*,*,#2499,.T.);
#2529=ORIENTED_EDGE('',*,*,#2138,.F.);
#2530=ORIENTED_EDGE('',*,*,#2517,.T.);
#2531=ORIENTED_EDGE('',*,*,#2231,.F.);
#2532=EDGE_LOOP('',(#2528,#2529,#2530,#2531));
#2533=FACE_BOUND('',#2532,.T.);
#2534=ADVANCED_FACE('F2163',(#2533),#2527,.T.);
#2535=CARTESIAN_POINT('',(98.2264705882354,25.9249069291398,-45.9441176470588));
#2536=DIRECTION('',(-1.,0.,0.));
#2537=DIRECTION('',(0.,0.,1.));
#2538=AXIS2_PLACEMENT_3D('',#2535,#2536,#2537);
#2539=PLANE('',#2538);
#2540=DIRECTION('',(0.,1.,0.));
#2541=VECTOR('',#2540,1.);
#2542=CARTESIAN_POINT('',(98.2264705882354,25.9249069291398,-26.4680979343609));
#2543=LINE('',#2542,#2541);
#2544=CARTESIAN_POINT('',(98.2264705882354,11.6154181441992,-26.4680979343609));
#2545=VERTEX_POINT('',#2544);
#2546=EDGE_CURVE('E1100',#2545,#1798,#2543,.T.);
#2547=ORIENTED_EDGE('',*,*,#2546,.F.);
#2548=DIRECTION('',(0.,0.,1.));
#2549=VECTOR('',#2548,1.);
#2550=CARTESIAN_POINT('',(98.2264705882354,11.6154181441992,-45.9441176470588));
#2551=LINE('',#2550,#2549);
#2552=CARTESIAN_POINT('',(98.2264705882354,11.6154181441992,-29.4680979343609));
#2553=VERTEX_POINT('',#2552);
#2554=EDGE_CURVE('E1414',#2553,#2545,#2551,.T.);
#2555=ORIENTED_EDGE('',*,*,#2554,.F.);
#2556=DIRECTION('',(0.,1.,0.));
#2557=VECTOR('',#2556,1.);
#2558=CARTESIAN_POINT('',(98.2264705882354,25.9249069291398,-29.4680979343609));
#2559=LINE('',#2558,#2557);
#2560=EDGE_CURVE('E1105',#2553,#1731,#2559,.T.);
#2561=ORIENTED_EDGE('',*,*,#2560,.T.);
#2562=ORIENTED_EDGE('',*,*,#1751,.F.);
#2563=DIRECTION('',(0.,1.,0.));
#2564=VECTOR('',#2563,1.);
#2565=CARTESIAN_POINT('',(98.2264705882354,25.9249069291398,-35.9441176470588));
#2566=LINE('',#2565,#2564);
#2567=EDGE_CURVE('E1743',#2282,#1744,#2566,.T.);
#2568=ORIENTED_EDGE('',*,*,#2567,.F.);
#2569=ORIENTED_EDGE('',*,*,#2283,.F.);
#2570=DIRECTION('',(0.,1.,0.));
#2571=VECTOR('',#2570,1.);
#2572=CARTESIAN_POINT('',(98.2264705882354,25.9249069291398,35.9441176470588));
#2573=LINE('',#2572,#2571);
#2574=CARTESIAN_POINT('',(98.2264705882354,20.9249069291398,35.9441176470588));
#2575=VERTEX_POINT('',#2574);
#2576=EDGE_CURVE('E1755',#2575,#2274,#2573,.F.);
#2577=ORIENTED_EDGE('',*,*,#2576,.F.);
#2578=CARTESIAN_POINT('',(98.2264705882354,20.9249069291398,29.4680979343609));
#2579=VERTEX_POINT('',#2578);
#2580=EDGE_CURVE('E1757',#2579,#2575,#1750,.T.);
#2581=ORIENTED_EDGE('',*,*,#2580,.F.);
#2582=DIRECTION('',(0.,1.,0.));
#2583=VECTOR('',#2582,1.);
#2584=CARTESIAN_POINT('',(98.2264705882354,25.9249069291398,29.4680979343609));
#2585=LINE('',#2584,#2583);
#2586=CARTESIAN_POINT('',(98.2264705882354,11.6154181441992,29.468097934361));
#2587=VERTEX_POINT('',#2586);
#2588=EDGE_CURVE('E1691',#2587,#2579,#2585,.T.);
#2589=ORIENTED_EDGE('',*,*,#2588,.F.);
#2590=DIRECTION('',(0.,0.,1.));
#2591=VECTOR('',#2590,1.);
#2592=CARTESIAN_POINT('',(98.2264705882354,11.6154181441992,-45.9441176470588));
#2593=LINE('',#2592,#2591);
#2594=CARTESIAN_POINT('',(98.2264705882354,11.6154181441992,26.4680979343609));
#2595=VERTEX_POINT('',#2594);
#2596=EDGE_CURVE('E1413',#2595,#2587,#2593,.T.);
#2597=ORIENTED_EDGE('',*,*,#2596,.F.);
#2598=DIRECTION('',(0.,1.,0.));
#2599=VECTOR('',#2598,1.);
#2600=CARTESIAN_POINT('',(98.2264705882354,25.9249069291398,26.4680979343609));
#2601=LINE('',#2600,#2599);
#2602=EDGE_CURVE('E1687',#2595,#1883,#2601,.T.);
#2603=ORIENTED_EDGE('',*,*,#2602,.T.);
#2604=ORIENTED_EDGE('',*,*,#1884,.F.);
#2605=DIRECTION('',(0.,1.,0.));
#2606=VECTOR('',#2605,1.);
#2607=CARTESIAN_POINT('',(98.2264705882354,25.9249069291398,1.5));
#2608=LINE('',#2607,#2606);
#2609=CARTESIAN_POINT('',(98.2264705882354,11.6154181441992,1.5));
#2610=VERTEX_POINT('',#2609);
#2611=EDGE_CURVE('E1067',#2610,#1879,#2608,.T.);
#2612=ORIENTED_EDGE('',*,*,#2611,.F.);
#2613=DIRECTION('',(0.,0.,1.));
#2614=VECTOR('',#2613,1.);
#2615=CARTESIAN_POINT('',(98.2264705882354,11.6154181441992,-45.9441176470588));
#2616=LINE('',#2615,#2614);
#2617=CARTESIAN_POINT('',(98.2264705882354,11.6154181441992,-1.5));
#2618=VERTEX_POINT('',#2617);
#2619=EDGE_CURVE('E1383',#2618,#2610,#2616,.T.);
#2620=ORIENTED_EDGE('',*,*,#2619,.F.);
#2621=DIRECTION('',(0.,1.,0.));
#2622=VECTOR('',#2621,1.);
#2623=CARTESIAN_POINT('',(98.2264705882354,25.9249069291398,-1.5));
#2624=LINE('',#2623,#2622);
#2625=EDGE_CURVE('E1075',#2618,#1802,#2624,.T.);
#2626=ORIENTED_EDGE('',*,*,#2625,.T.);
#2627=ORIENTED_EDGE('',*,*,#1803,.F.);
#2628=EDGE_LOOP('',(#2547,#2555,#2561,#2562,#2568,#2569,#2577,#2581,#2589,#2597,#2603,#2604,
#2612,#2620,#2626,#2627));
#2629=FACE_BOUND('',#2628,.T.);
#2630=ADVANCED_FACE('F1382',(#2629),#2539,.T.);
#2631=CARTESIAN_POINT('',(-101.226470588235,25.9249069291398,-42.9441176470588));
#2632=DIRECTION('',(0.,0.,1.));
#2633=DIRECTION('',(1.,0.,0.));
#2634=AXIS2_PLACEMENT_3D('',#2631,#2632,#2633);
#2635=PLANE('',#2634);
#2636=DIRECTION('',(0.,1.,0.));
#2637=VECTOR('',#2636,1.);
#2638=CARTESIAN_POINT('',(1.5,25.9249069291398,-42.9441176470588));
#2639=LINE('',#2638,#2637);
#2640=CARTESIAN_POINT('',(1.5,11.6154181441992,-42.9441176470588));
#2641=VERTEX_POINT('',#2640);
#2642=EDGE_CURVE('E35',#2641,#1161,#2639,.T.);
#2643=ORIENTED_EDGE('',*,*,#2642,.F.);
#2644=DIRECTION('',(1.,0.,0.));
#2645=VECTOR('',#2644,1.);
#2646=CARTESIAN_POINT('',(-101.226470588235,11.6154181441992,-42.9441176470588));
#2647=LINE('',#2646,#2645);
#2648=CARTESIAN_POINT('',(-1.5,11.6154181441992,-42.9441176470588));
#2649=VERTEX_POINT('',#2648);
#2650=EDGE_CURVE('E374',#2649,#2641,#2647,.T.);
#2651=ORIENTED_EDGE('',*,*,#2650,.F.);
#2652=DIRECTION('',(0.,1.,0.));
#2653=VECTOR('',#2652,1.);
#2654=CARTESIAN_POINT('',(-1.5,25.9249069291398,-42.9441176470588));
#2655=LINE('',#2654,#2653);
#2656=EDGE_CURVE('E369',#2649,#746,#2655,.T.);
#2657=ORIENTED_EDGE('',*,*,#2656,.T.);
#2658=ORIENTED_EDGE('',*,*,#763,.F.);
#2659=DIRECTION('',(0.,1.,0.));
#2660=VECTOR('',#2659,1.);
#2661=CARTESIAN_POINT('',(-49.9252123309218,25.9249069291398,-42.9441176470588));
#2662=LINE('',#2661,#2660);
#2663=CARTESIAN_POINT('',(-49.9252123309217,11.6154181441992,-42.9441176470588));
#2664=VERTEX_POINT('',#2663);
#2665=EDGE_CURVE('E1137',#2664,#756,#2662,.T.);
#2666=ORIENTED_EDGE('',*,*,#2665,.F.);
#2667=DIRECTION('',(1.,0.,0.));
#2668=VECTOR('',#2667,1.);
#2669=CARTESIAN_POINT('',(-101.226470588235,11.6154181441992,-42.9441176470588));
#2670=LINE('',#2669,#2668);
#2671=CARTESIAN_POINT('',(-52.9252123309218,11.6154181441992,-42.9441176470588));
#2672=VERTEX_POINT('',#2671);
#2673=EDGE_CURVE('E1148',#2672,#2664,#2670,.T.);
#2674=ORIENTED_EDGE('',*,*,#2673,.F.);
#2675=DIRECTION('',(0.,1.,0.));
#2676=VECTOR('',#2675,1.);
#2677=CARTESIAN_POINT('',(-52.9252123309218,25.9249069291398,-42.9441176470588));
#2678=LINE('',#2677,#2676);
#2679=EDGE_CURVE('E1143',#2672,#1439,#2678,.T.);
#2680=ORIENTED_EDGE('',*,*,#2679,.T.);
#2681=ORIENTED_EDGE('',*,*,#1452,.F.);
#2682=DIRECTION('',(0.,1.,0.));
#2683=VECTOR('',#2682,1.);
#2684=CARTESIAN_POINT('',(-91.2264705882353,25.9249069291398,-42.9441176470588));
#2685=LINE('',#2684,#2683);
#2686=EDGE_CURVE('E1472',#1937,#1449,#2685,.T.);
#2687=ORIENTED_EDGE('',*,*,#2686,.F.);
#2688=ORIENTED_EDGE('',*,*,#1938,.F.);
#2689=DIRECTION('',(0.,-1.,0.));
#2690=VECTOR('',#2689,1.);
#2691=CARTESIAN_POINT('',(-71.5742721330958,25.9249069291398,-42.9441176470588));
#2692=LINE('',#2691,#2690);
#2693=CARTESIAN_POINT('',(-71.5742721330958,6.34634427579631,-42.9441176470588));
#2694=VERTEX_POINT('',#2693);
#2695=EDGE_CURVE('E1639',#2694,#1929,#2692,.T.);
#2696=ORIENTED_EDGE('',*,*,#2695,.F.);
#2697=DIRECTION('',(-1.,0.,0.));
#2698=VECTOR('',#2697,1.);
#2699=CARTESIAN_POINT('',(-101.226470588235,6.34634427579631,-42.9441176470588));
#2700=LINE('',#2699,#2698);
#2701=CARTESIAN_POINT('',(71.5742721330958,6.34634427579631,-42.9441176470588));
#2702=VERTEX_POINT('',#2701);
#2703=EDGE_CURVE('E1637',#2702,#2694,#2700,.T.);
#2704=ORIENTED_EDGE('',*,*,#2703,.F.);
#2705=DIRECTION('',(0.,1.,0.));
#2706=VECTOR('',#2705,1.);
#2707=CARTESIAN_POINT('',(71.5742721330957,25.9249069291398,-42.9441176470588));
#2708=LINE('',#2707,#2706);
#2709=EDGE_CURVE('E1635',#2295,#2702,#2708,.T.);
#2710=ORIENTED_EDGE('',*,*,#2709,.F.);
#2711=ORIENTED_EDGE('',*,*,#2296,.F.);
#2712=DIRECTION('',(0.,1.,0.));
#2713=VECTOR('',#2712,1.);
#2714=CARTESIAN_POINT('',(91.2264705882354,25.9249069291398,-42.9441176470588));
#2715=LINE('',#2714,#2713);
#2716=CARTESIAN_POINT('',(91.2264705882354,20.9249069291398,-42.9441176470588));
#2717=VERTEX_POINT('',#2716);
#2718=EDGE_CURVE('E1475',#2717,#2291,#2715,.F.);
#2719=ORIENTED_EDGE('',*,*,#2718,.F.);
#2720=CARTESIAN_POINT('',(52.9252123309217,20.9249069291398,-42.9441176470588));
#2721=VERTEX_POINT('',#2720);
#2722=EDGE_CURVE('E1470',#2721,#2717,#762,.T.);
#2723=ORIENTED_EDGE('',*,*,#2722,.F.);
#2724=DIRECTION('',(0.,1.,0.));
#2725=VECTOR('',#2724,1.);
#2726=CARTESIAN_POINT('',(52.9252123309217,25.9249069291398,-42.9441176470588));
#2727=LINE('',#2726,#2725);
#2728=CARTESIAN_POINT('',(52.9252123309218,11.6154181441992,-42.9441176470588));
#2729=VERTEX_POINT('',#2728);
#2730=EDGE_CURVE('E1222',#2729,#2721,#2727,.T.);
#2731=ORIENTED_EDGE('',*,*,#2730,.F.);
#2732=DIRECTION('',(1.,0.,0.));
#2733=VECTOR('',#2732,1.);
#2734=CARTESIAN_POINT('',(-101.226470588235,11.6154181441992,-42.9441176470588));
#2735=LINE('',#2734,#2733);
#2736=CARTESIAN_POINT('',(49.9252123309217,11.6154181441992,-42.9441176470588));
#2737=VERTEX_POINT('',#2736);
#2738=EDGE_CURVE('E1233',#2737,#2729,#2735,.T.);
#2739=ORIENTED_EDGE('',*,*,#2738,.F.);
#2740=DIRECTION('',(0.,1.,0.));
#2741=VECTOR('',#2740,1.);
#2742=CARTESIAN_POINT('',(49.9252123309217,25.9249069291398,-42.9441176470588));
#2743=LINE('',#2742,#2741);
#2744=EDGE_CURVE('E1227',#2737,#1165,#2743,.T.);
#2745=ORIENTED_EDGE('',*,*,#2744,.T.);
#2746=ORIENTED_EDGE('',*,*,#1166,.F.);
#2747=EDGE_LOOP('',(#2643,#2651,#2657,#2658,#2666,#2674,#2680,#2681,#2687,#2688,#2696,#2704,
#2710,#2711,#2719,#2723,#2731,#2739,#2745,#2746));
#2748=FACE_BOUND('',#2747,.T.);
#2749=ADVANCED_FACE('F1458',(#2748),#2635,.T.);
#2750=CARTESIAN_POINT('',(52.9252123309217,22.9249069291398,-29.4680979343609));
#2751=VERTEX_POINT('',#2750);
#2752=EDGE_CURVE('E1430',#2751,#1729,#713,.T.);
#2753=ORIENTED_EDGE('',*,*,#2752,.F.);
#2754=DIRECTION('',(0.,0.,-1.));
#2755=VECTOR('',#2754,1.);
#2756=CARTESIAN_POINT('',(52.9252123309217,22.9249069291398,45.9441176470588));
#2757=LINE('',#2756,#2755);
#2758=CARTESIAN_POINT('',(52.9252123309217,22.9249069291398,-40.9441176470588));
#2759=VERTEX_POINT('',#2758);
#2760=EDGE_CURVE('E1225',#2751,#2759,#2757,.T.);
#2761=ORIENTED_EDGE('',*,*,#2760,.T.);
#2762=CARTESIAN_POINT('',(91.2264705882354,22.9249069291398,-40.9441176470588));
#2763=VERTEX_POINT('',#2762);
#2764=EDGE_CURVE('E1772',#2763,#2759,#729,.F.);
#2765=ORIENTED_EDGE('',*,*,#2764,.F.);
#2766=CARTESIAN_POINT('',(91.2264705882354,22.9249069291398,-35.9441176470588));
#2767=DIRECTION('',(0.,1.,0.));
#2768=DIRECTION('',(0.,0.,1.));
#2769=AXIS2_PLACEMENT_3D('',#2766,#2767,#2768);
#2770=CIRCLE('',#2769,5.);
#2771=EDGE_CURVE('E1771',#2763,#1735,#2770,.F.);
#2772=ORIENTED_EDGE('',*,*,#2771,.T.);
#2773=ORIENTED_EDGE('',*,*,#1736,.F.);
#2774=EDGE_LOOP('',(#2753,#2761,#2765,#2772,#2773));
#2775=FACE_BOUND('',#2774,.T.);
#2776=ADVANCED_FACE('F1855',(#2775),#629,.F.);
#2777=CARTESIAN_POINT('',(91.2264705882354,25.9249069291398,35.9441176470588));
#2778=DIRECTION('',(0.,-1.,0.));
#2779=DIRECTION('',(0.,0.,-1.));
#2780=AXIS2_PLACEMENT_3D('',#2777,#2778,#2779);
#2781=CYLINDRICAL_SURFACE('',#2780,7.);
#2782=ORIENTED_EDGE('',*,*,#2275,.T.);
#2783=ORIENTED_EDGE('',*,*,#538,.T.);
#2784=CARTESIAN_POINT('',(91.2264705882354,20.9249069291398,35.9441176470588));
#2785=DIRECTION('',(0.,1.,0.));
#2786=DIRECTION('',(0.,0.,1.));
#2787=AXIS2_PLACEMENT_3D('',#2784,#2785,#2786);
#2788=CIRCLE('',#2787,7.);
#2789=EDGE_CURVE('E1508',#529,#2575,#2788,.T.);
#2790=ORIENTED_EDGE('',*,*,#2789,.T.);
#2791=ORIENTED_EDGE('',*,*,#2576,.T.);
#2792=EDGE_LOOP('',(#2782,#2783,#2790,#2791));
#2793=FACE_BOUND('',#2792,.T.);
#2794=ADVANCED_FACE('F2080',(#2793),#2781,.F.);
#2795=ORIENTED_EDGE('',*,*,#1855,.T.);
#2796=CARTESIAN_POINT('',(-52.9252123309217,20.9249069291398,40.9441176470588));
#2797=DIRECTION('',(-1.,0.,0.));
#2798=DIRECTION('',(0.,0.,1.));
#2799=AXIS2_PLACEMENT_3D('',#2796,#2797,#2798);
#2800=CIRCLE('',#2799,2.);
#2801=EDGE_CURVE('E1436',#1850,#585,#2800,.F.);
#2802=ORIENTED_EDGE('',*,*,#2801,.T.);
#2803=ORIENTED_EDGE('',*,*,#586,.T.);
#2804=CARTESIAN_POINT('',(-91.2264705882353,20.9249069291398,40.9441176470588));
#2805=DIRECTION('',(-1.,0.,0.));
#2806=DIRECTION('',(0.,0.,1.));
#2807=AXIS2_PLACEMENT_3D('',#2804,#2805,#2806);
#2808=CIRCLE('',#2807,2.);
#2809=EDGE_CURVE('E1747',#581,#1854,#2808,.T.);
#2810=ORIENTED_EDGE('',*,*,#2809,.T.);
#2811=EDGE_LOOP('',(#2795,#2802,#2803,#2810));
#2812=FACE_BOUND('',#2811,.T.);
#2813=ADVANCED_FACE('F2170',(#2812),#998,.F.);
#2814=CARTESIAN_POINT('',(-91.2264705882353,25.9249069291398,35.9441176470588));
#2815=DIRECTION('',(0.,-1.,0.));
#2816=DIRECTION('',(0.,0.,-1.));
#2817=AXIS2_PLACEMENT_3D('',#2814,#2815,#2816);
#2818=CYLINDRICAL_SURFACE('',#2817,7.);
#2819=ORIENTED_EDGE('',*,*,#1953,.T.);
#2820=ORIENTED_EDGE('',*,*,#1694,.T.);
#2821=CARTESIAN_POINT('',(-91.2264705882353,20.9249069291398,35.9441176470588));
#2822=DIRECTION('',(0.,1.,0.));
#2823=DIRECTION('',(0.,0.,1.));
#2824=AXIS2_PLACEMENT_3D('',#2821,#2822,#2823);
#2825=CIRCLE('',#2824,7.);
#2826=EDGE_CURVE('E1744',#1685,#581,#2825,.T.);
#2827=ORIENTED_EDGE('',*,*,#2826,.T.);
#2828=ORIENTED_EDGE('',*,*,#582,.T.);
#2829=EDGE_LOOP('',(#2819,#2820,#2827,#2828));
#2830=FACE_BOUND('',#2829,.T.);
#2831=ADVANCED_FACE('F2013',(#2830),#2818,.F.);
#2832=CARTESIAN_POINT('',(91.2264705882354,20.9249069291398,35.9441176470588));
#2833=DIRECTION('',(0.,1.,0.));
#2834=DIRECTION('',(0.,0.,1.));
#2835=AXIS2_PLACEMENT_3D('',#2832,#2833,#2834);
#2836=TOROIDAL_SURFACE('',#2835,5.,2.);
#2837=ORIENTED_EDGE('',*,*,#1067,.F.);
#2838=ORIENTED_EDGE('',*,*,#1047,.F.);
#2839=CARTESIAN_POINT('',(96.2264705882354,20.9249069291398,35.9441176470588));
#2840=DIRECTION('',(0.,0.,1.));
#2841=DIRECTION('',(1.,0.,0.));
#2842=AXIS2_PLACEMENT_3D('',#2839,#2840,#2841);
#2843=CIRCLE('',#2842,2.);
#2844=EDGE_CURVE('E1748',#1037,#2575,#2843,.F.);
#2845=ORIENTED_EDGE('',*,*,#2844,.T.);
#2846=ORIENTED_EDGE('',*,*,#2789,.F.);
#2847=EDGE_LOOP('',(#2837,#2838,#2845,#2846));
#2848=FACE_BOUND('',#2847,.T.);
#2849=ADVANCED_FACE('F1977',(#2848),#2836,.F.);
#2850=CARTESIAN_POINT('',(-91.2264705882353,20.9249069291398,35.9441176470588));
#2851=DIRECTION('',(0.,1.,0.));
#2852=DIRECTION('',(0.,0.,1.));
#2853=AXIS2_PLACEMENT_3D('',#2850,#2851,#2852);
#2854=TOROIDAL_SURFACE('',#2853,5.,2.);
#2855=ORIENTED_EDGE('',*,*,#2809,.F.);
#2856=ORIENTED_EDGE('',*,*,#2826,.F.);
#2857=ORIENTED_EDGE('',*,*,#1903,.T.);
#2858=ORIENTED_EDGE('',*,*,#1864,.F.);
#2859=EDGE_LOOP('',(#2855,#2856,#2857,#2858));
#2860=FACE_BOUND('',#2859,.T.);
#2861=ADVANCED_FACE('F2010',(#2860),#2854,.F.);
#2862=CARTESIAN_POINT('',(91.2264705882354,25.9249069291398,-35.9441176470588));
#2863=DIRECTION('',(0.,-1.,0.));
#2864=DIRECTION('',(0.,0.,-1.));
#2865=AXIS2_PLACEMENT_3D('',#2862,#2863,#2864);
#2866=CYLINDRICAL_SURFACE('',#2865,7.);
#2867=ORIENTED_EDGE('',*,*,#2292,.T.);
#2868=ORIENTED_EDGE('',*,*,#2567,.T.);
#2869=CARTESIAN_POINT('',(91.2264705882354,20.9249069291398,-35.9441176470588));
#2870=DIRECTION('',(0.,1.,0.));
#2871=DIRECTION('',(0.,0.,1.));
#2872=AXIS2_PLACEMENT_3D('',#2869,#2870,#2871);
#2873=CIRCLE('',#2872,7.);
#2874=EDGE_CURVE('E1490',#1744,#2717,#2873,.T.);
#2875=ORIENTED_EDGE('',*,*,#2874,.T.);
#2876=ORIENTED_EDGE('',*,*,#2718,.T.);
#2877=EDGE_LOOP('',(#2867,#2868,#2875,#2876));
#2878=FACE_BOUND('',#2877,.T.);
#2879=ADVANCED_FACE('F1945',(#2878),#2866,.F.);
#2880=ORIENTED_EDGE('',*,*,#1038,.T.);
#2881=CARTESIAN_POINT('',(96.2264705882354,20.9249069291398,29.4680979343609));
#2882=DIRECTION('',(0.,0.,1.));
#2883=DIRECTION('',(1.,0.,0.));
#2884=AXIS2_PLACEMENT_3D('',#2881,#2882,#2883);
#2885=CIRCLE('',#2884,2.);
#2886=EDGE_CURVE('E1653',#1029,#2579,#2885,.F.);
#2887=ORIENTED_EDGE('',*,*,#2886,.T.);
#2888=ORIENTED_EDGE('',*,*,#2580,.T.);
#2889=ORIENTED_EDGE('',*,*,#2844,.F.);
#2890=EDGE_LOOP('',(#2880,#2887,#2888,#2889));
#2891=FACE_BOUND('',#2890,.T.);
#2892=ADVANCED_FACE('F1985',(#2891),#1722,.F.);
#2893=ORIENTED_EDGE('',*,*,#1398,.T.);
#2894=ORIENTED_EDGE('',*,*,#1642,.T.);
#2895=ORIENTED_EDGE('',*,*,#1712,.T.);
#2896=CARTESIAN_POINT('',(-96.2264705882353,20.9249069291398,-35.9441176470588));
#2897=DIRECTION('',(0.,0.,-1.));
#2898=DIRECTION('',(-1.,0.,0.));
#2899=AXIS2_PLACEMENT_3D('',#2896,#2897,#2898);
#2900=CIRCLE('',#2899,2.);
#2901=EDGE_CURVE('E1496',#1709,#1397,#2900,.T.);
#2902=ORIENTED_EDGE('',*,*,#2901,.T.);
#2903=EDGE_LOOP('',(#2893,#2894,#2895,#2902));
#2904=FACE_BOUND('',#2903,.T.);
#2905=ADVANCED_FACE('F1915',(#2904),#1783,.F.);
#2906=CARTESIAN_POINT('',(-91.2264705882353,25.9249069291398,-35.9441176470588));
#2907=DIRECTION('',(0.,-1.,0.));
#2908=DIRECTION('',(0.,0.,-1.));
#2909=AXIS2_PLACEMENT_3D('',#2906,#2907,#2908);
#2910=CYLINDRICAL_SURFACE('',#2909,7.);
#2911=ORIENTED_EDGE('',*,*,#1945,.T.);
#2912=ORIENTED_EDGE('',*,*,#2686,.T.);
#2913=CARTESIAN_POINT('',(-91.2264705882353,20.9249069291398,-35.9441176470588));
#2914=DIRECTION('',(0.,1.,0.));
#2915=DIRECTION('',(0.,0.,1.));
#2916=AXIS2_PLACEMENT_3D('',#2913,#2914,#2915);
#2917=CIRCLE('',#2916,7.);
#2918=EDGE_CURVE('E1499',#1449,#1709,#2917,.T.);
#2919=ORIENTED_EDGE('',*,*,#2918,.T.);
#2920=ORIENTED_EDGE('',*,*,#1710,.T.);
#2921=EDGE_LOOP('',(#2911,#2912,#2919,#2920));
#2922=FACE_BOUND('',#2921,.T.);
#2923=ADVANCED_FACE('F1807',(#2922),#2910,.F.);
#2924=CARTESIAN_POINT('',(91.2264705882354,20.9249069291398,-35.9441176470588));
#2925=DIRECTION('',(0.,1.,0.));
#2926=DIRECTION('',(0.,0.,1.));
#2927=AXIS2_PLACEMENT_3D('',#2924,#2925,#2926);
#2928=TOROIDAL_SURFACE('',#2927,5.,2.);
#2929=ORIENTED_EDGE('',*,*,#1745,.F.);
#2930=ORIENTED_EDGE('',*,*,#2771,.F.);
#2931=CARTESIAN_POINT('',(91.2264705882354,20.9249069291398,-40.9441176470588));
#2932=DIRECTION('',(1.,0.,0.));
#2933=DIRECTION('',(0.,0.,-1.));
#2934=AXIS2_PLACEMENT_3D('',#2931,#2932,#2933);
#2935=CIRCLE('',#2934,2.);
#2936=EDGE_CURVE('E1497',#2763,#2717,#2935,.F.);
#2937=ORIENTED_EDGE('',*,*,#2936,.T.);
#2938=ORIENTED_EDGE('',*,*,#2874,.F.);
#2939=EDGE_LOOP('',(#2929,#2930,#2937,#2938));
#2940=FACE_BOUND('',#2939,.T.);
#2941=ADVANCED_FACE('F1950',(#2940),#2928,.F.);
#2942=CARTESIAN_POINT('',(-91.2264705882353,20.9249069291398,-35.9441176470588));
#2943=DIRECTION('',(0.,1.,0.));
#2944=DIRECTION('',(0.,0.,1.));
#2945=AXIS2_PLACEMENT_3D('',#2942,#2943,#2944);
#2946=TOROIDAL_SURFACE('',#2945,5.,2.);
#2947=ORIENTED_EDGE('',*,*,#2901,.F.);
#2948=ORIENTED_EDGE('',*,*,#2918,.F.);
#2949=ORIENTED_EDGE('',*,*,#1450,.T.);
#2950=ORIENTED_EDGE('',*,*,#1407,.F.);
#2951=EDGE_LOOP('',(#2947,#2948,#2949,#2950));
#2952=FACE_BOUND('',#2951,.T.);
#2953=ADVANCED_FACE('F1813',(#2952),#2946,.F.);
#2954=ORIENTED_EDGE('',*,*,#2764,.T.);
#2955=CARTESIAN_POINT('',(52.9252123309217,20.9249069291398,-40.9441176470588));
#2956=DIRECTION('',(1.,0.,0.));
#2957=DIRECTION('',(0.,0.,-1.));
#2958=AXIS2_PLACEMENT_3D('',#2955,#2956,#2957);
#2959=CIRCLE('',#2958,2.);
#2960=EDGE_CURVE('E1442',#2759,#2721,#2959,.F.);
#2961=ORIENTED_EDGE('',*,*,#2960,.T.);
#2962=ORIENTED_EDGE('',*,*,#2722,.T.);
#2963=ORIENTED_EDGE('',*,*,#2936,.F.);
#2964=EDGE_LOOP('',(#2954,#2961,#2962,#2963));
#2965=FACE_BOUND('',#2964,.T.);
#2966=ADVANCED_FACE('F2194',(#2965),#739,.F.);
#2967=CARTESIAN_POINT('',(71.5742721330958,0.,-45.9441176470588));
#2968=DIRECTION('',(1.,0.,0.));
#2969=DIRECTION('',(0.,0.,-1.));
#2970=AXIS2_PLACEMENT_3D('',#2967,#2968,#2969);
#2971=PLANE('',#2970);
#2972=ORIENTED_EDGE('',*,*,#2709,.T.);
#2973=DIRECTION('',(0.,0.,1.));
#2974=VECTOR('',#2973,1.);
#2975=CARTESIAN_POINT('',(71.5742721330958,6.34634427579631,-45.9441176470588));
#2976=LINE('',#2975,#2974);
#2977=EDGE_CURVE('E1718',#2157,#2702,#2976,.T.);
#2978=ORIENTED_EDGE('',*,*,#2977,.F.);
#2979=ORIENTED_EDGE('',*,*,#2158,.F.);
#2980=ORIENTED_EDGE('',*,*,#2298,.T.);
#2981=EDGE_LOOP('',(#2972,#2978,#2979,#2980));
#2982=FACE_BOUND('',#2981,.T.);
#2983=ADVANCED_FACE('F1935',(#2982),#2971,.F.);
#2984=CARTESIAN_POINT('',(-71.5742721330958,6.34634427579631,-45.9441176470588));
#2985=DIRECTION('',(0.,1.,0.));
#2986=DIRECTION('',(0.,0.,1.));
#2987=AXIS2_PLACEMENT_3D('',#2984,#2985,#2986);
#2988=PLANE('',#2987);
#2989=ORIENTED_EDGE('',*,*,#2703,.T.);
#2990=DIRECTION('',(0.,0.,1.));
#2991=VECTOR('',#2990,1.);
#2992=CARTESIAN_POINT('',(-71.5742721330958,6.34634427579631,-45.9441176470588));
#2993=LINE('',#2992,#2991);
#2994=EDGE_CURVE('E1713',#2165,#2694,#2993,.T.);
#2995=ORIENTED_EDGE('',*,*,#2994,.F.);
#2996=ORIENTED_EDGE('',*,*,#2166,.F.);
#2997=ORIENTED_EDGE('',*,*,#2977,.T.);
#2998=EDGE_LOOP('',(#2989,#2995,#2996,#2997));
#2999=FACE_BOUND('',#2998,.T.);
#3000=ADVANCED_FACE('F1933',(#2999),#2988,.F.);
#3001=CARTESIAN_POINT('',(-71.5742721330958,0.,-45.9441176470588));
#3002=DIRECTION('',(-1.,0.,0.));
#3003=DIRECTION('',(0.,0.,1.));
#3004=AXIS2_PLACEMENT_3D('',#3001,#3002,#3003);
#3005=PLANE('',#3004);
#3006=ORIENTED_EDGE('',*,*,#2695,.T.);
#3007=ORIENTED_EDGE('',*,*,#1930,.F.);
#3008=ORIENTED_EDGE('',*,*,#2172,.F.);
#3009=ORIENTED_EDGE('',*,*,#2994,.T.);
#3010=EDGE_LOOP('',(#3006,#3007,#3008,#3009));
#3011=FACE_BOUND('',#3010,.T.);
#3012=ADVANCED_FACE('F1929',(#3011),#3005,.F.);
#3013=ORIENTED_EDGE('',*,*,#570,.T.);
#3014=EDGE_CURVE('E1717',#561,#2053,#2993,.T.);
#3015=ORIENTED_EDGE('',*,*,#3014,.T.);
#3016=ORIENTED_EDGE('',*,*,#2054,.T.);
#3017=ORIENTED_EDGE('',*,*,#1958,.F.);
#3018=EDGE_LOOP('',(#3013,#3015,#3016,#3017));
#3019=FACE_BOUND('',#3018,.T.);
#3020=ADVANCED_FACE('F2021',(#3019),#3005,.F.);
#3021=ORIENTED_EDGE('',*,*,#562,.T.);
#3022=EDGE_CURVE('E1721',#553,#2061,#2976,.T.);
#3023=ORIENTED_EDGE('',*,*,#3022,.T.);
#3024=ORIENTED_EDGE('',*,*,#2062,.T.);
#3025=ORIENTED_EDGE('',*,*,#3014,.F.);
#3026=EDGE_LOOP('',(#3021,#3023,#3024,#3025));
#3027=FACE_BOUND('',#3026,.T.);
#3028=ADVANCED_FACE('F2023',(#3027),#2988,.F.);
#3029=ORIENTED_EDGE('',*,*,#554,.T.);
#3030=ORIENTED_EDGE('',*,*,#2265,.T.);
#3031=ORIENTED_EDGE('',*,*,#2070,.T.);
#3032=ORIENTED_EDGE('',*,*,#3022,.F.);
#3033=EDGE_LOOP('',(#3029,#3030,#3031,#3032));
#3034=FACE_BOUND('',#3033,.T.);
#3035=ADVANCED_FACE('F2078',(#3034),#2971,.F.);
#3036=DIRECTION('',(0.,1.,0.));
#3037=VECTOR('',#3036,1.);
#3038=CARTESIAN_POINT('',(52.9252123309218,11.6154181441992,29.4680979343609));
#3039=LINE('',#3038,#3037);
#3040=CARTESIAN_POINT('',(52.9252123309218,11.6154181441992,29.4680979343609));
#3041=VERTEX_POINT('',#3040);
#3042=EDGE_CURVE('E1236',#3041,#1023,#3039,.T.);
#3043=ORIENTED_EDGE('',*,*,#3042,.F.);
#3044=EDGE_CURVE('E1038',#3041,#2587,#776,.T.);
#3045=ORIENTED_EDGE('',*,*,#3044,.T.);
#3046=ORIENTED_EDGE('',*,*,#2588,.T.);
#3047=ORIENTED_EDGE('',*,*,#2886,.F.);
#3048=ORIENTED_EDGE('',*,*,#1030,.F.);
#3049=EDGE_LOOP('',(#3043,#3045,#3046,#3047,#3048));
#3050=FACE_BOUND('',#3049,.T.);
#3051=ADVANCED_FACE('F1986',(#3050),#772,.T.);
#3052=CARTESIAN_POINT('',(52.9252123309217,11.6154181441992,26.4680979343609));
#3053=VERTEX_POINT('',#3052);
#3054=EDGE_CURVE('E1054',#3053,#2595,#824,.T.);
#3055=ORIENTED_EDGE('',*,*,#3054,.F.);
#3056=DIRECTION('',(0.,1.,0.));
#3057=VECTOR('',#3056,1.);
#3058=CARTESIAN_POINT('',(52.9252123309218,11.6154181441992,26.4680979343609));
#3059=LINE('',#3058,#3057);
#3060=EDGE_CURVE('E1239',#3053,#1816,#3059,.T.);
#3061=ORIENTED_EDGE('',*,*,#3060,.T.);
#3062=ORIENTED_EDGE('',*,*,#1819,.T.);
#3063=ORIENTED_EDGE('',*,*,#1891,.T.);
#3064=ORIENTED_EDGE('',*,*,#2602,.F.);
#3065=EDGE_LOOP('',(#3055,#3061,#3062,#3063,#3064));
#3066=FACE_BOUND('',#3065,.T.);
#3067=ADVANCED_FACE('F1962',(#3066),#812,.F.);
#3068=CARTESIAN_POINT('',(90.5204029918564,11.6154181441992,27.9680979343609));
#3069=DIRECTION('',(0.,-1.,0.));
#3070=DIRECTION('',(1.,0.,0.));
#3071=AXIS2_PLACEMENT_3D('',#3068,#3069,#3070);
#3072=PLANE('',#3071);
#3073=DIRECTION('',(0.,0.,-1.));
#3074=VECTOR('',#3073,1.);
#3075=CARTESIAN_POINT('',(1.5,11.6154181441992,37.2907972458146));
#3076=LINE('',#3075,#3074);
#3077=EDGE_CURVE('E1354',#1201,#1227,#3076,.T.);
#3078=ORIENTED_EDGE('',*,*,#3077,.F.);
#3079=ORIENTED_EDGE('',*,*,#1204,.T.);
#3080=DIRECTION('',(0.,0.,-1.));
#3081=VECTOR('',#3080,1.);
#3082=CARTESIAN_POINT('',(49.9252123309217,11.6154181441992,37.2907972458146));
#3083=LINE('',#3082,#3081);
#3084=EDGE_CURVE('E1293',#1203,#1231,#3083,.T.);
#3085=ORIENTED_EDGE('',*,*,#3084,.T.);
#3086=ORIENTED_EDGE('',*,*,#1232,.F.);
#3087=EDGE_LOOP('',(#3078,#3079,#3085,#3086));
#3088=FACE_BOUND('',#3087,.T.);
#3089=EDGE_CURVE('E1355',#1245,#1271,#3076,.T.);
#3090=ORIENTED_EDGE('',*,*,#3089,.F.);
#3091=ORIENTED_EDGE('',*,*,#1248,.T.);
#3092=EDGE_CURVE('E1289',#1247,#1275,#3083,.T.);
#3093=ORIENTED_EDGE('',*,*,#3092,.T.);
#3094=ORIENTED_EDGE('',*,*,#1276,.F.);
#3095=EDGE_LOOP('',(#3090,#3091,#3093,#3094));
#3096=FACE_BOUND('',#3095,.T.);
#3097=ORIENTED_EDGE('',*,*,#889,.T.);
#3098=DIRECTION('',(0.,0.,-1.));
#3099=VECTOR('',#3098,1.);
#3100=CARTESIAN_POINT('',(-1.5,11.6154181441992,37.2907972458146));
#3101=LINE('',#3100,#3099);
#3102=EDGE_CURVE('E1888',#880,#913,#3101,.T.);
#3103=ORIENTED_EDGE('',*,*,#3102,.T.);
#3104=ORIENTED_EDGE('',*,*,#914,.F.);
#3105=DIRECTION('',(0.,0.,-1.));
#3106=VECTOR('',#3105,1.);
#3107=CARTESIAN_POINT('',(-49.9252123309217,11.6154181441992,37.2907972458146));
#3108=LINE('',#3107,#3106);
#3109=EDGE_CURVE('E2108',#888,#911,#3108,.T.);
#3110=ORIENTED_EDGE('',*,*,#3109,.F.);
#3111=EDGE_LOOP('',(#3097,#3103,#3104,#3110));
#3112=FACE_BOUND('',#3111,.T.);
#3113=ORIENTED_EDGE('',*,*,#827,.T.);
#3114=EDGE_CURVE('E1029',#818,#851,#3101,.T.);
#3115=ORIENTED_EDGE('',*,*,#3114,.T.);
#3116=ORIENTED_EDGE('',*,*,#852,.F.);
#3117=EDGE_CURVE('E1197',#826,#849,#3108,.T.);
#3118=ORIENTED_EDGE('',*,*,#3117,.F.);
#3119=EDGE_LOOP('',(#3113,#3115,#3116,#3118));
#3120=FACE_BOUND('',#3119,.T.);
#3121=ORIENTED_EDGE('',*,*,#951,.T.);
#3122=EDGE_CURVE('E1031',#942,#2649,#3101,.T.);
#3123=ORIENTED_EDGE('',*,*,#3122,.T.);
#3124=ORIENTED_EDGE('',*,*,#2650,.T.);
#3125=DIRECTION('',(0.,0.,-1.));
#3126=VECTOR('',#3125,1.);
#3127=CARTESIAN_POINT('',(1.5,11.6154181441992,-37.5915294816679));
#3128=LINE('',#3127,#3126);
#3129=EDGE_CURVE('E1028',#1289,#2641,#3128,.T.);
#3130=ORIENTED_EDGE('',*,*,#3129,.F.);
#3131=ORIENTED_EDGE('',*,*,#1292,.T.);
#3132=DIRECTION('',(0.,0.,-1.));
#3133=VECTOR('',#3132,1.);
#3134=CARTESIAN_POINT('',(49.9252123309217,11.6154181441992,-35.4864038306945));
#3135=LINE('',#3134,#3133);
#3136=EDGE_CURVE('E1290',#1291,#2737,#3135,.T.);
#3137=ORIENTED_EDGE('',*,*,#3136,.T.);
#3138=ORIENTED_EDGE('',*,*,#2738,.T.);
#3139=DIRECTION('',(0.,0.,-1.));
#3140=VECTOR('',#3139,1.);
#3141=CARTESIAN_POINT('',(52.9252123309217,11.6154181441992,37.2907972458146));
#3142=LINE('',#3141,#3140);
#3143=CARTESIAN_POINT('',(52.9252123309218,11.6154181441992,-29.4680979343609));
#3144=VERTEX_POINT('',#3143);
#3145=EDGE_CURVE('E1285',#3144,#2729,#3142,.T.);
#3146=ORIENTED_EDGE('',*,*,#3145,.F.);
#3147=EDGE_CURVE('E1130',#3144,#2553,#948,.T.);
#3148=ORIENTED_EDGE('',*,*,#3147,.T.);
#3149=ORIENTED_EDGE('',*,*,#2554,.T.);
#3150=CARTESIAN_POINT('',(52.9252123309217,11.6154181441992,-26.4680979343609));
#3151=VERTEX_POINT('',#3150);
#3152=EDGE_CURVE('E1124',#3151,#2545,#909,.T.);
#3153=ORIENTED_EDGE('',*,*,#3152,.F.);
#3154=CARTESIAN_POINT('',(52.9252123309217,11.6154181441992,-1.5));
#3155=VERTEX_POINT('',#3154);
#3156=EDGE_CURVE('E1955',#3155,#3151,#3142,.T.);
#3157=ORIENTED_EDGE('',*,*,#3156,.F.);
#3158=EDGE_CURVE('E1099',#3155,#2618,#886,.T.);
#3159=ORIENTED_EDGE('',*,*,#3158,.T.);
#3160=ORIENTED_EDGE('',*,*,#2619,.T.);
#3161=CARTESIAN_POINT('',(52.9252123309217,11.6154181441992,1.5));
#3162=VERTEX_POINT('',#3161);
#3163=EDGE_CURVE('E1093',#3162,#2610,#847,.T.);
#3164=ORIENTED_EDGE('',*,*,#3163,.F.);
#3165=EDGE_CURVE('E1284',#3053,#3162,#3142,.T.);
#3166=ORIENTED_EDGE('',*,*,#3165,.F.);
#3167=ORIENTED_EDGE('',*,*,#3054,.T.);
#3168=ORIENTED_EDGE('',*,*,#2596,.T.);
#3169=ORIENTED_EDGE('',*,*,#3044,.F.);
#3170=EDGE_CURVE('E1281',#517,#3041,#3142,.T.);
#3171=ORIENTED_EDGE('',*,*,#3170,.F.);
#3172=ORIENTED_EDGE('',*,*,#518,.T.);
#3173=DIRECTION('',(0.,0.,1.));
#3174=VECTOR('',#3173,1.);
#3175=CARTESIAN_POINT('',(49.9252123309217,11.6154181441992,37.2907972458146));
#3176=LINE('',#3175,#3174);
#3177=EDGE_CURVE('E1286',#1187,#509,#3176,.T.);
#3178=ORIENTED_EDGE('',*,*,#3177,.F.);
#3179=ORIENTED_EDGE('',*,*,#1188,.F.);
#3180=EDGE_CURVE('E1017',#483,#1183,#3076,.T.);
#3181=ORIENTED_EDGE('',*,*,#3180,.F.);
#3182=ORIENTED_EDGE('',*,*,#486,.T.);
#3183=EDGE_CURVE('E1008',#485,#780,#3101,.T.);
#3184=ORIENTED_EDGE('',*,*,#3183,.T.);
#3185=ORIENTED_EDGE('',*,*,#781,.F.);
#3186=EDGE_CURVE('E1195',#601,#778,#3108,.T.);
#3187=ORIENTED_EDGE('',*,*,#3186,.F.);
#3188=ORIENTED_EDGE('',*,*,#602,.T.);
#3189=DIRECTION('',(0.,0.,1.));
#3190=VECTOR('',#3189,1.);
#3191=CARTESIAN_POINT('',(-52.9252123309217,11.6154181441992,37.2907972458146));
#3192=LINE('',#3191,#3190);
#3193=EDGE_CURVE('E1199',#1460,#593,#3192,.T.);
#3194=ORIENTED_EDGE('',*,*,#3193,.F.);
#3195=ORIENTED_EDGE('',*,*,#1461,.F.);
#3196=ORIENTED_EDGE('',*,*,#1681,.T.);
#3197=ORIENTED_EDGE('',*,*,#1503,.T.);
#3198=DIRECTION('',(0.,0.,-1.));
#3199=VECTOR('',#3198,1.);
#3200=CARTESIAN_POINT('',(-52.9252123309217,11.6154181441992,37.2907972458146));
#3201=LINE('',#3200,#3199);
#3202=EDGE_CURVE('E1206',#1498,#1527,#3201,.T.);
#3203=ORIENTED_EDGE('',*,*,#3202,.T.);
#3204=ORIENTED_EDGE('',*,*,#1528,.F.);
#3205=ORIENTED_EDGE('',*,*,#1671,.T.);
#3206=ORIENTED_EDGE('',*,*,#1565,.T.);
#3207=EDGE_CURVE('E1202',#1560,#1589,#3201,.T.);
#3208=ORIENTED_EDGE('',*,*,#3207,.T.);
#3209=ORIENTED_EDGE('',*,*,#1590,.F.);
#3210=ORIENTED_EDGE('',*,*,#1657,.T.);
#3211=ORIENTED_EDGE('',*,*,#1627,.T.);
#3212=DIRECTION('',(0.,0.,-1.));
#3213=VECTOR('',#3212,1.);
#3214=CARTESIAN_POINT('',(-52.9252123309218,11.6154181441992,-35.4864038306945));
#3215=LINE('',#3214,#3213);
#3216=EDGE_CURVE('E1203',#1622,#2672,#3215,.T.);
#3217=ORIENTED_EDGE('',*,*,#3216,.T.);
#3218=ORIENTED_EDGE('',*,*,#2673,.T.);
#3219=EDGE_CURVE('E1198',#950,#2664,#3108,.T.);
#3220=ORIENTED_EDGE('',*,*,#3219,.F.);
#3221=EDGE_LOOP('',(#3121,#3123,#3124,#3130,#3131,#3137,#3138,#3146,#3148,#3149,#3153,#3157,
#3159,#3160,#3164,#3166,#3167,#3168,#3169,#3171,#3172,#3178,#3179,#3181,#3182,#3184,#3185,#3187,
#3188,#3194,#3195,#3196,#3197,#3203,#3204,#3205,#3206,#3208,#3209,#3210,#3211,#3217,#3218,#3220));
#3222=FACE_BOUND('',#3221,.T.);
#3223=ADVANCED_FACE('F1022',(#3088,#3096,#3112,#3120,#3222),#3072,.T.);
#3224=DIRECTION('',(0.,1.,0.));
#3225=VECTOR('',#3224,1.);
#3226=CARTESIAN_POINT('',(52.9252123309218,11.6154181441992,1.5));
#3227=LINE('',#3226,#3225);
#3228=EDGE_CURVE('E1245',#3162,#1826,#3227,.T.);
#3229=ORIENTED_EDGE('',*,*,#3228,.F.);
#3230=ORIENTED_EDGE('',*,*,#3163,.T.);
#3231=ORIENTED_EDGE('',*,*,#2611,.T.);
#3232=ORIENTED_EDGE('',*,*,#1880,.F.);
#3233=ORIENTED_EDGE('',*,*,#1831,.F.);
#3234=EDGE_LOOP('',(#3229,#3230,#3231,#3232,#3233));
#3235=FACE_BOUND('',#3234,.T.);
#3236=ADVANCED_FACE('F1374',(#3235),#843,.T.);
#3237=ORIENTED_EDGE('',*,*,#3158,.F.);
#3238=DIRECTION('',(0.,1.,0.));
#3239=VECTOR('',#3238,1.);
#3240=CARTESIAN_POINT('',(52.9252123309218,11.6154181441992,-1.5));
#3241=LINE('',#3240,#3239);
#3242=EDGE_CURVE('E1247',#3155,#1757,#3241,.T.);
#3243=ORIENTED_EDGE('',*,*,#3242,.T.);
#3244=ORIENTED_EDGE('',*,*,#1760,.T.);
#3245=ORIENTED_EDGE('',*,*,#1810,.T.);
#3246=ORIENTED_EDGE('',*,*,#2625,.F.);
#3247=EDGE_LOOP('',(#3237,#3243,#3244,#3245,#3246));
#3248=FACE_BOUND('',#3247,.T.);
#3249=ADVANCED_FACE('F2084',(#3248),#874,.F.);
#3250=DIRECTION('',(0.,1.,0.));
#3251=VECTOR('',#3250,1.);
#3252=CARTESIAN_POINT('',(52.9252123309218,11.6154181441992,-26.4680979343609));
#3253=LINE('',#3252,#3251);
#3254=EDGE_CURVE('E1253',#3151,#1767,#3253,.T.);
#3255=ORIENTED_EDGE('',*,*,#3254,.F.);
#3256=ORIENTED_EDGE('',*,*,#3152,.T.);
#3257=ORIENTED_EDGE('',*,*,#2546,.T.);
#3258=ORIENTED_EDGE('',*,*,#1799,.F.);
#3259=ORIENTED_EDGE('',*,*,#1772,.F.);
#3260=EDGE_LOOP('',(#3255,#3256,#3257,#3258,#3259));
#3261=FACE_BOUND('',#3260,.T.);
#3262=ADVANCED_FACE('F2106',(#3261),#905,.T.);
#3263=ORIENTED_EDGE('',*,*,#3147,.F.);
#3264=DIRECTION('',(0.,1.,0.));
#3265=VECTOR('',#3264,1.);
#3266=CARTESIAN_POINT('',(52.9252123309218,11.6154181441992,-29.4680979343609));
#3267=LINE('',#3266,#3265);
#3268=EDGE_CURVE('E1447',#3144,#2751,#3267,.T.);
#3269=ORIENTED_EDGE('',*,*,#3268,.T.);
#3270=ORIENTED_EDGE('',*,*,#2752,.T.);
#3271=ORIENTED_EDGE('',*,*,#1732,.T.);
#3272=ORIENTED_EDGE('',*,*,#2560,.F.);
#3273=EDGE_LOOP('',(#3263,#3269,#3270,#3271,#3272));
#3274=FACE_BOUND('',#3273,.T.);
#3275=ADVANCED_FACE('F1846',(#3274),#936,.F.);
#3276=CARTESIAN_POINT('',(-52.9252123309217,11.6154181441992,37.2907972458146));
#3277=DIRECTION('',(-1.,0.,0.));
#3278=DIRECTION('',(0.,0.,1.));
#3279=AXIS2_PLACEMENT_3D('',#3276,#3277,#3278);
#3280=PLANE('',#3279);
#3281=ORIENTED_EDGE('',*,*,#2801,.F.);
#3282=ORIENTED_EDGE('',*,*,#1851,.T.);
#3283=ORIENTED_EDGE('',*,*,#1469,.F.);
#3284=ORIENTED_EDGE('',*,*,#3193,.T.);
#3285=ORIENTED_EDGE('',*,*,#594,.T.);
#3286=EDGE_LOOP('',(#3281,#3282,#3283,#3284,#3285));
#3287=FACE_BOUND('',#3286,.T.);
#3288=ADVANCED_FACE('F2000',(#3287),#3280,.T.);
#3289=CARTESIAN_POINT('',(-49.9252123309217,11.6154181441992,37.2907972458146));
#3290=DIRECTION('',(-1.,0.,0.));
#3291=DIRECTION('',(0.,0.,1.));
#3292=AXIS2_PLACEMENT_3D('',#3289,#3290,#3291);
#3293=PLANE('',#3292);
#3294=ORIENTED_EDGE('',*,*,#610,.F.);
#3295=ORIENTED_EDGE('',*,*,#3186,.T.);
#3296=ORIENTED_EDGE('',*,*,#803,.T.);
#3297=ORIENTED_EDGE('',*,*,#1377,.T.);
#3298=ORIENTED_EDGE('',*,*,#1428,.T.);
#3299=EDGE_LOOP('',(#3294,#3295,#3296,#3297,#3298));
#3300=FACE_BOUND('',#3299,.T.);
#3301=ADVANCED_FACE('F1993',(#3300),#3293,.F.);
#3302=CARTESIAN_POINT('',(-49.9252123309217,11.6154181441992,37.2907972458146));
#3303=DIRECTION('',(1.,0.,0.));
#3304=DIRECTION('',(0.,0.,-1.));
#3305=AXIS2_PLACEMENT_3D('',#3302,#3303,#3304);
#3306=PLANE('',#3305);
#3307=ORIENTED_EDGE('',*,*,#833,.F.);
#3308=ORIENTED_EDGE('',*,*,#3117,.T.);
#3309=ORIENTED_EDGE('',*,*,#865,.T.);
#3310=ORIENTED_EDGE('',*,*,#689,.F.);
#3311=EDGE_LOOP('',(#3307,#3308,#3309,#3310));
#3312=FACE_BOUND('',#3311,.T.);
#3313=ADVANCED_FACE('F2145',(#3312),#3306,.T.);
#3314=CARTESIAN_POINT('',(-52.9252123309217,11.6154181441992,37.2907972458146));
#3315=DIRECTION('',(1.,0.,0.));
#3316=DIRECTION('',(0.,0.,-1.));
#3317=AXIS2_PLACEMENT_3D('',#3314,#3315,#3316);
#3318=PLANE('',#3317);
#3319=ORIENTED_EDGE('',*,*,#3202,.F.);
#3320=ORIENTED_EDGE('',*,*,#1499,.T.);
#3321=ORIENTED_EDGE('',*,*,#1345,.T.);
#3322=ORIENTED_EDGE('',*,*,#1534,.F.);
#3323=EDGE_LOOP('',(#3319,#3320,#3321,#3322));
#3324=FACE_BOUND('',#3323,.T.);
#3325=ADVANCED_FACE('F2139',(#3324),#3318,.F.);
#3326=ORIENTED_EDGE('',*,*,#895,.F.);
#3327=ORIENTED_EDGE('',*,*,#3109,.T.);
#3328=ORIENTED_EDGE('',*,*,#927,.T.);
#3329=ORIENTED_EDGE('',*,*,#654,.F.);
#3330=EDGE_LOOP('',(#3326,#3327,#3328,#3329));
#3331=FACE_BOUND('',#3330,.T.);
#3332=ADVANCED_FACE('F2137',(#3331),#3306,.T.);
#3333=ORIENTED_EDGE('',*,*,#3207,.F.);
#3334=ORIENTED_EDGE('',*,*,#1561,.T.);
#3335=ORIENTED_EDGE('',*,*,#1318,.T.);
#3336=ORIENTED_EDGE('',*,*,#1596,.F.);
#3337=EDGE_LOOP('',(#3333,#3334,#3335,#3336));
#3338=FACE_BOUND('',#3337,.T.);
#3339=ADVANCED_FACE('F2135',(#3338),#3318,.F.);
#3340=ORIENTED_EDGE('',*,*,#724,.F.);
#3341=ORIENTED_EDGE('',*,*,#957,.F.);
#3342=ORIENTED_EDGE('',*,*,#3219,.T.);
#3343=ORIENTED_EDGE('',*,*,#2665,.T.);
#3344=ORIENTED_EDGE('',*,*,#757,.F.);
#3345=EDGE_LOOP('',(#3340,#3341,#3342,#3343,#3344));
#3346=FACE_BOUND('',#3345,.T.);
#3347=ADVANCED_FACE('F1904',(#3346),#3306,.T.);
#3348=ORIENTED_EDGE('',*,*,#1623,.T.);
#3349=ORIENTED_EDGE('',*,*,#1390,.T.);
#3350=ORIENTED_EDGE('',*,*,#1440,.T.);
#3351=ORIENTED_EDGE('',*,*,#2679,.F.);
#3352=ORIENTED_EDGE('',*,*,#3216,.F.);
#3353=EDGE_LOOP('',(#3348,#3349,#3350,#3351,#3352));
#3354=FACE_BOUND('',#3353,.T.);
#3355=ADVANCED_FACE('F1907',(#3354),#3318,.F.);
#3356=CARTESIAN_POINT('',(49.9252123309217,11.6154181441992,37.2907972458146));
#3357=DIRECTION('',(-1.,0.,0.));
#3358=DIRECTION('',(0.,0.,1.));
#3359=AXIS2_PLACEMENT_3D('',#3356,#3357,#3358);
#3360=PLANE('',#3359);
#3361=ORIENTED_EDGE('',*,*,#1012,.F.);
#3362=ORIENTED_EDGE('',*,*,#989,.T.);
#3363=ORIENTED_EDGE('',*,*,#1194,.F.);
#3364=ORIENTED_EDGE('',*,*,#3177,.T.);
#3365=ORIENTED_EDGE('',*,*,#510,.T.);
#3366=EDGE_LOOP('',(#3361,#3362,#3363,#3364,#3365));
#3367=FACE_BOUND('',#3366,.T.);
#3368=ADVANCED_FACE('F2149',(#3367),#3360,.T.);
#3369=CARTESIAN_POINT('',(52.9252123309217,11.6154181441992,37.2907972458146));
#3370=DIRECTION('',(-1.,0.,0.));
#3371=DIRECTION('',(0.,0.,1.));
#3372=AXIS2_PLACEMENT_3D('',#3369,#3370,#3371);
#3373=PLANE('',#3372);
#3374=ORIENTED_EDGE('',*,*,#526,.F.);
#3375=ORIENTED_EDGE('',*,*,#3170,.T.);
#3376=ORIENTED_EDGE('',*,*,#3042,.T.);
#3377=ORIENTED_EDGE('',*,*,#1026,.T.);
#3378=ORIENTED_EDGE('',*,*,#1059,.T.);
#3379=EDGE_LOOP('',(#3374,#3375,#3376,#3377,#3378));
#3380=FACE_BOUND('',#3379,.T.);
#3381=ADVANCED_FACE('F1967',(#3380),#3373,.F.);
#3382=CARTESIAN_POINT('',(52.9252123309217,11.6154181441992,37.2907972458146));
#3383=DIRECTION('',(1.,0.,0.));
#3384=DIRECTION('',(0.,0.,-1.));
#3385=AXIS2_PLACEMENT_3D('',#3382,#3383,#3384);
#3386=PLANE('',#3385);
#3387=ORIENTED_EDGE('',*,*,#3060,.F.);
#3388=ORIENTED_EDGE('',*,*,#3165,.T.);
#3389=ORIENTED_EDGE('',*,*,#3228,.T.);
#3390=ORIENTED_EDGE('',*,*,#1827,.F.);
#3391=EDGE_LOOP('',(#3387,#3388,#3389,#3390));
#3392=FACE_BOUND('',#3391,.T.);
#3393=ADVANCED_FACE('F1959',(#3392),#3386,.T.);
#3394=CARTESIAN_POINT('',(49.9252123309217,11.6154181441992,37.2907972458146));
#3395=DIRECTION('',(1.,0.,0.));
#3396=DIRECTION('',(0.,0.,-1.));
#3397=AXIS2_PLACEMENT_3D('',#3394,#3395,#3396);
#3398=PLANE('',#3397);
#3399=ORIENTED_EDGE('',*,*,#3084,.F.);
#3400=ORIENTED_EDGE('',*,*,#1217,.T.);
#3401=ORIENTED_EDGE('',*,*,#1122,.T.);
#3402=ORIENTED_EDGE('',*,*,#1238,.F.);
#3403=EDGE_LOOP('',(#3399,#3400,#3401,#3402));
#3404=FACE_BOUND('',#3403,.T.);
#3405=ADVANCED_FACE('F2795',(#3404),#3398,.F.);
#3406=ORIENTED_EDGE('',*,*,#3242,.F.);
#3407=ORIENTED_EDGE('',*,*,#3156,.T.);
#3408=ORIENTED_EDGE('',*,*,#3254,.T.);
#3409=ORIENTED_EDGE('',*,*,#1768,.F.);
#3410=EDGE_LOOP('',(#3406,#3407,#3408,#3409));
#3411=FACE_BOUND('',#3410,.T.);
#3412=ADVANCED_FACE('F2797',(#3411),#3386,.T.);
#3413=ORIENTED_EDGE('',*,*,#3092,.F.);
#3414=ORIENTED_EDGE('',*,*,#1261,.T.);
#3415=ORIENTED_EDGE('',*,*,#1095,.T.);
#3416=ORIENTED_EDGE('',*,*,#1282,.F.);
#3417=EDGE_LOOP('',(#3413,#3414,#3415,#3416));
#3418=FACE_BOUND('',#3417,.T.);
#3419=ADVANCED_FACE('F2805',(#3418),#3398,.F.);
#3420=ORIENTED_EDGE('',*,*,#2760,.F.);
#3421=ORIENTED_EDGE('',*,*,#3268,.F.);
#3422=ORIENTED_EDGE('',*,*,#3145,.T.);
#3423=ORIENTED_EDGE('',*,*,#2730,.T.);
#3424=ORIENTED_EDGE('',*,*,#2960,.F.);
#3425=EDGE_LOOP('',(#3420,#3421,#3422,#3423,#3424));
#3426=FACE_BOUND('',#3425,.T.);
#3427=ADVANCED_FACE('F1953',(#3426),#3386,.T.);
#3428=ORIENTED_EDGE('',*,*,#1305,.T.);
#3429=ORIENTED_EDGE('',*,*,#1149,.T.);
#3430=ORIENTED_EDGE('',*,*,#1173,.T.);
#3431=ORIENTED_EDGE('',*,*,#2744,.F.);
#3432=ORIENTED_EDGE('',*,*,#3136,.F.);
#3433=EDGE_LOOP('',(#3428,#3429,#3430,#3431,#3432));
#3434=FACE_BOUND('',#3433,.T.);
#3435=ADVANCED_FACE('F1837',(#3434),#3398,.F.);
#3436=CARTESIAN_POINT('',(1.5,11.6154181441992,37.2907972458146));
#3437=DIRECTION('',(1.,0.,0.));
#3438=DIRECTION('',(0.,0.,-1.));
#3439=AXIS2_PLACEMENT_3D('',#3436,#3437,#3438);
#3440=PLANE('',#3439);
#3441=ORIENTED_EDGE('',*,*,#1210,.F.);
#3442=ORIENTED_EDGE('',*,*,#3077,.T.);
#3443=ORIENTED_EDGE('',*,*,#1228,.T.);
#3444=ORIENTED_EDGE('',*,*,#1112,.F.);
#3445=EDGE_LOOP('',(#3441,#3442,#3443,#3444));
#3446=FACE_BOUND('',#3445,.T.);
#3447=ADVANCED_FACE('F1361',(#3446),#3440,.T.);
#3448=CARTESIAN_POINT('',(-1.5,11.6154181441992,37.2907972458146));
#3449=DIRECTION('',(1.,0.,0.));
#3450=DIRECTION('',(0.,0.,-1.));
#3451=AXIS2_PLACEMENT_3D('',#3448,#3449,#3450);
#3452=PLANE('',#3451);
#3453=ORIENTED_EDGE('',*,*,#3114,.F.);
#3454=ORIENTED_EDGE('',*,*,#819,.T.);
#3455=ORIENTED_EDGE('',*,*,#673,.T.);
#3456=ORIENTED_EDGE('',*,*,#858,.F.);
#3457=EDGE_LOOP('',(#3453,#3454,#3455,#3456));
#3458=FACE_BOUND('',#3457,.T.);
#3459=ADVANCED_FACE('F1883',(#3458),#3452,.F.);
#3460=ORIENTED_EDGE('',*,*,#1254,.F.);
#3461=ORIENTED_EDGE('',*,*,#3089,.T.);
#3462=ORIENTED_EDGE('',*,*,#1272,.T.);
#3463=ORIENTED_EDGE('',*,*,#1085,.F.);
#3464=EDGE_LOOP('',(#3460,#3461,#3462,#3463));
#3465=FACE_BOUND('',#3464,.T.);
#3466=ADVANCED_FACE('F2839',(#3465),#3440,.T.);
#3467=ORIENTED_EDGE('',*,*,#3102,.F.);
#3468=ORIENTED_EDGE('',*,*,#881,.T.);
#3469=ORIENTED_EDGE('',*,*,#638,.T.);
#3470=ORIENTED_EDGE('',*,*,#920,.F.);
#3471=EDGE_LOOP('',(#3467,#3468,#3469,#3470));
#3472=FACE_BOUND('',#3471,.T.);
#3473=ADVANCED_FACE('F2099',(#3472),#3452,.F.);
#3474=ORIENTED_EDGE('',*,*,#789,.F.);
#3475=ORIENTED_EDGE('',*,*,#3183,.F.);
#3476=ORIENTED_EDGE('',*,*,#620,.T.);
#3477=ORIENTED_EDGE('',*,*,#1420,.F.);
#3478=ORIENTED_EDGE('',*,*,#1367,.F.);
#3479=EDGE_LOOP('',(#3474,#3475,#3476,#3477,#3478));
#3480=FACE_BOUND('',#3479,.T.);
#3481=ADVANCED_FACE('F1007',(#3480),#3452,.F.);
#3482=ORIENTED_EDGE('',*,*,#3180,.T.);
#3483=ORIENTED_EDGE('',*,*,#1184,.T.);
#3484=ORIENTED_EDGE('',*,*,#979,.F.);
#3485=ORIENTED_EDGE('',*,*,#1004,.T.);
#3486=ORIENTED_EDGE('',*,*,#494,.F.);
#3487=EDGE_LOOP('',(#3482,#3483,#3484,#3485,#3486));
#3488=FACE_BOUND('',#3487,.T.);
#3489=ADVANCED_FACE('F2840',(#3488),#3440,.T.);
#3490=CARTESIAN_POINT('',(1.5,11.6154181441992,-37.5915294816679));
#3491=DIRECTION('',(1.,0.,0.));
#3492=DIRECTION('',(0.,0.,-1.));
#3493=AXIS2_PLACEMENT_3D('',#3490,#3491,#3492);
#3494=PLANE('',#3493);
#3495=ORIENTED_EDGE('',*,*,#1162,.F.);
#3496=ORIENTED_EDGE('',*,*,#1139,.F.);
#3497=ORIENTED_EDGE('',*,*,#1298,.F.);
#3498=ORIENTED_EDGE('',*,*,#3129,.T.);
#3499=ORIENTED_EDGE('',*,*,#2642,.T.);
#3500=EDGE_LOOP('',(#3495,#3496,#3497,#3498,#3499));
#3501=FACE_BOUND('',#3500,.T.);
#3502=ADVANCED_FACE('F1832',(#3501),#3494,.T.);
#3503=CARTESIAN_POINT('',(-1.5,11.6154181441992,-37.5915294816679));
#3504=DIRECTION('',(1.,0.,0.));
#3505=DIRECTION('',(0.,0.,-1.));
#3506=AXIS2_PLACEMENT_3D('',#3503,#3504,#3505);
#3507=PLANE('',#3506);
#3508=ORIENTED_EDGE('',*,*,#2656,.F.);
#3509=ORIENTED_EDGE('',*,*,#3122,.F.);
#3510=ORIENTED_EDGE('',*,*,#943,.T.);
#3511=ORIENTED_EDGE('',*,*,#708,.T.);
#3512=ORIENTED_EDGE('',*,*,#747,.T.);
#3513=EDGE_LOOP('',(#3508,#3509,#3510,#3511,#3512));
#3514=FACE_BOUND('',#3513,.T.);
#3515=ADVANCED_FACE('F1896',(#3514),#3507,.F.);
#3516=CLOSED_SHELL('',(#624,#664,#699,#734,#767,#807,#838,#869,#900,#931,#962,#993,#1017,#1053,
#1072,#1099,#1126,#1153,#1177,#1199,#1221,#1243,#1265,#1287,#1309,#1336,#1359,#1381,#1413,#1432,
#1456,#1492,#1523,#1554,#1585,#1616,#1647,#1717,#1755,#1778,#1790,#1814,#1837,#1844,#1871,#1895,
#1908,#1994,#2025,#2084,#2124,#2183,#2259,#2318,#2336,#2360,#2378,#2396,#2414,#2432,#2450,#2468,
#2486,#2504,#2522,#2534,#2630,#2749,#2776,#2794,#2813,#2831,#2849,#2861,#2879,#2892,#2905,#2923,
#2941,#2953,#2966,#2983,#3000,#3012,#3020,#3028,#3035,#3051,#3067,#3223,#3236,#3249,#3262,#3275,
#3288,#3301,#3313,#3325,#3332,#3339,#3347,#3355,#3368,#3381,#3393,#3405,#3412,#3419,#3427,#3435,
#3447,#3459,#3466,#3473,#3481,#3489,#3502,#3515));
#3517=MANIFOLD_SOLID_BREP('B6',#3516);
#3518=ADVANCED_BREP_SHAPE_REPRESENTATION('',(#18,#472,#3517),#14);
#3519=SHAPE_DEFINITION_REPRESENTATION(#9,#3518);
ENDSEC;
END-ISO-10303-21;
